VERSION 5.8 ;
BUSBITCHARS "[]" ;
DIVIDERCHAR "/" ;
UNITS
    DATABASE MICRONS 1000 ;
END UNITS

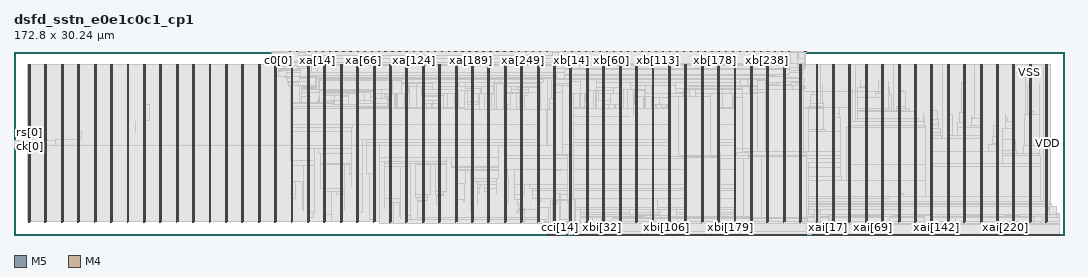
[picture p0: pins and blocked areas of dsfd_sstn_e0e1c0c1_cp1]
MACRO dsfd_sstn_e0e1c0c1_cp1
  FOREIGN dsfd_sstn_e0e1c0c1_cp1 0 0 ;
  CLASS BLOCK ;
  SIZE 172.8 BY 30.24 ;
  PIN c0[0]
    DIRECTION INPUT ;
    USE SIGNAL ;
    PORT
      LAYER M5 ;
        RECT  43.584 30.156 43.608 30.24 ;
    END
  END c0[0]
  PIN c0[1]
    DIRECTION INPUT ;
    USE SIGNAL ;
    PORT
      LAYER M5 ;
        RECT  43.728 30.156 43.752 30.24 ;
    END
  END c0[1]
  PIN c1[0]
    DIRECTION INPUT ;
    USE SIGNAL ;
    PORT
      LAYER M5 ;
        RECT  130.176 30.156 130.2 30.24 ;
    END
  END c1[0]
  PIN c1[1]
    DIRECTION INPUT ;
    USE SIGNAL ;
    PORT
      LAYER M5 ;
        RECT  130.32 30.156 130.344 30.24 ;
    END
  END c1[1]
  PIN cc[0]
    DIRECTION OUTPUT ;
    USE SIGNAL ;
    PORT
      LAYER M5 ;
        RECT  44.832 30.156 44.856 30.24 ;
    END
  END cc[0]
  PIN cc[10]
    DIRECTION OUTPUT ;
    USE SIGNAL ;
    PORT
      LAYER M5 ;
        RECT  46.272 30.156 46.296 30.24 ;
    END
  END cc[10]
  PIN cc[11]
    DIRECTION OUTPUT ;
    USE SIGNAL ;
    PORT
      LAYER M5 ;
        RECT  46.416 30.156 46.44 30.24 ;
    END
  END cc[11]
  PIN cc[12]
    DIRECTION OUTPUT ;
    USE SIGNAL ;
    PORT
      LAYER M5 ;
        RECT  46.56 30.156 46.584 30.24 ;
    END
  END cc[12]
  PIN cc[13]
    DIRECTION OUTPUT ;
    USE SIGNAL ;
    PORT
      LAYER M5 ;
        RECT  46.704 30.156 46.728 30.24 ;
    END
  END cc[13]
  PIN cc[14]
    DIRECTION OUTPUT ;
    USE SIGNAL ;
    PORT
      LAYER M5 ;
        RECT  46.848 30.156 46.872 30.24 ;
    END
  END cc[14]
  PIN cc[1]
    DIRECTION OUTPUT ;
    USE SIGNAL ;
    PORT
      LAYER M5 ;
        RECT  44.976 30.156 45 30.24 ;
    END
  END cc[1]
  PIN cc[2]
    DIRECTION OUTPUT ;
    USE SIGNAL ;
    PORT
      LAYER M5 ;
        RECT  45.12 30.156 45.144 30.24 ;
    END
  END cc[2]
  PIN cc[3]
    DIRECTION OUTPUT ;
    USE SIGNAL ;
    PORT
      LAYER M5 ;
        RECT  45.264 30.156 45.288 30.24 ;
    END
  END cc[3]
  PIN cc[4]
    DIRECTION OUTPUT ;
    USE SIGNAL ;
    PORT
      LAYER M5 ;
        RECT  45.408 30.156 45.432 30.24 ;
    END
  END cc[4]
  PIN cc[5]
    DIRECTION OUTPUT ;
    USE SIGNAL ;
    PORT
      LAYER M5 ;
        RECT  45.552 30.156 45.576 30.24 ;
    END
  END cc[5]
  PIN cc[6]
    DIRECTION OUTPUT ;
    USE SIGNAL ;
    PORT
      LAYER M5 ;
        RECT  45.696 30.156 45.72 30.24 ;
    END
  END cc[6]
  PIN cc[7]
    DIRECTION OUTPUT ;
    USE SIGNAL ;
    PORT
      LAYER M5 ;
        RECT  45.84 30.156 45.864 30.24 ;
    END
  END cc[7]
  PIN cc[8]
    DIRECTION OUTPUT ;
    USE SIGNAL ;
    PORT
      LAYER M5 ;
        RECT  45.984 30.156 46.008 30.24 ;
    END
  END cc[8]
  PIN cc[9]
    DIRECTION OUTPUT ;
    USE SIGNAL ;
    PORT
      LAYER M5 ;
        RECT  46.128 30.156 46.152 30.24 ;
    END
  END cc[9]
  PIN cci[0]
    DIRECTION INPUT ;
    USE SIGNAL ;
    PORT
      LAYER M5 ;
        RECT  87.792 0 87.816 0.084 ;
    END
  END cci[0]
  PIN cci[10]
    DIRECTION INPUT ;
    USE SIGNAL ;
    PORT
      LAYER M5 ;
        RECT  89.232 0 89.256 0.084 ;
    END
  END cci[10]
  PIN cci[11]
    DIRECTION INPUT ;
    USE SIGNAL ;
    PORT
      LAYER M5 ;
        RECT  89.376 0 89.4 0.084 ;
    END
  END cci[11]
  PIN cci[12]
    DIRECTION INPUT ;
    USE SIGNAL ;
    PORT
      LAYER M5 ;
        RECT  89.52 0 89.544 0.084 ;
    END
  END cci[12]
  PIN cci[13]
    DIRECTION INPUT ;
    USE SIGNAL ;
    PORT
      LAYER M5 ;
        RECT  89.664 0 89.688 0.084 ;
    END
  END cci[13]
  PIN cci[14]
    DIRECTION INPUT ;
    USE SIGNAL ;
    PORT
      LAYER M5 ;
        RECT  89.808 0 89.832 0.084 ;
    END
  END cci[14]
  PIN cci[1]
    DIRECTION INPUT ;
    USE SIGNAL ;
    PORT
      LAYER M5 ;
        RECT  87.936 0 87.96 0.084 ;
    END
  END cci[1]
  PIN cci[2]
    DIRECTION INPUT ;
    USE SIGNAL ;
    PORT
      LAYER M5 ;
        RECT  88.08 0 88.104 0.084 ;
    END
  END cci[2]
  PIN cci[3]
    DIRECTION INPUT ;
    USE SIGNAL ;
    PORT
      LAYER M5 ;
        RECT  88.224 0 88.248 0.084 ;
    END
  END cci[3]
  PIN cci[4]
    DIRECTION INPUT ;
    USE SIGNAL ;
    PORT
      LAYER M5 ;
        RECT  88.368 0 88.392 0.084 ;
    END
  END cci[4]
  PIN cci[5]
    DIRECTION INPUT ;
    USE SIGNAL ;
    PORT
      LAYER M5 ;
        RECT  88.512 0 88.536 0.084 ;
    END
  END cci[5]
  PIN cci[6]
    DIRECTION INPUT ;
    USE SIGNAL ;
    PORT
      LAYER M5 ;
        RECT  88.656 0 88.68 0.084 ;
    END
  END cci[6]
  PIN cci[7]
    DIRECTION INPUT ;
    USE SIGNAL ;
    PORT
      LAYER M5 ;
        RECT  88.8 0 88.824 0.084 ;
    END
  END cci[7]
  PIN cci[8]
    DIRECTION INPUT ;
    USE SIGNAL ;
    PORT
      LAYER M5 ;
        RECT  88.944 0 88.968 0.084 ;
    END
  END cci[8]
  PIN cci[9]
    DIRECTION INPUT ;
    USE SIGNAL ;
    PORT
      LAYER M5 ;
        RECT  89.088 0 89.112 0.084 ;
    END
  END cci[9]
  PIN ck[0]
    DIRECTION INPUT ;
    USE SIGNAL ;
    PORT
      LAYER M4 ;
        RECT  0 14.592 0.084 14.616 ;
    END
    PORT
      LAYER M4 ;
        RECT  0.06 14.592 0.097 14.616 ;
    END
  END ck[0]
  PIN e0[0]
    DIRECTION INPUT ;
    USE SIGNAL ;
    PORT
      LAYER M5 ;
        RECT  42.336 30.156 42.36 30.24 ;
    END
  END e0[0]
  PIN e0[1]
    DIRECTION INPUT ;
    USE SIGNAL ;
    PORT
      LAYER M5 ;
        RECT  42.48 30.156 42.504 30.24 ;
    END
  END e0[1]
  PIN e1[0]
    DIRECTION INPUT ;
    USE SIGNAL ;
    PORT
      LAYER M5 ;
        RECT  128.928 30.156 128.952 30.24 ;
    END
  END e1[0]
  PIN e1[1]
    DIRECTION INPUT ;
    USE SIGNAL ;
    PORT
      LAYER M5 ;
        RECT  129.072 30.156 129.096 30.24 ;
    END
  END e1[1]
  PIN rs[0]
    DIRECTION INPUT ;
    USE SIGNAL ;
    PORT
      LAYER M4 ;
        RECT  0 15.6 0.084 15.624 ;
    END
    PORT
      LAYER M4 ;
        RECT  0.06 15.6 0.097 15.624 ;
    END
  END rs[0]
  PIN so[0]
    DIRECTION OUTPUT ;
    USE SIGNAL ;
    PORT
      LAYER M5 ;
        RECT  90.912 0 90.936 0.084 ;
    END
  END so[0]
  PIN so[1]
    DIRECTION OUTPUT ;
    USE SIGNAL ;
    PORT
      LAYER M5 ;
        RECT  91.056 0 91.08 0.084 ;
    END
  END so[1]
  PIN xa[0]
    DIRECTION OUTPUT ;
    USE SIGNAL ;
    PORT
      LAYER M5 ;
        RECT  47.952 30.156 47.976 30.24 ;
    END
  END xa[0]
  PIN xa[100]
    DIRECTION OUTPUT ;
    USE SIGNAL ;
    PORT
      LAYER M5 ;
        RECT  62.352 30.156 62.376 30.24 ;
    END
  END xa[100]
  PIN xa[101]
    DIRECTION OUTPUT ;
    USE SIGNAL ;
    PORT
      LAYER M5 ;
        RECT  62.496 30.156 62.52 30.24 ;
    END
  END xa[101]
  PIN xa[102]
    DIRECTION OUTPUT ;
    USE SIGNAL ;
    PORT
      LAYER M5 ;
        RECT  62.64 30.156 62.664 30.24 ;
    END
  END xa[102]
  PIN xa[103]
    DIRECTION OUTPUT ;
    USE SIGNAL ;
    PORT
      LAYER M5 ;
        RECT  62.784 30.156 62.808 30.24 ;
    END
  END xa[103]
  PIN xa[104]
    DIRECTION OUTPUT ;
    USE SIGNAL ;
    PORT
      LAYER M5 ;
        RECT  62.928 30.156 62.952 30.24 ;
    END
  END xa[104]
  PIN xa[105]
    DIRECTION OUTPUT ;
    USE SIGNAL ;
    PORT
      LAYER M5 ;
        RECT  63.072 30.156 63.096 30.24 ;
    END
  END xa[105]
  PIN xa[106]
    DIRECTION OUTPUT ;
    USE SIGNAL ;
    PORT
      LAYER M5 ;
        RECT  63.216 30.156 63.24 30.24 ;
    END
  END xa[106]
  PIN xa[107]
    DIRECTION OUTPUT ;
    USE SIGNAL ;
    PORT
      LAYER M5 ;
        RECT  63.36 30.156 63.384 30.24 ;
    END
  END xa[107]
  PIN xa[108]
    DIRECTION OUTPUT ;
    USE SIGNAL ;
    PORT
      LAYER M5 ;
        RECT  63.504 30.156 63.528 30.24 ;
    END
  END xa[108]
  PIN xa[109]
    DIRECTION OUTPUT ;
    USE SIGNAL ;
    PORT
      LAYER M5 ;
        RECT  63.648 30.156 63.672 30.24 ;
    END
  END xa[109]
  PIN xa[10]
    DIRECTION OUTPUT ;
    USE SIGNAL ;
    PORT
      LAYER M5 ;
        RECT  49.392 30.156 49.416 30.24 ;
    END
  END xa[10]
  PIN xa[110]
    DIRECTION OUTPUT ;
    USE SIGNAL ;
    PORT
      LAYER M5 ;
        RECT  63.792 30.156 63.816 30.24 ;
    END
  END xa[110]
  PIN xa[111]
    DIRECTION OUTPUT ;
    USE SIGNAL ;
    PORT
      LAYER M5 ;
        RECT  63.936 30.156 63.96 30.24 ;
    END
  END xa[111]
  PIN xa[112]
    DIRECTION OUTPUT ;
    USE SIGNAL ;
    PORT
      LAYER M5 ;
        RECT  64.08 30.156 64.104 30.24 ;
    END
  END xa[112]
  PIN xa[113]
    DIRECTION OUTPUT ;
    USE SIGNAL ;
    PORT
      LAYER M5 ;
        RECT  64.224 30.156 64.248 30.24 ;
    END
  END xa[113]
  PIN xa[114]
    DIRECTION OUTPUT ;
    USE SIGNAL ;
    PORT
      LAYER M5 ;
        RECT  64.368 30.156 64.392 30.24 ;
    END
  END xa[114]
  PIN xa[115]
    DIRECTION OUTPUT ;
    USE SIGNAL ;
    PORT
      LAYER M5 ;
        RECT  64.512 30.156 64.536 30.24 ;
    END
  END xa[115]
  PIN xa[116]
    DIRECTION OUTPUT ;
    USE SIGNAL ;
    PORT
      LAYER M5 ;
        RECT  64.656 30.156 64.68 30.24 ;
    END
  END xa[116]
  PIN xa[117]
    DIRECTION OUTPUT ;
    USE SIGNAL ;
    PORT
      LAYER M5 ;
        RECT  64.8 30.156 64.824 30.24 ;
    END
  END xa[117]
  PIN xa[118]
    DIRECTION OUTPUT ;
    USE SIGNAL ;
    PORT
      LAYER M5 ;
        RECT  64.944 30.156 64.968 30.24 ;
    END
  END xa[118]
  PIN xa[119]
    DIRECTION OUTPUT ;
    USE SIGNAL ;
    PORT
      LAYER M5 ;
        RECT  65.088 30.156 65.112 30.24 ;
    END
  END xa[119]
  PIN xa[11]
    DIRECTION OUTPUT ;
    USE SIGNAL ;
    PORT
      LAYER M5 ;
        RECT  49.536 30.156 49.56 30.24 ;
    END
  END xa[11]
  PIN xa[120]
    DIRECTION OUTPUT ;
    USE SIGNAL ;
    PORT
      LAYER M5 ;
        RECT  65.232 30.156 65.256 30.24 ;
    END
  END xa[120]
  PIN xa[121]
    DIRECTION OUTPUT ;
    USE SIGNAL ;
    PORT
      LAYER M5 ;
        RECT  65.376 30.156 65.4 30.24 ;
    END
  END xa[121]
  PIN xa[122]
    DIRECTION OUTPUT ;
    USE SIGNAL ;
    PORT
      LAYER M5 ;
        RECT  65.52 30.156 65.544 30.24 ;
    END
  END xa[122]
  PIN xa[123]
    DIRECTION OUTPUT ;
    USE SIGNAL ;
    PORT
      LAYER M5 ;
        RECT  65.664 30.156 65.688 30.24 ;
    END
  END xa[123]
  PIN xa[124]
    DIRECTION OUTPUT ;
    USE SIGNAL ;
    PORT
      LAYER M5 ;
        RECT  65.808 30.156 65.832 30.24 ;
    END
  END xa[124]
  PIN xa[125]
    DIRECTION OUTPUT ;
    USE SIGNAL ;
    PORT
      LAYER M5 ;
        RECT  65.952 30.156 65.976 30.24 ;
    END
  END xa[125]
  PIN xa[126]
    DIRECTION OUTPUT ;
    USE SIGNAL ;
    PORT
      LAYER M5 ;
        RECT  66.096 30.156 66.12 30.24 ;
    END
  END xa[126]
  PIN xa[127]
    DIRECTION OUTPUT ;
    USE SIGNAL ;
    PORT
      LAYER M5 ;
        RECT  66.24 30.156 66.264 30.24 ;
    END
  END xa[127]
  PIN xa[128]
    DIRECTION OUTPUT ;
    USE SIGNAL ;
    PORT
      LAYER M5 ;
        RECT  66.384 30.156 66.408 30.24 ;
    END
  END xa[128]
  PIN xa[129]
    DIRECTION OUTPUT ;
    USE SIGNAL ;
    PORT
      LAYER M5 ;
        RECT  66.528 30.156 66.552 30.24 ;
    END
  END xa[129]
  PIN xa[12]
    DIRECTION OUTPUT ;
    USE SIGNAL ;
    PORT
      LAYER M5 ;
        RECT  49.68 30.156 49.704 30.24 ;
    END
  END xa[12]
  PIN xa[130]
    DIRECTION OUTPUT ;
    USE SIGNAL ;
    PORT
      LAYER M5 ;
        RECT  66.672 30.156 66.696 30.24 ;
    END
  END xa[130]
  PIN xa[131]
    DIRECTION OUTPUT ;
    USE SIGNAL ;
    PORT
      LAYER M5 ;
        RECT  66.816 30.156 66.84 30.24 ;
    END
  END xa[131]
  PIN xa[132]
    DIRECTION OUTPUT ;
    USE SIGNAL ;
    PORT
      LAYER M5 ;
        RECT  66.96 30.156 66.984 30.24 ;
    END
  END xa[132]
  PIN xa[133]
    DIRECTION OUTPUT ;
    USE SIGNAL ;
    PORT
      LAYER M5 ;
        RECT  67.104 30.156 67.128 30.24 ;
    END
  END xa[133]
  PIN xa[134]
    DIRECTION OUTPUT ;
    USE SIGNAL ;
    PORT
      LAYER M5 ;
        RECT  67.248 30.156 67.272 30.24 ;
    END
  END xa[134]
  PIN xa[135]
    DIRECTION OUTPUT ;
    USE SIGNAL ;
    PORT
      LAYER M5 ;
        RECT  67.392 30.156 67.416 30.24 ;
    END
  END xa[135]
  PIN xa[136]
    DIRECTION OUTPUT ;
    USE SIGNAL ;
    PORT
      LAYER M5 ;
        RECT  67.536 30.156 67.56 30.24 ;
    END
  END xa[136]
  PIN xa[137]
    DIRECTION OUTPUT ;
    USE SIGNAL ;
    PORT
      LAYER M5 ;
        RECT  67.68 30.156 67.704 30.24 ;
    END
  END xa[137]
  PIN xa[138]
    DIRECTION OUTPUT ;
    USE SIGNAL ;
    PORT
      LAYER M5 ;
        RECT  67.824 30.156 67.848 30.24 ;
    END
  END xa[138]
  PIN xa[139]
    DIRECTION OUTPUT ;
    USE SIGNAL ;
    PORT
      LAYER M5 ;
        RECT  67.968 30.156 67.992 30.24 ;
    END
  END xa[139]
  PIN xa[13]
    DIRECTION OUTPUT ;
    USE SIGNAL ;
    PORT
      LAYER M5 ;
        RECT  49.824 30.156 49.848 30.24 ;
    END
  END xa[13]
  PIN xa[140]
    DIRECTION OUTPUT ;
    USE SIGNAL ;
    PORT
      LAYER M5 ;
        RECT  68.112 30.156 68.136 30.24 ;
    END
  END xa[140]
  PIN xa[141]
    DIRECTION OUTPUT ;
    USE SIGNAL ;
    PORT
      LAYER M5 ;
        RECT  68.256 30.156 68.28 30.24 ;
    END
  END xa[141]
  PIN xa[142]
    DIRECTION OUTPUT ;
    USE SIGNAL ;
    PORT
      LAYER M5 ;
        RECT  68.4 30.156 68.424 30.24 ;
    END
  END xa[142]
  PIN xa[143]
    DIRECTION OUTPUT ;
    USE SIGNAL ;
    PORT
      LAYER M5 ;
        RECT  68.544 30.156 68.568 30.24 ;
    END
  END xa[143]
  PIN xa[144]
    DIRECTION OUTPUT ;
    USE SIGNAL ;
    PORT
      LAYER M5 ;
        RECT  68.688 30.156 68.712 30.24 ;
    END
  END xa[144]
  PIN xa[145]
    DIRECTION OUTPUT ;
    USE SIGNAL ;
    PORT
      LAYER M5 ;
        RECT  68.832 30.156 68.856 30.24 ;
    END
  END xa[145]
  PIN xa[146]
    DIRECTION OUTPUT ;
    USE SIGNAL ;
    PORT
      LAYER M5 ;
        RECT  68.976 30.156 69 30.24 ;
    END
  END xa[146]
  PIN xa[147]
    DIRECTION OUTPUT ;
    USE SIGNAL ;
    PORT
      LAYER M5 ;
        RECT  69.12 30.156 69.144 30.24 ;
    END
  END xa[147]
  PIN xa[148]
    DIRECTION OUTPUT ;
    USE SIGNAL ;
    PORT
      LAYER M5 ;
        RECT  69.264 30.156 69.288 30.24 ;
    END
  END xa[148]
  PIN xa[149]
    DIRECTION OUTPUT ;
    USE SIGNAL ;
    PORT
      LAYER M5 ;
        RECT  69.408 30.156 69.432 30.24 ;
    END
  END xa[149]
  PIN xa[14]
    DIRECTION OUTPUT ;
    USE SIGNAL ;
    PORT
      LAYER M5 ;
        RECT  49.968 30.156 49.992 30.24 ;
    END
  END xa[14]
  PIN xa[150]
    DIRECTION OUTPUT ;
    USE SIGNAL ;
    PORT
      LAYER M5 ;
        RECT  69.552 30.156 69.576 30.24 ;
    END
  END xa[150]
  PIN xa[151]
    DIRECTION OUTPUT ;
    USE SIGNAL ;
    PORT
      LAYER M5 ;
        RECT  69.696 30.156 69.72 30.24 ;
    END
  END xa[151]
  PIN xa[152]
    DIRECTION OUTPUT ;
    USE SIGNAL ;
    PORT
      LAYER M5 ;
        RECT  69.84 30.156 69.864 30.24 ;
    END
  END xa[152]
  PIN xa[153]
    DIRECTION OUTPUT ;
    USE SIGNAL ;
    PORT
      LAYER M5 ;
        RECT  69.984 30.156 70.008 30.24 ;
    END
  END xa[153]
  PIN xa[154]
    DIRECTION OUTPUT ;
    USE SIGNAL ;
    PORT
      LAYER M5 ;
        RECT  70.128 30.156 70.152 30.24 ;
    END
  END xa[154]
  PIN xa[155]
    DIRECTION OUTPUT ;
    USE SIGNAL ;
    PORT
      LAYER M5 ;
        RECT  70.272 30.156 70.296 30.24 ;
    END
  END xa[155]
  PIN xa[156]
    DIRECTION OUTPUT ;
    USE SIGNAL ;
    PORT
      LAYER M5 ;
        RECT  70.416 30.156 70.44 30.24 ;
    END
  END xa[156]
  PIN xa[157]
    DIRECTION OUTPUT ;
    USE SIGNAL ;
    PORT
      LAYER M5 ;
        RECT  70.56 30.156 70.584 30.24 ;
    END
  END xa[157]
  PIN xa[158]
    DIRECTION OUTPUT ;
    USE SIGNAL ;
    PORT
      LAYER M5 ;
        RECT  70.704 30.156 70.728 30.24 ;
    END
  END xa[158]
  PIN xa[159]
    DIRECTION OUTPUT ;
    USE SIGNAL ;
    PORT
      LAYER M5 ;
        RECT  70.848 30.156 70.872 30.24 ;
    END
  END xa[159]
  PIN xa[15]
    DIRECTION OUTPUT ;
    USE SIGNAL ;
    PORT
      LAYER M5 ;
        RECT  50.112 30.156 50.136 30.24 ;
    END
  END xa[15]
  PIN xa[160]
    DIRECTION OUTPUT ;
    USE SIGNAL ;
    PORT
      LAYER M5 ;
        RECT  70.992 30.156 71.016 30.24 ;
    END
  END xa[160]
  PIN xa[161]
    DIRECTION OUTPUT ;
    USE SIGNAL ;
    PORT
      LAYER M5 ;
        RECT  71.136 30.156 71.16 30.24 ;
    END
  END xa[161]
  PIN xa[162]
    DIRECTION OUTPUT ;
    USE SIGNAL ;
    PORT
      LAYER M5 ;
        RECT  71.28 30.156 71.304 30.24 ;
    END
  END xa[162]
  PIN xa[163]
    DIRECTION OUTPUT ;
    USE SIGNAL ;
    PORT
      LAYER M5 ;
        RECT  71.424 30.156 71.448 30.24 ;
    END
  END xa[163]
  PIN xa[164]
    DIRECTION OUTPUT ;
    USE SIGNAL ;
    PORT
      LAYER M5 ;
        RECT  71.568 30.156 71.592 30.24 ;
    END
  END xa[164]
  PIN xa[165]
    DIRECTION OUTPUT ;
    USE SIGNAL ;
    PORT
      LAYER M5 ;
        RECT  71.712 30.156 71.736 30.24 ;
    END
  END xa[165]
  PIN xa[166]
    DIRECTION OUTPUT ;
    USE SIGNAL ;
    PORT
      LAYER M5 ;
        RECT  71.856 30.156 71.88 30.24 ;
    END
  END xa[166]
  PIN xa[167]
    DIRECTION OUTPUT ;
    USE SIGNAL ;
    PORT
      LAYER M5 ;
        RECT  72 30.156 72.024 30.24 ;
    END
  END xa[167]
  PIN xa[168]
    DIRECTION OUTPUT ;
    USE SIGNAL ;
    PORT
      LAYER M5 ;
        RECT  72.144 30.156 72.168 30.24 ;
    END
  END xa[168]
  PIN xa[169]
    DIRECTION OUTPUT ;
    USE SIGNAL ;
    PORT
      LAYER M5 ;
        RECT  72.288 30.156 72.312 30.24 ;
    END
  END xa[169]
  PIN xa[16]
    DIRECTION OUTPUT ;
    USE SIGNAL ;
    PORT
      LAYER M5 ;
        RECT  50.256 30.156 50.28 30.24 ;
    END
  END xa[16]
  PIN xa[170]
    DIRECTION OUTPUT ;
    USE SIGNAL ;
    PORT
      LAYER M5 ;
        RECT  72.432 30.156 72.456 30.24 ;
    END
  END xa[170]
  PIN xa[171]
    DIRECTION OUTPUT ;
    USE SIGNAL ;
    PORT
      LAYER M5 ;
        RECT  72.576 30.156 72.6 30.24 ;
    END
  END xa[171]
  PIN xa[172]
    DIRECTION OUTPUT ;
    USE SIGNAL ;
    PORT
      LAYER M5 ;
        RECT  72.72 30.156 72.744 30.24 ;
    END
  END xa[172]
  PIN xa[173]
    DIRECTION OUTPUT ;
    USE SIGNAL ;
    PORT
      LAYER M5 ;
        RECT  72.864 30.156 72.888 30.24 ;
    END
  END xa[173]
  PIN xa[174]
    DIRECTION OUTPUT ;
    USE SIGNAL ;
    PORT
      LAYER M5 ;
        RECT  73.008 30.156 73.032 30.24 ;
    END
  END xa[174]
  PIN xa[175]
    DIRECTION OUTPUT ;
    USE SIGNAL ;
    PORT
      LAYER M5 ;
        RECT  73.152 30.156 73.176 30.24 ;
    END
  END xa[175]
  PIN xa[176]
    DIRECTION OUTPUT ;
    USE SIGNAL ;
    PORT
      LAYER M5 ;
        RECT  73.296 30.156 73.32 30.24 ;
    END
  END xa[176]
  PIN xa[177]
    DIRECTION OUTPUT ;
    USE SIGNAL ;
    PORT
      LAYER M5 ;
        RECT  73.44 30.156 73.464 30.24 ;
    END
  END xa[177]
  PIN xa[178]
    DIRECTION OUTPUT ;
    USE SIGNAL ;
    PORT
      LAYER M5 ;
        RECT  73.584 30.156 73.608 30.24 ;
    END
  END xa[178]
  PIN xa[179]
    DIRECTION OUTPUT ;
    USE SIGNAL ;
    PORT
      LAYER M5 ;
        RECT  73.728 30.156 73.752 30.24 ;
    END
  END xa[179]
  PIN xa[17]
    DIRECTION OUTPUT ;
    USE SIGNAL ;
    PORT
      LAYER M5 ;
        RECT  50.4 30.156 50.424 30.24 ;
    END
  END xa[17]
  PIN xa[180]
    DIRECTION OUTPUT ;
    USE SIGNAL ;
    PORT
      LAYER M5 ;
        RECT  73.872 30.156 73.896 30.24 ;
    END
  END xa[180]
  PIN xa[181]
    DIRECTION OUTPUT ;
    USE SIGNAL ;
    PORT
      LAYER M5 ;
        RECT  74.016 30.156 74.04 30.24 ;
    END
  END xa[181]
  PIN xa[182]
    DIRECTION OUTPUT ;
    USE SIGNAL ;
    PORT
      LAYER M5 ;
        RECT  74.16 30.156 74.184 30.24 ;
    END
  END xa[182]
  PIN xa[183]
    DIRECTION OUTPUT ;
    USE SIGNAL ;
    PORT
      LAYER M5 ;
        RECT  74.304 30.156 74.328 30.24 ;
    END
  END xa[183]
  PIN xa[184]
    DIRECTION OUTPUT ;
    USE SIGNAL ;
    PORT
      LAYER M5 ;
        RECT  74.448 30.156 74.472 30.24 ;
    END
  END xa[184]
  PIN xa[185]
    DIRECTION OUTPUT ;
    USE SIGNAL ;
    PORT
      LAYER M5 ;
        RECT  74.592 30.156 74.616 30.24 ;
    END
  END xa[185]
  PIN xa[186]
    DIRECTION OUTPUT ;
    USE SIGNAL ;
    PORT
      LAYER M5 ;
        RECT  74.736 30.156 74.76 30.24 ;
    END
  END xa[186]
  PIN xa[187]
    DIRECTION OUTPUT ;
    USE SIGNAL ;
    PORT
      LAYER M5 ;
        RECT  74.88 30.156 74.904 30.24 ;
    END
  END xa[187]
  PIN xa[188]
    DIRECTION OUTPUT ;
    USE SIGNAL ;
    PORT
      LAYER M5 ;
        RECT  75.024 30.156 75.048 30.24 ;
    END
  END xa[188]
  PIN xa[189]
    DIRECTION OUTPUT ;
    USE SIGNAL ;
    PORT
      LAYER M5 ;
        RECT  75.168 30.156 75.192 30.24 ;
    END
  END xa[189]
  PIN xa[18]
    DIRECTION OUTPUT ;
    USE SIGNAL ;
    PORT
      LAYER M5 ;
        RECT  50.544 30.156 50.568 30.24 ;
    END
  END xa[18]
  PIN xa[190]
    DIRECTION OUTPUT ;
    USE SIGNAL ;
    PORT
      LAYER M5 ;
        RECT  75.312 30.156 75.336 30.24 ;
    END
  END xa[190]
  PIN xa[191]
    DIRECTION OUTPUT ;
    USE SIGNAL ;
    PORT
      LAYER M5 ;
        RECT  75.456 30.156 75.48 30.24 ;
    END
  END xa[191]
  PIN xa[192]
    DIRECTION OUTPUT ;
    USE SIGNAL ;
    PORT
      LAYER M5 ;
        RECT  75.6 30.156 75.624 30.24 ;
    END
  END xa[192]
  PIN xa[193]
    DIRECTION OUTPUT ;
    USE SIGNAL ;
    PORT
      LAYER M5 ;
        RECT  75.744 30.156 75.768 30.24 ;
    END
  END xa[193]
  PIN xa[194]
    DIRECTION OUTPUT ;
    USE SIGNAL ;
    PORT
      LAYER M5 ;
        RECT  75.888 30.156 75.912 30.24 ;
    END
  END xa[194]
  PIN xa[195]
    DIRECTION OUTPUT ;
    USE SIGNAL ;
    PORT
      LAYER M5 ;
        RECT  76.032 30.156 76.056 30.24 ;
    END
  END xa[195]
  PIN xa[196]
    DIRECTION OUTPUT ;
    USE SIGNAL ;
    PORT
      LAYER M5 ;
        RECT  76.176 30.156 76.2 30.24 ;
    END
  END xa[196]
  PIN xa[197]
    DIRECTION OUTPUT ;
    USE SIGNAL ;
    PORT
      LAYER M5 ;
        RECT  76.32 30.156 76.344 30.24 ;
    END
  END xa[197]
  PIN xa[198]
    DIRECTION OUTPUT ;
    USE SIGNAL ;
    PORT
      LAYER M5 ;
        RECT  76.464 30.156 76.488 30.24 ;
    END
  END xa[198]
  PIN xa[199]
    DIRECTION OUTPUT ;
    USE SIGNAL ;
    PORT
      LAYER M5 ;
        RECT  76.608 30.156 76.632 30.24 ;
    END
  END xa[199]
  PIN xa[19]
    DIRECTION OUTPUT ;
    USE SIGNAL ;
    PORT
      LAYER M5 ;
        RECT  50.688 30.156 50.712 30.24 ;
    END
  END xa[19]
  PIN xa[1]
    DIRECTION OUTPUT ;
    USE SIGNAL ;
    PORT
      LAYER M5 ;
        RECT  48.096 30.156 48.12 30.24 ;
    END
  END xa[1]
  PIN xa[200]
    DIRECTION OUTPUT ;
    USE SIGNAL ;
    PORT
      LAYER M5 ;
        RECT  76.752 30.156 76.776 30.24 ;
    END
  END xa[200]
  PIN xa[201]
    DIRECTION OUTPUT ;
    USE SIGNAL ;
    PORT
      LAYER M5 ;
        RECT  76.896 30.156 76.92 30.24 ;
    END
  END xa[201]
  PIN xa[202]
    DIRECTION OUTPUT ;
    USE SIGNAL ;
    PORT
      LAYER M5 ;
        RECT  77.04 30.156 77.064 30.24 ;
    END
  END xa[202]
  PIN xa[203]
    DIRECTION OUTPUT ;
    USE SIGNAL ;
    PORT
      LAYER M5 ;
        RECT  77.184 30.156 77.208 30.24 ;
    END
  END xa[203]
  PIN xa[204]
    DIRECTION OUTPUT ;
    USE SIGNAL ;
    PORT
      LAYER M5 ;
        RECT  77.328 30.156 77.352 30.24 ;
    END
  END xa[204]
  PIN xa[205]
    DIRECTION OUTPUT ;
    USE SIGNAL ;
    PORT
      LAYER M5 ;
        RECT  77.472 30.156 77.496 30.24 ;
    END
  END xa[205]
  PIN xa[206]
    DIRECTION OUTPUT ;
    USE SIGNAL ;
    PORT
      LAYER M5 ;
        RECT  77.616 30.156 77.64 30.24 ;
    END
  END xa[206]
  PIN xa[207]
    DIRECTION OUTPUT ;
    USE SIGNAL ;
    PORT
      LAYER M5 ;
        RECT  77.76 30.156 77.784 30.24 ;
    END
  END xa[207]
  PIN xa[208]
    DIRECTION OUTPUT ;
    USE SIGNAL ;
    PORT
      LAYER M5 ;
        RECT  77.904 30.156 77.928 30.24 ;
    END
  END xa[208]
  PIN xa[209]
    DIRECTION OUTPUT ;
    USE SIGNAL ;
    PORT
      LAYER M5 ;
        RECT  78.048 30.156 78.072 30.24 ;
    END
  END xa[209]
  PIN xa[20]
    DIRECTION OUTPUT ;
    USE SIGNAL ;
    PORT
      LAYER M5 ;
        RECT  50.832 30.156 50.856 30.24 ;
    END
  END xa[20]
  PIN xa[210]
    DIRECTION OUTPUT ;
    USE SIGNAL ;
    PORT
      LAYER M5 ;
        RECT  78.192 30.156 78.216 30.24 ;
    END
  END xa[210]
  PIN xa[211]
    DIRECTION OUTPUT ;
    USE SIGNAL ;
    PORT
      LAYER M5 ;
        RECT  78.336 30.156 78.36 30.24 ;
    END
  END xa[211]
  PIN xa[212]
    DIRECTION OUTPUT ;
    USE SIGNAL ;
    PORT
      LAYER M5 ;
        RECT  78.48 30.156 78.504 30.24 ;
    END
  END xa[212]
  PIN xa[213]
    DIRECTION OUTPUT ;
    USE SIGNAL ;
    PORT
      LAYER M5 ;
        RECT  78.624 30.156 78.648 30.24 ;
    END
  END xa[213]
  PIN xa[214]
    DIRECTION OUTPUT ;
    USE SIGNAL ;
    PORT
      LAYER M5 ;
        RECT  78.768 30.156 78.792 30.24 ;
    END
  END xa[214]
  PIN xa[215]
    DIRECTION OUTPUT ;
    USE SIGNAL ;
    PORT
      LAYER M5 ;
        RECT  78.912 30.156 78.936 30.24 ;
    END
  END xa[215]
  PIN xa[216]
    DIRECTION OUTPUT ;
    USE SIGNAL ;
    PORT
      LAYER M5 ;
        RECT  79.056 30.156 79.08 30.24 ;
    END
  END xa[216]
  PIN xa[217]
    DIRECTION OUTPUT ;
    USE SIGNAL ;
    PORT
      LAYER M5 ;
        RECT  79.2 30.156 79.224 30.24 ;
    END
  END xa[217]
  PIN xa[218]
    DIRECTION OUTPUT ;
    USE SIGNAL ;
    PORT
      LAYER M5 ;
        RECT  79.344 30.156 79.368 30.24 ;
    END
  END xa[218]
  PIN xa[219]
    DIRECTION OUTPUT ;
    USE SIGNAL ;
    PORT
      LAYER M5 ;
        RECT  79.488 30.156 79.512 30.24 ;
    END
  END xa[219]
  PIN xa[21]
    DIRECTION OUTPUT ;
    USE SIGNAL ;
    PORT
      LAYER M5 ;
        RECT  50.976 30.156 51 30.24 ;
    END
  END xa[21]
  PIN xa[220]
    DIRECTION OUTPUT ;
    USE SIGNAL ;
    PORT
      LAYER M5 ;
        RECT  79.632 30.156 79.656 30.24 ;
    END
  END xa[220]
  PIN xa[221]
    DIRECTION OUTPUT ;
    USE SIGNAL ;
    PORT
      LAYER M5 ;
        RECT  79.776 30.156 79.8 30.24 ;
    END
  END xa[221]
  PIN xa[222]
    DIRECTION OUTPUT ;
    USE SIGNAL ;
    PORT
      LAYER M5 ;
        RECT  79.92 30.156 79.944 30.24 ;
    END
  END xa[222]
  PIN xa[223]
    DIRECTION OUTPUT ;
    USE SIGNAL ;
    PORT
      LAYER M5 ;
        RECT  80.064 30.156 80.088 30.24 ;
    END
  END xa[223]
  PIN xa[224]
    DIRECTION OUTPUT ;
    USE SIGNAL ;
    PORT
      LAYER M5 ;
        RECT  80.208 30.156 80.232 30.24 ;
    END
  END xa[224]
  PIN xa[225]
    DIRECTION OUTPUT ;
    USE SIGNAL ;
    PORT
      LAYER M5 ;
        RECT  80.352 30.156 80.376 30.24 ;
    END
  END xa[225]
  PIN xa[226]
    DIRECTION OUTPUT ;
    USE SIGNAL ;
    PORT
      LAYER M5 ;
        RECT  80.496 30.156 80.52 30.24 ;
    END
  END xa[226]
  PIN xa[227]
    DIRECTION OUTPUT ;
    USE SIGNAL ;
    PORT
      LAYER M5 ;
        RECT  80.64 30.156 80.664 30.24 ;
    END
  END xa[227]
  PIN xa[228]
    DIRECTION OUTPUT ;
    USE SIGNAL ;
    PORT
      LAYER M5 ;
        RECT  80.784 30.156 80.808 30.24 ;
    END
  END xa[228]
  PIN xa[229]
    DIRECTION OUTPUT ;
    USE SIGNAL ;
    PORT
      LAYER M5 ;
        RECT  80.928 30.156 80.952 30.24 ;
    END
  END xa[229]
  PIN xa[22]
    DIRECTION OUTPUT ;
    USE SIGNAL ;
    PORT
      LAYER M5 ;
        RECT  51.12 30.156 51.144 30.24 ;
    END
  END xa[22]
  PIN xa[230]
    DIRECTION OUTPUT ;
    USE SIGNAL ;
    PORT
      LAYER M5 ;
        RECT  81.072 30.156 81.096 30.24 ;
    END
  END xa[230]
  PIN xa[231]
    DIRECTION OUTPUT ;
    USE SIGNAL ;
    PORT
      LAYER M5 ;
        RECT  81.216 30.156 81.24 30.24 ;
    END
  END xa[231]
  PIN xa[232]
    DIRECTION OUTPUT ;
    USE SIGNAL ;
    PORT
      LAYER M5 ;
        RECT  81.36 30.156 81.384 30.24 ;
    END
  END xa[232]
  PIN xa[233]
    DIRECTION OUTPUT ;
    USE SIGNAL ;
    PORT
      LAYER M5 ;
        RECT  81.504 30.156 81.528 30.24 ;
    END
  END xa[233]
  PIN xa[234]
    DIRECTION OUTPUT ;
    USE SIGNAL ;
    PORT
      LAYER M5 ;
        RECT  81.648 30.156 81.672 30.24 ;
    END
  END xa[234]
  PIN xa[235]
    DIRECTION OUTPUT ;
    USE SIGNAL ;
    PORT
      LAYER M5 ;
        RECT  81.792 30.156 81.816 30.24 ;
    END
  END xa[235]
  PIN xa[236]
    DIRECTION OUTPUT ;
    USE SIGNAL ;
    PORT
      LAYER M5 ;
        RECT  81.936 30.156 81.96 30.24 ;
    END
  END xa[236]
  PIN xa[237]
    DIRECTION OUTPUT ;
    USE SIGNAL ;
    PORT
      LAYER M5 ;
        RECT  82.08 30.156 82.104 30.24 ;
    END
  END xa[237]
  PIN xa[238]
    DIRECTION OUTPUT ;
    USE SIGNAL ;
    PORT
      LAYER M5 ;
        RECT  82.224 30.156 82.248 30.24 ;
    END
  END xa[238]
  PIN xa[239]
    DIRECTION OUTPUT ;
    USE SIGNAL ;
    PORT
      LAYER M5 ;
        RECT  82.368 30.156 82.392 30.24 ;
    END
  END xa[239]
  PIN xa[23]
    DIRECTION OUTPUT ;
    USE SIGNAL ;
    PORT
      LAYER M5 ;
        RECT  51.264 30.156 51.288 30.24 ;
    END
  END xa[23]
  PIN xa[240]
    DIRECTION OUTPUT ;
    USE SIGNAL ;
    PORT
      LAYER M5 ;
        RECT  82.512 30.156 82.536 30.24 ;
    END
  END xa[240]
  PIN xa[241]
    DIRECTION OUTPUT ;
    USE SIGNAL ;
    PORT
      LAYER M5 ;
        RECT  82.656 30.156 82.68 30.24 ;
    END
  END xa[241]
  PIN xa[242]
    DIRECTION OUTPUT ;
    USE SIGNAL ;
    PORT
      LAYER M5 ;
        RECT  82.8 30.156 82.824 30.24 ;
    END
  END xa[242]
  PIN xa[243]
    DIRECTION OUTPUT ;
    USE SIGNAL ;
    PORT
      LAYER M5 ;
        RECT  82.944 30.156 82.968 30.24 ;
    END
  END xa[243]
  PIN xa[244]
    DIRECTION OUTPUT ;
    USE SIGNAL ;
    PORT
      LAYER M5 ;
        RECT  83.088 30.156 83.112 30.24 ;
    END
  END xa[244]
  PIN xa[245]
    DIRECTION OUTPUT ;
    USE SIGNAL ;
    PORT
      LAYER M5 ;
        RECT  83.232 30.156 83.256 30.24 ;
    END
  END xa[245]
  PIN xa[246]
    DIRECTION OUTPUT ;
    USE SIGNAL ;
    PORT
      LAYER M5 ;
        RECT  83.376 30.156 83.4 30.24 ;
    END
  END xa[246]
  PIN xa[247]
    DIRECTION OUTPUT ;
    USE SIGNAL ;
    PORT
      LAYER M5 ;
        RECT  83.52 30.156 83.544 30.24 ;
    END
  END xa[247]
  PIN xa[248]
    DIRECTION OUTPUT ;
    USE SIGNAL ;
    PORT
      LAYER M5 ;
        RECT  83.664 30.156 83.688 30.24 ;
    END
  END xa[248]
  PIN xa[249]
    DIRECTION OUTPUT ;
    USE SIGNAL ;
    PORT
      LAYER M5 ;
        RECT  83.808 30.156 83.832 30.24 ;
    END
  END xa[249]
  PIN xa[24]
    DIRECTION OUTPUT ;
    USE SIGNAL ;
    PORT
      LAYER M5 ;
        RECT  51.408 30.156 51.432 30.24 ;
    END
  END xa[24]
  PIN xa[250]
    DIRECTION OUTPUT ;
    USE SIGNAL ;
    PORT
      LAYER M5 ;
        RECT  83.952 30.156 83.976 30.24 ;
    END
  END xa[250]
  PIN xa[251]
    DIRECTION OUTPUT ;
    USE SIGNAL ;
    PORT
      LAYER M5 ;
        RECT  84.096 30.156 84.12 30.24 ;
    END
  END xa[251]
  PIN xa[252]
    DIRECTION OUTPUT ;
    USE SIGNAL ;
    PORT
      LAYER M5 ;
        RECT  84.24 30.156 84.264 30.24 ;
    END
  END xa[252]
  PIN xa[253]
    DIRECTION OUTPUT ;
    USE SIGNAL ;
    PORT
      LAYER M5 ;
        RECT  84.384 30.156 84.408 30.24 ;
    END
  END xa[253]
  PIN xa[254]
    DIRECTION OUTPUT ;
    USE SIGNAL ;
    PORT
      LAYER M5 ;
        RECT  84.528 30.156 84.552 30.24 ;
    END
  END xa[254]
  PIN xa[255]
    DIRECTION OUTPUT ;
    USE SIGNAL ;
    PORT
      LAYER M5 ;
        RECT  84.672 30.156 84.696 30.24 ;
    END
  END xa[255]
  PIN xa[256]
    DIRECTION OUTPUT ;
    USE SIGNAL ;
    PORT
      LAYER M5 ;
        RECT  84.816 30.156 84.84 30.24 ;
    END
  END xa[256]
  PIN xa[257]
    DIRECTION OUTPUT ;
    USE SIGNAL ;
    PORT
      LAYER M5 ;
        RECT  84.96 30.156 84.984 30.24 ;
    END
  END xa[257]
  PIN xa[258]
    DIRECTION OUTPUT ;
    USE SIGNAL ;
    PORT
      LAYER M5 ;
        RECT  85.104 30.156 85.128 30.24 ;
    END
  END xa[258]
  PIN xa[259]
    DIRECTION OUTPUT ;
    USE SIGNAL ;
    PORT
      LAYER M5 ;
        RECT  85.248 30.156 85.272 30.24 ;
    END
  END xa[259]
  PIN xa[25]
    DIRECTION OUTPUT ;
    USE SIGNAL ;
    PORT
      LAYER M5 ;
        RECT  51.552 30.156 51.576 30.24 ;
    END
  END xa[25]
  PIN xa[260]
    DIRECTION OUTPUT ;
    USE SIGNAL ;
    PORT
      LAYER M5 ;
        RECT  85.392 30.156 85.416 30.24 ;
    END
  END xa[260]
  PIN xa[261]
    DIRECTION OUTPUT ;
    USE SIGNAL ;
    PORT
      LAYER M5 ;
        RECT  85.536 30.156 85.56 30.24 ;
    END
  END xa[261]
  PIN xa[262]
    DIRECTION OUTPUT ;
    USE SIGNAL ;
    PORT
      LAYER M5 ;
        RECT  85.68 30.156 85.704 30.24 ;
    END
  END xa[262]
  PIN xa[263]
    DIRECTION OUTPUT ;
    USE SIGNAL ;
    PORT
      LAYER M5 ;
        RECT  85.824 30.156 85.848 30.24 ;
    END
  END xa[263]
  PIN xa[264]
    DIRECTION OUTPUT ;
    USE SIGNAL ;
    PORT
      LAYER M5 ;
        RECT  85.968 30.156 85.992 30.24 ;
    END
  END xa[264]
  PIN xa[265]
    DIRECTION OUTPUT ;
    USE SIGNAL ;
    PORT
      LAYER M5 ;
        RECT  86.112 30.156 86.136 30.24 ;
    END
  END xa[265]
  PIN xa[266]
    DIRECTION OUTPUT ;
    USE SIGNAL ;
    PORT
      LAYER M5 ;
        RECT  86.256 30.156 86.28 30.24 ;
    END
  END xa[266]
  PIN xa[267]
    DIRECTION OUTPUT ;
    USE SIGNAL ;
    PORT
      LAYER M5 ;
        RECT  86.4 30.156 86.424 30.24 ;
    END
  END xa[267]
  PIN xa[268]
    DIRECTION OUTPUT ;
    USE SIGNAL ;
    PORT
      LAYER M5 ;
        RECT  86.544 30.156 86.568 30.24 ;
    END
  END xa[268]
  PIN xa[269]
    DIRECTION OUTPUT ;
    USE SIGNAL ;
    PORT
      LAYER M5 ;
        RECT  86.688 30.156 86.712 30.24 ;
    END
  END xa[269]
  PIN xa[26]
    DIRECTION OUTPUT ;
    USE SIGNAL ;
    PORT
      LAYER M5 ;
        RECT  51.696 30.156 51.72 30.24 ;
    END
  END xa[26]
  PIN xa[270]
    DIRECTION OUTPUT ;
    USE SIGNAL ;
    PORT
      LAYER M5 ;
        RECT  86.832 30.156 86.856 30.24 ;
    END
  END xa[270]
  PIN xa[271]
    DIRECTION OUTPUT ;
    USE SIGNAL ;
    PORT
      LAYER M5 ;
        RECT  86.976 30.156 87 30.24 ;
    END
  END xa[271]
  PIN xa[272]
    DIRECTION OUTPUT ;
    USE SIGNAL ;
    PORT
      LAYER M5 ;
        RECT  87.12 30.156 87.144 30.24 ;
    END
  END xa[272]
  PIN xa[273]
    DIRECTION OUTPUT ;
    USE SIGNAL ;
    PORT
      LAYER M5 ;
        RECT  87.264 30.156 87.288 30.24 ;
    END
  END xa[273]
  PIN xa[274]
    DIRECTION OUTPUT ;
    USE SIGNAL ;
    PORT
      LAYER M5 ;
        RECT  87.408 30.156 87.432 30.24 ;
    END
  END xa[274]
  PIN xa[275]
    DIRECTION OUTPUT ;
    USE SIGNAL ;
    PORT
      LAYER M5 ;
        RECT  87.552 30.156 87.576 30.24 ;
    END
  END xa[275]
  PIN xa[276]
    DIRECTION OUTPUT ;
    USE SIGNAL ;
    PORT
      LAYER M5 ;
        RECT  87.696 30.156 87.72 30.24 ;
    END
  END xa[276]
  PIN xa[277]
    DIRECTION OUTPUT ;
    USE SIGNAL ;
    PORT
      LAYER M5 ;
        RECT  87.84 30.156 87.864 30.24 ;
    END
  END xa[277]
  PIN xa[278]
    DIRECTION OUTPUT ;
    USE SIGNAL ;
    PORT
      LAYER M5 ;
        RECT  87.984 30.156 88.008 30.24 ;
    END
  END xa[278]
  PIN xa[279]
    DIRECTION OUTPUT ;
    USE SIGNAL ;
    PORT
      LAYER M5 ;
        RECT  88.128 30.156 88.152 30.24 ;
    END
  END xa[279]
  PIN xa[27]
    DIRECTION OUTPUT ;
    USE SIGNAL ;
    PORT
      LAYER M5 ;
        RECT  51.84 30.156 51.864 30.24 ;
    END
  END xa[27]
  PIN xa[280]
    DIRECTION OUTPUT ;
    USE SIGNAL ;
    PORT
      LAYER M5 ;
        RECT  88.272 30.156 88.296 30.24 ;
    END
  END xa[280]
  PIN xa[281]
    DIRECTION OUTPUT ;
    USE SIGNAL ;
    PORT
      LAYER M5 ;
        RECT  88.416 30.156 88.44 30.24 ;
    END
  END xa[281]
  PIN xa[282]
    DIRECTION OUTPUT ;
    USE SIGNAL ;
    PORT
      LAYER M5 ;
        RECT  88.56 30.156 88.584 30.24 ;
    END
  END xa[282]
  PIN xa[28]
    DIRECTION OUTPUT ;
    USE SIGNAL ;
    PORT
      LAYER M5 ;
        RECT  51.984 30.156 52.008 30.24 ;
    END
  END xa[28]
  PIN xa[29]
    DIRECTION OUTPUT ;
    USE SIGNAL ;
    PORT
      LAYER M5 ;
        RECT  52.128 30.156 52.152 30.24 ;
    END
  END xa[29]
  PIN xa[2]
    DIRECTION OUTPUT ;
    USE SIGNAL ;
    PORT
      LAYER M5 ;
        RECT  48.24 30.156 48.264 30.24 ;
    END
  END xa[2]
  PIN xa[30]
    DIRECTION OUTPUT ;
    USE SIGNAL ;
    PORT
      LAYER M5 ;
        RECT  52.272 30.156 52.296 30.24 ;
    END
  END xa[30]
  PIN xa[31]
    DIRECTION OUTPUT ;
    USE SIGNAL ;
    PORT
      LAYER M5 ;
        RECT  52.416 30.156 52.44 30.24 ;
    END
  END xa[31]
  PIN xa[32]
    DIRECTION OUTPUT ;
    USE SIGNAL ;
    PORT
      LAYER M5 ;
        RECT  52.56 30.156 52.584 30.24 ;
    END
  END xa[32]
  PIN xa[33]
    DIRECTION OUTPUT ;
    USE SIGNAL ;
    PORT
      LAYER M5 ;
        RECT  52.704 30.156 52.728 30.24 ;
    END
  END xa[33]
  PIN xa[34]
    DIRECTION OUTPUT ;
    USE SIGNAL ;
    PORT
      LAYER M5 ;
        RECT  52.848 30.156 52.872 30.24 ;
    END
  END xa[34]
  PIN xa[35]
    DIRECTION OUTPUT ;
    USE SIGNAL ;
    PORT
      LAYER M5 ;
        RECT  52.992 30.156 53.016 30.24 ;
    END
  END xa[35]
  PIN xa[36]
    DIRECTION OUTPUT ;
    USE SIGNAL ;
    PORT
      LAYER M5 ;
        RECT  53.136 30.156 53.16 30.24 ;
    END
  END xa[36]
  PIN xa[37]
    DIRECTION OUTPUT ;
    USE SIGNAL ;
    PORT
      LAYER M5 ;
        RECT  53.28 30.156 53.304 30.24 ;
    END
  END xa[37]
  PIN xa[38]
    DIRECTION OUTPUT ;
    USE SIGNAL ;
    PORT
      LAYER M5 ;
        RECT  53.424 30.156 53.448 30.24 ;
    END
  END xa[38]
  PIN xa[39]
    DIRECTION OUTPUT ;
    USE SIGNAL ;
    PORT
      LAYER M5 ;
        RECT  53.568 30.156 53.592 30.24 ;
    END
  END xa[39]
  PIN xa[3]
    DIRECTION OUTPUT ;
    USE SIGNAL ;
    PORT
      LAYER M5 ;
        RECT  48.384 30.156 48.408 30.24 ;
    END
  END xa[3]
  PIN xa[40]
    DIRECTION OUTPUT ;
    USE SIGNAL ;
    PORT
      LAYER M5 ;
        RECT  53.712 30.156 53.736 30.24 ;
    END
  END xa[40]
  PIN xa[41]
    DIRECTION OUTPUT ;
    USE SIGNAL ;
    PORT
      LAYER M5 ;
        RECT  53.856 30.156 53.88 30.24 ;
    END
  END xa[41]
  PIN xa[42]
    DIRECTION OUTPUT ;
    USE SIGNAL ;
    PORT
      LAYER M5 ;
        RECT  54 30.156 54.024 30.24 ;
    END
  END xa[42]
  PIN xa[43]
    DIRECTION OUTPUT ;
    USE SIGNAL ;
    PORT
      LAYER M5 ;
        RECT  54.144 30.156 54.168 30.24 ;
    END
  END xa[43]
  PIN xa[44]
    DIRECTION OUTPUT ;
    USE SIGNAL ;
    PORT
      LAYER M5 ;
        RECT  54.288 30.156 54.312 30.24 ;
    END
  END xa[44]
  PIN xa[45]
    DIRECTION OUTPUT ;
    USE SIGNAL ;
    PORT
      LAYER M5 ;
        RECT  54.432 30.156 54.456 30.24 ;
    END
  END xa[45]
  PIN xa[46]
    DIRECTION OUTPUT ;
    USE SIGNAL ;
    PORT
      LAYER M5 ;
        RECT  54.576 30.156 54.6 30.24 ;
    END
  END xa[46]
  PIN xa[47]
    DIRECTION OUTPUT ;
    USE SIGNAL ;
    PORT
      LAYER M5 ;
        RECT  54.72 30.156 54.744 30.24 ;
    END
  END xa[47]
  PIN xa[48]
    DIRECTION OUTPUT ;
    USE SIGNAL ;
    PORT
      LAYER M5 ;
        RECT  54.864 30.156 54.888 30.24 ;
    END
  END xa[48]
  PIN xa[49]
    DIRECTION OUTPUT ;
    USE SIGNAL ;
    PORT
      LAYER M5 ;
        RECT  55.008 30.156 55.032 30.24 ;
    END
  END xa[49]
  PIN xa[4]
    DIRECTION OUTPUT ;
    USE SIGNAL ;
    PORT
      LAYER M5 ;
        RECT  48.528 30.156 48.552 30.24 ;
    END
  END xa[4]
  PIN xa[50]
    DIRECTION OUTPUT ;
    USE SIGNAL ;
    PORT
      LAYER M5 ;
        RECT  55.152 30.156 55.176 30.24 ;
    END
  END xa[50]
  PIN xa[51]
    DIRECTION OUTPUT ;
    USE SIGNAL ;
    PORT
      LAYER M5 ;
        RECT  55.296 30.156 55.32 30.24 ;
    END
  END xa[51]
  PIN xa[52]
    DIRECTION OUTPUT ;
    USE SIGNAL ;
    PORT
      LAYER M5 ;
        RECT  55.44 30.156 55.464 30.24 ;
    END
  END xa[52]
  PIN xa[53]
    DIRECTION OUTPUT ;
    USE SIGNAL ;
    PORT
      LAYER M5 ;
        RECT  55.584 30.156 55.608 30.24 ;
    END
  END xa[53]
  PIN xa[54]
    DIRECTION OUTPUT ;
    USE SIGNAL ;
    PORT
      LAYER M5 ;
        RECT  55.728 30.156 55.752 30.24 ;
    END
  END xa[54]
  PIN xa[55]
    DIRECTION OUTPUT ;
    USE SIGNAL ;
    PORT
      LAYER M5 ;
        RECT  55.872 30.156 55.896 30.24 ;
    END
  END xa[55]
  PIN xa[56]
    DIRECTION OUTPUT ;
    USE SIGNAL ;
    PORT
      LAYER M5 ;
        RECT  56.016 30.156 56.04 30.24 ;
    END
  END xa[56]
  PIN xa[57]
    DIRECTION OUTPUT ;
    USE SIGNAL ;
    PORT
      LAYER M5 ;
        RECT  56.16 30.156 56.184 30.24 ;
    END
  END xa[57]
  PIN xa[58]
    DIRECTION OUTPUT ;
    USE SIGNAL ;
    PORT
      LAYER M5 ;
        RECT  56.304 30.156 56.328 30.24 ;
    END
  END xa[58]
  PIN xa[59]
    DIRECTION OUTPUT ;
    USE SIGNAL ;
    PORT
      LAYER M5 ;
        RECT  56.448 30.156 56.472 30.24 ;
    END
  END xa[59]
  PIN xa[5]
    DIRECTION OUTPUT ;
    USE SIGNAL ;
    PORT
      LAYER M5 ;
        RECT  48.672 30.156 48.696 30.24 ;
    END
  END xa[5]
  PIN xa[60]
    DIRECTION OUTPUT ;
    USE SIGNAL ;
    PORT
      LAYER M5 ;
        RECT  56.592 30.156 56.616 30.24 ;
    END
  END xa[60]
  PIN xa[61]
    DIRECTION OUTPUT ;
    USE SIGNAL ;
    PORT
      LAYER M5 ;
        RECT  56.736 30.156 56.76 30.24 ;
    END
  END xa[61]
  PIN xa[62]
    DIRECTION OUTPUT ;
    USE SIGNAL ;
    PORT
      LAYER M5 ;
        RECT  56.88 30.156 56.904 30.24 ;
    END
  END xa[62]
  PIN xa[63]
    DIRECTION OUTPUT ;
    USE SIGNAL ;
    PORT
      LAYER M5 ;
        RECT  57.024 30.156 57.048 30.24 ;
    END
  END xa[63]
  PIN xa[64]
    DIRECTION OUTPUT ;
    USE SIGNAL ;
    PORT
      LAYER M5 ;
        RECT  57.168 30.156 57.192 30.24 ;
    END
  END xa[64]
  PIN xa[65]
    DIRECTION OUTPUT ;
    USE SIGNAL ;
    PORT
      LAYER M5 ;
        RECT  57.312 30.156 57.336 30.24 ;
    END
  END xa[65]
  PIN xa[66]
    DIRECTION OUTPUT ;
    USE SIGNAL ;
    PORT
      LAYER M5 ;
        RECT  57.456 30.156 57.48 30.24 ;
    END
  END xa[66]
  PIN xa[67]
    DIRECTION OUTPUT ;
    USE SIGNAL ;
    PORT
      LAYER M5 ;
        RECT  57.6 30.156 57.624 30.24 ;
    END
  END xa[67]
  PIN xa[68]
    DIRECTION OUTPUT ;
    USE SIGNAL ;
    PORT
      LAYER M5 ;
        RECT  57.744 30.156 57.768 30.24 ;
    END
  END xa[68]
  PIN xa[69]
    DIRECTION OUTPUT ;
    USE SIGNAL ;
    PORT
      LAYER M5 ;
        RECT  57.888 30.156 57.912 30.24 ;
    END
  END xa[69]
  PIN xa[6]
    DIRECTION OUTPUT ;
    USE SIGNAL ;
    PORT
      LAYER M5 ;
        RECT  48.816 30.156 48.84 30.24 ;
    END
  END xa[6]
  PIN xa[70]
    DIRECTION OUTPUT ;
    USE SIGNAL ;
    PORT
      LAYER M5 ;
        RECT  58.032 30.156 58.056 30.24 ;
    END
  END xa[70]
  PIN xa[71]
    DIRECTION OUTPUT ;
    USE SIGNAL ;
    PORT
      LAYER M5 ;
        RECT  58.176 30.156 58.2 30.24 ;
    END
  END xa[71]
  PIN xa[72]
    DIRECTION OUTPUT ;
    USE SIGNAL ;
    PORT
      LAYER M5 ;
        RECT  58.32 30.156 58.344 30.24 ;
    END
  END xa[72]
  PIN xa[73]
    DIRECTION OUTPUT ;
    USE SIGNAL ;
    PORT
      LAYER M5 ;
        RECT  58.464 30.156 58.488 30.24 ;
    END
  END xa[73]
  PIN xa[74]
    DIRECTION OUTPUT ;
    USE SIGNAL ;
    PORT
      LAYER M5 ;
        RECT  58.608 30.156 58.632 30.24 ;
    END
  END xa[74]
  PIN xa[75]
    DIRECTION OUTPUT ;
    USE SIGNAL ;
    PORT
      LAYER M5 ;
        RECT  58.752 30.156 58.776 30.24 ;
    END
  END xa[75]
  PIN xa[76]
    DIRECTION OUTPUT ;
    USE SIGNAL ;
    PORT
      LAYER M5 ;
        RECT  58.896 30.156 58.92 30.24 ;
    END
  END xa[76]
  PIN xa[77]
    DIRECTION OUTPUT ;
    USE SIGNAL ;
    PORT
      LAYER M5 ;
        RECT  59.04 30.156 59.064 30.24 ;
    END
  END xa[77]
  PIN xa[78]
    DIRECTION OUTPUT ;
    USE SIGNAL ;
    PORT
      LAYER M5 ;
        RECT  59.184 30.156 59.208 30.24 ;
    END
  END xa[78]
  PIN xa[79]
    DIRECTION OUTPUT ;
    USE SIGNAL ;
    PORT
      LAYER M5 ;
        RECT  59.328 30.156 59.352 30.24 ;
    END
  END xa[79]
  PIN xa[7]
    DIRECTION OUTPUT ;
    USE SIGNAL ;
    PORT
      LAYER M5 ;
        RECT  48.96 30.156 48.984 30.24 ;
    END
  END xa[7]
  PIN xa[80]
    DIRECTION OUTPUT ;
    USE SIGNAL ;
    PORT
      LAYER M5 ;
        RECT  59.472 30.156 59.496 30.24 ;
    END
  END xa[80]
  PIN xa[81]
    DIRECTION OUTPUT ;
    USE SIGNAL ;
    PORT
      LAYER M5 ;
        RECT  59.616 30.156 59.64 30.24 ;
    END
  END xa[81]
  PIN xa[82]
    DIRECTION OUTPUT ;
    USE SIGNAL ;
    PORT
      LAYER M5 ;
        RECT  59.76 30.156 59.784 30.24 ;
    END
  END xa[82]
  PIN xa[83]
    DIRECTION OUTPUT ;
    USE SIGNAL ;
    PORT
      LAYER M5 ;
        RECT  59.904 30.156 59.928 30.24 ;
    END
  END xa[83]
  PIN xa[84]
    DIRECTION OUTPUT ;
    USE SIGNAL ;
    PORT
      LAYER M5 ;
        RECT  60.048 30.156 60.072 30.24 ;
    END
  END xa[84]
  PIN xa[85]
    DIRECTION OUTPUT ;
    USE SIGNAL ;
    PORT
      LAYER M5 ;
        RECT  60.192 30.156 60.216 30.24 ;
    END
  END xa[85]
  PIN xa[86]
    DIRECTION OUTPUT ;
    USE SIGNAL ;
    PORT
      LAYER M5 ;
        RECT  60.336 30.156 60.36 30.24 ;
    END
  END xa[86]
  PIN xa[87]
    DIRECTION OUTPUT ;
    USE SIGNAL ;
    PORT
      LAYER M5 ;
        RECT  60.48 30.156 60.504 30.24 ;
    END
  END xa[87]
  PIN xa[88]
    DIRECTION OUTPUT ;
    USE SIGNAL ;
    PORT
      LAYER M5 ;
        RECT  60.624 30.156 60.648 30.24 ;
    END
  END xa[88]
  PIN xa[89]
    DIRECTION OUTPUT ;
    USE SIGNAL ;
    PORT
      LAYER M5 ;
        RECT  60.768 30.156 60.792 30.24 ;
    END
  END xa[89]
  PIN xa[8]
    DIRECTION OUTPUT ;
    USE SIGNAL ;
    PORT
      LAYER M5 ;
        RECT  49.104 30.156 49.128 30.24 ;
    END
  END xa[8]
  PIN xa[90]
    DIRECTION OUTPUT ;
    USE SIGNAL ;
    PORT
      LAYER M5 ;
        RECT  60.912 30.156 60.936 30.24 ;
    END
  END xa[90]
  PIN xa[91]
    DIRECTION OUTPUT ;
    USE SIGNAL ;
    PORT
      LAYER M5 ;
        RECT  61.056 30.156 61.08 30.24 ;
    END
  END xa[91]
  PIN xa[92]
    DIRECTION OUTPUT ;
    USE SIGNAL ;
    PORT
      LAYER M5 ;
        RECT  61.2 30.156 61.224 30.24 ;
    END
  END xa[92]
  PIN xa[93]
    DIRECTION OUTPUT ;
    USE SIGNAL ;
    PORT
      LAYER M5 ;
        RECT  61.344 30.156 61.368 30.24 ;
    END
  END xa[93]
  PIN xa[94]
    DIRECTION OUTPUT ;
    USE SIGNAL ;
    PORT
      LAYER M5 ;
        RECT  61.488 30.156 61.512 30.24 ;
    END
  END xa[94]
  PIN xa[95]
    DIRECTION OUTPUT ;
    USE SIGNAL ;
    PORT
      LAYER M5 ;
        RECT  61.632 30.156 61.656 30.24 ;
    END
  END xa[95]
  PIN xa[96]
    DIRECTION OUTPUT ;
    USE SIGNAL ;
    PORT
      LAYER M5 ;
        RECT  61.776 30.156 61.8 30.24 ;
    END
  END xa[96]
  PIN xa[97]
    DIRECTION OUTPUT ;
    USE SIGNAL ;
    PORT
      LAYER M5 ;
        RECT  61.92 30.156 61.944 30.24 ;
    END
  END xa[97]
  PIN xa[98]
    DIRECTION OUTPUT ;
    USE SIGNAL ;
    PORT
      LAYER M5 ;
        RECT  62.064 30.156 62.088 30.24 ;
    END
  END xa[98]
  PIN xa[99]
    DIRECTION OUTPUT ;
    USE SIGNAL ;
    PORT
      LAYER M5 ;
        RECT  62.208 30.156 62.232 30.24 ;
    END
  END xa[99]
  PIN xa[9]
    DIRECTION OUTPUT ;
    USE SIGNAL ;
    PORT
      LAYER M5 ;
        RECT  49.248 30.156 49.272 30.24 ;
    END
  END xa[9]
  PIN xai[0]
    DIRECTION INPUT ;
    USE SIGNAL ;
    PORT
      LAYER M5 ;
        RECT  131.424 0 131.448 0.084 ;
    END
  END xai[0]
  PIN xai[100]
    DIRECTION INPUT ;
    USE SIGNAL ;
    PORT
      LAYER M5 ;
        RECT  145.824 0 145.848 0.084 ;
    END
  END xai[100]
  PIN xai[101]
    DIRECTION INPUT ;
    USE SIGNAL ;
    PORT
      LAYER M5 ;
        RECT  145.968 0 145.992 0.084 ;
    END
  END xai[101]
  PIN xai[102]
    DIRECTION INPUT ;
    USE SIGNAL ;
    PORT
      LAYER M5 ;
        RECT  146.112 0 146.136 0.084 ;
    END
  END xai[102]
  PIN xai[103]
    DIRECTION INPUT ;
    USE SIGNAL ;
    PORT
      LAYER M5 ;
        RECT  146.256 0 146.28 0.084 ;
    END
  END xai[103]
  PIN xai[104]
    DIRECTION INPUT ;
    USE SIGNAL ;
    PORT
      LAYER M5 ;
        RECT  146.4 0 146.424 0.084 ;
    END
  END xai[104]
  PIN xai[105]
    DIRECTION INPUT ;
    USE SIGNAL ;
    PORT
      LAYER M5 ;
        RECT  146.544 0 146.568 0.084 ;
    END
  END xai[105]
  PIN xai[106]
    DIRECTION INPUT ;
    USE SIGNAL ;
    PORT
      LAYER M5 ;
        RECT  146.688 0 146.712 0.084 ;
    END
  END xai[106]
  PIN xai[107]
    DIRECTION INPUT ;
    USE SIGNAL ;
    PORT
      LAYER M5 ;
        RECT  146.832 0 146.856 0.084 ;
    END
  END xai[107]
  PIN xai[108]
    DIRECTION INPUT ;
    USE SIGNAL ;
    PORT
      LAYER M5 ;
        RECT  146.976 0 147 0.084 ;
    END
  END xai[108]
  PIN xai[109]
    DIRECTION INPUT ;
    USE SIGNAL ;
    PORT
      LAYER M5 ;
        RECT  147.12 0 147.144 0.084 ;
    END
  END xai[109]
  PIN xai[10]
    DIRECTION INPUT ;
    USE SIGNAL ;
    PORT
      LAYER M5 ;
        RECT  132.864 0 132.888 0.084 ;
    END
  END xai[10]
  PIN xai[110]
    DIRECTION INPUT ;
    USE SIGNAL ;
    PORT
      LAYER M5 ;
        RECT  147.264 0 147.288 0.084 ;
    END
  END xai[110]
  PIN xai[111]
    DIRECTION INPUT ;
    USE SIGNAL ;
    PORT
      LAYER M5 ;
        RECT  147.408 0 147.432 0.084 ;
    END
  END xai[111]
  PIN xai[112]
    DIRECTION INPUT ;
    USE SIGNAL ;
    PORT
      LAYER M5 ;
        RECT  147.552 0 147.576 0.084 ;
    END
  END xai[112]
  PIN xai[113]
    DIRECTION INPUT ;
    USE SIGNAL ;
    PORT
      LAYER M5 ;
        RECT  147.696 0 147.72 0.084 ;
    END
  END xai[113]
  PIN xai[114]
    DIRECTION INPUT ;
    USE SIGNAL ;
    PORT
      LAYER M5 ;
        RECT  147.84 0 147.864 0.084 ;
    END
  END xai[114]
  PIN xai[115]
    DIRECTION INPUT ;
    USE SIGNAL ;
    PORT
      LAYER M5 ;
        RECT  147.984 0 148.008 0.084 ;
    END
  END xai[115]
  PIN xai[116]
    DIRECTION INPUT ;
    USE SIGNAL ;
    PORT
      LAYER M5 ;
        RECT  148.128 0 148.152 0.084 ;
    END
  END xai[116]
  PIN xai[117]
    DIRECTION INPUT ;
    USE SIGNAL ;
    PORT
      LAYER M5 ;
        RECT  148.272 0 148.296 0.084 ;
    END
  END xai[117]
  PIN xai[118]
    DIRECTION INPUT ;
    USE SIGNAL ;
    PORT
      LAYER M5 ;
        RECT  148.416 0 148.44 0.084 ;
    END
  END xai[118]
  PIN xai[119]
    DIRECTION INPUT ;
    USE SIGNAL ;
    PORT
      LAYER M5 ;
        RECT  148.56 0 148.584 0.084 ;
    END
  END xai[119]
  PIN xai[11]
    DIRECTION INPUT ;
    USE SIGNAL ;
    PORT
      LAYER M5 ;
        RECT  133.008 0 133.032 0.084 ;
    END
  END xai[11]
  PIN xai[120]
    DIRECTION INPUT ;
    USE SIGNAL ;
    PORT
      LAYER M5 ;
        RECT  148.704 0 148.728 0.084 ;
    END
  END xai[120]
  PIN xai[121]
    DIRECTION INPUT ;
    USE SIGNAL ;
    PORT
      LAYER M5 ;
        RECT  148.848 0 148.872 0.084 ;
    END
  END xai[121]
  PIN xai[122]
    DIRECTION INPUT ;
    USE SIGNAL ;
    PORT
      LAYER M5 ;
        RECT  148.992 0 149.016 0.084 ;
    END
  END xai[122]
  PIN xai[123]
    DIRECTION INPUT ;
    USE SIGNAL ;
    PORT
      LAYER M5 ;
        RECT  149.136 0 149.16 0.084 ;
    END
  END xai[123]
  PIN xai[124]
    DIRECTION INPUT ;
    USE SIGNAL ;
    PORT
      LAYER M5 ;
        RECT  149.28 0 149.304 0.084 ;
    END
  END xai[124]
  PIN xai[125]
    DIRECTION INPUT ;
    USE SIGNAL ;
    PORT
      LAYER M5 ;
        RECT  149.424 0 149.448 0.084 ;
    END
  END xai[125]
  PIN xai[126]
    DIRECTION INPUT ;
    USE SIGNAL ;
    PORT
      LAYER M5 ;
        RECT  149.568 0 149.592 0.084 ;
    END
  END xai[126]
  PIN xai[127]
    DIRECTION INPUT ;
    USE SIGNAL ;
    PORT
      LAYER M5 ;
        RECT  149.712 0 149.736 0.084 ;
    END
  END xai[127]
  PIN xai[128]
    DIRECTION INPUT ;
    USE SIGNAL ;
    PORT
      LAYER M5 ;
        RECT  149.856 0 149.88 0.084 ;
    END
  END xai[128]
  PIN xai[129]
    DIRECTION INPUT ;
    USE SIGNAL ;
    PORT
      LAYER M5 ;
        RECT  150 0 150.024 0.084 ;
    END
  END xai[129]
  PIN xai[12]
    DIRECTION INPUT ;
    USE SIGNAL ;
    PORT
      LAYER M5 ;
        RECT  133.152 0 133.176 0.084 ;
    END
  END xai[12]
  PIN xai[130]
    DIRECTION INPUT ;
    USE SIGNAL ;
    PORT
      LAYER M5 ;
        RECT  150.144 0 150.168 0.084 ;
    END
  END xai[130]
  PIN xai[131]
    DIRECTION INPUT ;
    USE SIGNAL ;
    PORT
      LAYER M5 ;
        RECT  150.288 0 150.312 0.084 ;
    END
  END xai[131]
  PIN xai[132]
    DIRECTION INPUT ;
    USE SIGNAL ;
    PORT
      LAYER M5 ;
        RECT  150.432 0 150.456 0.084 ;
    END
  END xai[132]
  PIN xai[133]
    DIRECTION INPUT ;
    USE SIGNAL ;
    PORT
      LAYER M5 ;
        RECT  150.576 0 150.6 0.084 ;
    END
  END xai[133]
  PIN xai[134]
    DIRECTION INPUT ;
    USE SIGNAL ;
    PORT
      LAYER M5 ;
        RECT  150.72 0 150.744 0.084 ;
    END
  END xai[134]
  PIN xai[135]
    DIRECTION INPUT ;
    USE SIGNAL ;
    PORT
      LAYER M5 ;
        RECT  150.864 0 150.888 0.084 ;
    END
  END xai[135]
  PIN xai[136]
    DIRECTION INPUT ;
    USE SIGNAL ;
    PORT
      LAYER M5 ;
        RECT  151.008 0 151.032 0.084 ;
    END
  END xai[136]
  PIN xai[137]
    DIRECTION INPUT ;
    USE SIGNAL ;
    PORT
      LAYER M5 ;
        RECT  151.152 0 151.176 0.084 ;
    END
  END xai[137]
  PIN xai[138]
    DIRECTION INPUT ;
    USE SIGNAL ;
    PORT
      LAYER M5 ;
        RECT  151.296 0 151.32 0.084 ;
    END
  END xai[138]
  PIN xai[139]
    DIRECTION INPUT ;
    USE SIGNAL ;
    PORT
      LAYER M5 ;
        RECT  151.44 0 151.464 0.084 ;
    END
  END xai[139]
  PIN xai[13]
    DIRECTION INPUT ;
    USE SIGNAL ;
    PORT
      LAYER M5 ;
        RECT  133.296 0 133.32 0.084 ;
    END
  END xai[13]
  PIN xai[140]
    DIRECTION INPUT ;
    USE SIGNAL ;
    PORT
      LAYER M5 ;
        RECT  151.584 0 151.608 0.084 ;
    END
  END xai[140]
  PIN xai[141]
    DIRECTION INPUT ;
    USE SIGNAL ;
    PORT
      LAYER M5 ;
        RECT  151.728 0 151.752 0.084 ;
    END
  END xai[141]
  PIN xai[142]
    DIRECTION INPUT ;
    USE SIGNAL ;
    PORT
      LAYER M5 ;
        RECT  151.872 0 151.896 0.084 ;
    END
  END xai[142]
  PIN xai[143]
    DIRECTION INPUT ;
    USE SIGNAL ;
    PORT
      LAYER M5 ;
        RECT  152.016 0 152.04 0.084 ;
    END
  END xai[143]
  PIN xai[144]
    DIRECTION INPUT ;
    USE SIGNAL ;
    PORT
      LAYER M5 ;
        RECT  152.16 0 152.184 0.084 ;
    END
  END xai[144]
  PIN xai[145]
    DIRECTION INPUT ;
    USE SIGNAL ;
    PORT
      LAYER M5 ;
        RECT  152.304 0 152.328 0.084 ;
    END
  END xai[145]
  PIN xai[146]
    DIRECTION INPUT ;
    USE SIGNAL ;
    PORT
      LAYER M5 ;
        RECT  152.448 0 152.472 0.084 ;
    END
  END xai[146]
  PIN xai[147]
    DIRECTION INPUT ;
    USE SIGNAL ;
    PORT
      LAYER M5 ;
        RECT  152.592 0 152.616 0.084 ;
    END
  END xai[147]
  PIN xai[148]
    DIRECTION INPUT ;
    USE SIGNAL ;
    PORT
      LAYER M5 ;
        RECT  152.736 0 152.76 0.084 ;
    END
  END xai[148]
  PIN xai[149]
    DIRECTION INPUT ;
    USE SIGNAL ;
    PORT
      LAYER M5 ;
        RECT  152.88 0 152.904 0.084 ;
    END
  END xai[149]
  PIN xai[14]
    DIRECTION INPUT ;
    USE SIGNAL ;
    PORT
      LAYER M5 ;
        RECT  133.44 0 133.464 0.084 ;
    END
  END xai[14]
  PIN xai[150]
    DIRECTION INPUT ;
    USE SIGNAL ;
    PORT
      LAYER M5 ;
        RECT  153.024 0 153.048 0.084 ;
    END
  END xai[150]
  PIN xai[151]
    DIRECTION INPUT ;
    USE SIGNAL ;
    PORT
      LAYER M5 ;
        RECT  153.168 0 153.192 0.084 ;
    END
  END xai[151]
  PIN xai[152]
    DIRECTION INPUT ;
    USE SIGNAL ;
    PORT
      LAYER M5 ;
        RECT  153.312 0 153.336 0.084 ;
    END
  END xai[152]
  PIN xai[153]
    DIRECTION INPUT ;
    USE SIGNAL ;
    PORT
      LAYER M5 ;
        RECT  153.456 0 153.48 0.084 ;
    END
  END xai[153]
  PIN xai[154]
    DIRECTION INPUT ;
    USE SIGNAL ;
    PORT
      LAYER M5 ;
        RECT  153.6 0 153.624 0.084 ;
    END
  END xai[154]
  PIN xai[155]
    DIRECTION INPUT ;
    USE SIGNAL ;
    PORT
      LAYER M5 ;
        RECT  153.744 0 153.768 0.084 ;
    END
  END xai[155]
  PIN xai[156]
    DIRECTION INPUT ;
    USE SIGNAL ;
    PORT
      LAYER M5 ;
        RECT  153.888 0 153.912 0.084 ;
    END
  END xai[156]
  PIN xai[157]
    DIRECTION INPUT ;
    USE SIGNAL ;
    PORT
      LAYER M5 ;
        RECT  154.032 0 154.056 0.084 ;
    END
  END xai[157]
  PIN xai[158]
    DIRECTION INPUT ;
    USE SIGNAL ;
    PORT
      LAYER M5 ;
        RECT  154.176 0 154.2 0.084 ;
    END
  END xai[158]
  PIN xai[159]
    DIRECTION INPUT ;
    USE SIGNAL ;
    PORT
      LAYER M5 ;
        RECT  154.32 0 154.344 0.084 ;
    END
  END xai[159]
  PIN xai[15]
    DIRECTION INPUT ;
    USE SIGNAL ;
    PORT
      LAYER M5 ;
        RECT  133.584 0 133.608 0.084 ;
    END
  END xai[15]
  PIN xai[160]
    DIRECTION INPUT ;
    USE SIGNAL ;
    PORT
      LAYER M5 ;
        RECT  154.464 0 154.488 0.084 ;
    END
  END xai[160]
  PIN xai[161]
    DIRECTION INPUT ;
    USE SIGNAL ;
    PORT
      LAYER M5 ;
        RECT  154.608 0 154.632 0.084 ;
    END
  END xai[161]
  PIN xai[162]
    DIRECTION INPUT ;
    USE SIGNAL ;
    PORT
      LAYER M5 ;
        RECT  154.752 0 154.776 0.084 ;
    END
  END xai[162]
  PIN xai[163]
    DIRECTION INPUT ;
    USE SIGNAL ;
    PORT
      LAYER M5 ;
        RECT  154.896 0 154.92 0.084 ;
    END
  END xai[163]
  PIN xai[164]
    DIRECTION INPUT ;
    USE SIGNAL ;
    PORT
      LAYER M5 ;
        RECT  155.04 0 155.064 0.084 ;
    END
  END xai[164]
  PIN xai[165]
    DIRECTION INPUT ;
    USE SIGNAL ;
    PORT
      LAYER M5 ;
        RECT  155.184 0 155.208 0.084 ;
    END
  END xai[165]
  PIN xai[166]
    DIRECTION INPUT ;
    USE SIGNAL ;
    PORT
      LAYER M5 ;
        RECT  155.328 0 155.352 0.084 ;
    END
  END xai[166]
  PIN xai[167]
    DIRECTION INPUT ;
    USE SIGNAL ;
    PORT
      LAYER M5 ;
        RECT  155.472 0 155.496 0.084 ;
    END
  END xai[167]
  PIN xai[168]
    DIRECTION INPUT ;
    USE SIGNAL ;
    PORT
      LAYER M5 ;
        RECT  155.616 0 155.64 0.084 ;
    END
  END xai[168]
  PIN xai[169]
    DIRECTION INPUT ;
    USE SIGNAL ;
    PORT
      LAYER M5 ;
        RECT  155.76 0 155.784 0.084 ;
    END
  END xai[169]
  PIN xai[16]
    DIRECTION INPUT ;
    USE SIGNAL ;
    PORT
      LAYER M5 ;
        RECT  133.728 0 133.752 0.084 ;
    END
  END xai[16]
  PIN xai[170]
    DIRECTION INPUT ;
    USE SIGNAL ;
    PORT
      LAYER M5 ;
        RECT  155.904 0 155.928 0.084 ;
    END
  END xai[170]
  PIN xai[171]
    DIRECTION INPUT ;
    USE SIGNAL ;
    PORT
      LAYER M5 ;
        RECT  156.048 0 156.072 0.084 ;
    END
  END xai[171]
  PIN xai[172]
    DIRECTION INPUT ;
    USE SIGNAL ;
    PORT
      LAYER M5 ;
        RECT  156.192 0 156.216 0.084 ;
    END
  END xai[172]
  PIN xai[173]
    DIRECTION INPUT ;
    USE SIGNAL ;
    PORT
      LAYER M5 ;
        RECT  156.336 0 156.36 0.084 ;
    END
  END xai[173]
  PIN xai[174]
    DIRECTION INPUT ;
    USE SIGNAL ;
    PORT
      LAYER M5 ;
        RECT  156.48 0 156.504 0.084 ;
    END
  END xai[174]
  PIN xai[175]
    DIRECTION INPUT ;
    USE SIGNAL ;
    PORT
      LAYER M5 ;
        RECT  156.624 0 156.648 0.084 ;
    END
  END xai[175]
  PIN xai[176]
    DIRECTION INPUT ;
    USE SIGNAL ;
    PORT
      LAYER M5 ;
        RECT  156.768 0 156.792 0.084 ;
    END
  END xai[176]
  PIN xai[177]
    DIRECTION INPUT ;
    USE SIGNAL ;
    PORT
      LAYER M5 ;
        RECT  156.912 0 156.936 0.084 ;
    END
  END xai[177]
  PIN xai[178]
    DIRECTION INPUT ;
    USE SIGNAL ;
    PORT
      LAYER M5 ;
        RECT  157.056 0 157.08 0.084 ;
    END
  END xai[178]
  PIN xai[179]
    DIRECTION INPUT ;
    USE SIGNAL ;
    PORT
      LAYER M5 ;
        RECT  157.2 0 157.224 0.084 ;
    END
  END xai[179]
  PIN xai[17]
    DIRECTION INPUT ;
    USE SIGNAL ;
    PORT
      LAYER M5 ;
        RECT  133.872 0 133.896 0.084 ;
    END
  END xai[17]
  PIN xai[180]
    DIRECTION INPUT ;
    USE SIGNAL ;
    PORT
      LAYER M5 ;
        RECT  157.344 0 157.368 0.084 ;
    END
  END xai[180]
  PIN xai[181]
    DIRECTION INPUT ;
    USE SIGNAL ;
    PORT
      LAYER M5 ;
        RECT  157.488 0 157.512 0.084 ;
    END
  END xai[181]
  PIN xai[182]
    DIRECTION INPUT ;
    USE SIGNAL ;
    PORT
      LAYER M5 ;
        RECT  157.632 0 157.656 0.084 ;
    END
  END xai[182]
  PIN xai[183]
    DIRECTION INPUT ;
    USE SIGNAL ;
    PORT
      LAYER M5 ;
        RECT  157.776 0 157.8 0.084 ;
    END
  END xai[183]
  PIN xai[184]
    DIRECTION INPUT ;
    USE SIGNAL ;
    PORT
      LAYER M5 ;
        RECT  157.92 0 157.944 0.084 ;
    END
  END xai[184]
  PIN xai[185]
    DIRECTION INPUT ;
    USE SIGNAL ;
    PORT
      LAYER M5 ;
        RECT  158.064 0 158.088 0.084 ;
    END
  END xai[185]
  PIN xai[186]
    DIRECTION INPUT ;
    USE SIGNAL ;
    PORT
      LAYER M5 ;
        RECT  158.208 0 158.232 0.084 ;
    END
  END xai[186]
  PIN xai[187]
    DIRECTION INPUT ;
    USE SIGNAL ;
    PORT
      LAYER M5 ;
        RECT  158.352 0 158.376 0.084 ;
    END
  END xai[187]
  PIN xai[188]
    DIRECTION INPUT ;
    USE SIGNAL ;
    PORT
      LAYER M5 ;
        RECT  158.496 0 158.52 0.084 ;
    END
  END xai[188]
  PIN xai[189]
    DIRECTION INPUT ;
    USE SIGNAL ;
    PORT
      LAYER M5 ;
        RECT  158.64 0 158.664 0.084 ;
    END
  END xai[189]
  PIN xai[18]
    DIRECTION INPUT ;
    USE SIGNAL ;
    PORT
      LAYER M5 ;
        RECT  134.016 0 134.04 0.084 ;
    END
  END xai[18]
  PIN xai[190]
    DIRECTION INPUT ;
    USE SIGNAL ;
    PORT
      LAYER M5 ;
        RECT  158.784 0 158.808 0.084 ;
    END
  END xai[190]
  PIN xai[191]
    DIRECTION INPUT ;
    USE SIGNAL ;
    PORT
      LAYER M5 ;
        RECT  158.928 0 158.952 0.084 ;
    END
  END xai[191]
  PIN xai[192]
    DIRECTION INPUT ;
    USE SIGNAL ;
    PORT
      LAYER M5 ;
        RECT  159.072 0 159.096 0.084 ;
    END
  END xai[192]
  PIN xai[193]
    DIRECTION INPUT ;
    USE SIGNAL ;
    PORT
      LAYER M5 ;
        RECT  159.216 0 159.24 0.084 ;
    END
  END xai[193]
  PIN xai[194]
    DIRECTION INPUT ;
    USE SIGNAL ;
    PORT
      LAYER M5 ;
        RECT  159.36 0 159.384 0.084 ;
    END
  END xai[194]
  PIN xai[195]
    DIRECTION INPUT ;
    USE SIGNAL ;
    PORT
      LAYER M5 ;
        RECT  159.504 0 159.528 0.084 ;
    END
  END xai[195]
  PIN xai[196]
    DIRECTION INPUT ;
    USE SIGNAL ;
    PORT
      LAYER M5 ;
        RECT  159.648 0 159.672 0.084 ;
    END
  END xai[196]
  PIN xai[197]
    DIRECTION INPUT ;
    USE SIGNAL ;
    PORT
      LAYER M5 ;
        RECT  159.792 0 159.816 0.084 ;
    END
  END xai[197]
  PIN xai[198]
    DIRECTION INPUT ;
    USE SIGNAL ;
    PORT
      LAYER M5 ;
        RECT  159.936 0 159.96 0.084 ;
    END
  END xai[198]
  PIN xai[199]
    DIRECTION INPUT ;
    USE SIGNAL ;
    PORT
      LAYER M5 ;
        RECT  160.08 0 160.104 0.084 ;
    END
  END xai[199]
  PIN xai[19]
    DIRECTION INPUT ;
    USE SIGNAL ;
    PORT
      LAYER M5 ;
        RECT  134.16 0 134.184 0.084 ;
    END
  END xai[19]
  PIN xai[1]
    DIRECTION INPUT ;
    USE SIGNAL ;
    PORT
      LAYER M5 ;
        RECT  131.568 0 131.592 0.084 ;
    END
  END xai[1]
  PIN xai[200]
    DIRECTION INPUT ;
    USE SIGNAL ;
    PORT
      LAYER M5 ;
        RECT  160.224 0 160.248 0.084 ;
    END
  END xai[200]
  PIN xai[201]
    DIRECTION INPUT ;
    USE SIGNAL ;
    PORT
      LAYER M5 ;
        RECT  160.368 0 160.392 0.084 ;
    END
  END xai[201]
  PIN xai[202]
    DIRECTION INPUT ;
    USE SIGNAL ;
    PORT
      LAYER M5 ;
        RECT  160.512 0 160.536 0.084 ;
    END
  END xai[202]
  PIN xai[203]
    DIRECTION INPUT ;
    USE SIGNAL ;
    PORT
      LAYER M5 ;
        RECT  160.656 0 160.68 0.084 ;
    END
  END xai[203]
  PIN xai[204]
    DIRECTION INPUT ;
    USE SIGNAL ;
    PORT
      LAYER M5 ;
        RECT  160.8 0 160.824 0.084 ;
    END
  END xai[204]
  PIN xai[205]
    DIRECTION INPUT ;
    USE SIGNAL ;
    PORT
      LAYER M5 ;
        RECT  160.944 0 160.968 0.084 ;
    END
  END xai[205]
  PIN xai[206]
    DIRECTION INPUT ;
    USE SIGNAL ;
    PORT
      LAYER M5 ;
        RECT  161.088 0 161.112 0.084 ;
    END
  END xai[206]
  PIN xai[207]
    DIRECTION INPUT ;
    USE SIGNAL ;
    PORT
      LAYER M5 ;
        RECT  161.232 0 161.256 0.084 ;
    END
  END xai[207]
  PIN xai[208]
    DIRECTION INPUT ;
    USE SIGNAL ;
    PORT
      LAYER M5 ;
        RECT  161.376 0 161.4 0.084 ;
    END
  END xai[208]
  PIN xai[209]
    DIRECTION INPUT ;
    USE SIGNAL ;
    PORT
      LAYER M5 ;
        RECT  161.52 0 161.544 0.084 ;
    END
  END xai[209]
  PIN xai[20]
    DIRECTION INPUT ;
    USE SIGNAL ;
    PORT
      LAYER M5 ;
        RECT  134.304 0 134.328 0.084 ;
    END
  END xai[20]
  PIN xai[210]
    DIRECTION INPUT ;
    USE SIGNAL ;
    PORT
      LAYER M5 ;
        RECT  161.664 0 161.688 0.084 ;
    END
  END xai[210]
  PIN xai[211]
    DIRECTION INPUT ;
    USE SIGNAL ;
    PORT
      LAYER M5 ;
        RECT  161.808 0 161.832 0.084 ;
    END
  END xai[211]
  PIN xai[212]
    DIRECTION INPUT ;
    USE SIGNAL ;
    PORT
      LAYER M5 ;
        RECT  161.952 0 161.976 0.084 ;
    END
  END xai[212]
  PIN xai[213]
    DIRECTION INPUT ;
    USE SIGNAL ;
    PORT
      LAYER M5 ;
        RECT  162.096 0 162.12 0.084 ;
    END
  END xai[213]
  PIN xai[214]
    DIRECTION INPUT ;
    USE SIGNAL ;
    PORT
      LAYER M5 ;
        RECT  162.24 0 162.264 0.084 ;
    END
  END xai[214]
  PIN xai[215]
    DIRECTION INPUT ;
    USE SIGNAL ;
    PORT
      LAYER M5 ;
        RECT  162.384 0 162.408 0.084 ;
    END
  END xai[215]
  PIN xai[216]
    DIRECTION INPUT ;
    USE SIGNAL ;
    PORT
      LAYER M5 ;
        RECT  162.528 0 162.552 0.084 ;
    END
  END xai[216]
  PIN xai[217]
    DIRECTION INPUT ;
    USE SIGNAL ;
    PORT
      LAYER M5 ;
        RECT  162.672 0 162.696 0.084 ;
    END
  END xai[217]
  PIN xai[218]
    DIRECTION INPUT ;
    USE SIGNAL ;
    PORT
      LAYER M5 ;
        RECT  162.816 0 162.84 0.084 ;
    END
  END xai[218]
  PIN xai[219]
    DIRECTION INPUT ;
    USE SIGNAL ;
    PORT
      LAYER M5 ;
        RECT  162.96 0 162.984 0.084 ;
    END
  END xai[219]
  PIN xai[21]
    DIRECTION INPUT ;
    USE SIGNAL ;
    PORT
      LAYER M5 ;
        RECT  134.448 0 134.472 0.084 ;
    END
  END xai[21]
  PIN xai[220]
    DIRECTION INPUT ;
    USE SIGNAL ;
    PORT
      LAYER M5 ;
        RECT  163.104 0 163.128 0.084 ;
    END
  END xai[220]
  PIN xai[221]
    DIRECTION INPUT ;
    USE SIGNAL ;
    PORT
      LAYER M5 ;
        RECT  163.248 0 163.272 0.084 ;
    END
  END xai[221]
  PIN xai[222]
    DIRECTION INPUT ;
    USE SIGNAL ;
    PORT
      LAYER M5 ;
        RECT  163.392 0 163.416 0.084 ;
    END
  END xai[222]
  PIN xai[223]
    DIRECTION INPUT ;
    USE SIGNAL ;
    PORT
      LAYER M5 ;
        RECT  163.536 0 163.56 0.084 ;
    END
  END xai[223]
  PIN xai[224]
    DIRECTION INPUT ;
    USE SIGNAL ;
    PORT
      LAYER M5 ;
        RECT  163.68 0 163.704 0.084 ;
    END
  END xai[224]
  PIN xai[225]
    DIRECTION INPUT ;
    USE SIGNAL ;
    PORT
      LAYER M5 ;
        RECT  163.824 0 163.848 0.084 ;
    END
  END xai[225]
  PIN xai[226]
    DIRECTION INPUT ;
    USE SIGNAL ;
    PORT
      LAYER M5 ;
        RECT  163.968 0 163.992 0.084 ;
    END
  END xai[226]
  PIN xai[227]
    DIRECTION INPUT ;
    USE SIGNAL ;
    PORT
      LAYER M5 ;
        RECT  164.112 0 164.136 0.084 ;
    END
  END xai[227]
  PIN xai[228]
    DIRECTION INPUT ;
    USE SIGNAL ;
    PORT
      LAYER M5 ;
        RECT  164.256 0 164.28 0.084 ;
    END
  END xai[228]
  PIN xai[229]
    DIRECTION INPUT ;
    USE SIGNAL ;
    PORT
      LAYER M5 ;
        RECT  164.4 0 164.424 0.084 ;
    END
  END xai[229]
  PIN xai[22]
    DIRECTION INPUT ;
    USE SIGNAL ;
    PORT
      LAYER M5 ;
        RECT  134.592 0 134.616 0.084 ;
    END
  END xai[22]
  PIN xai[230]
    DIRECTION INPUT ;
    USE SIGNAL ;
    PORT
      LAYER M5 ;
        RECT  164.544 0 164.568 0.084 ;
    END
  END xai[230]
  PIN xai[231]
    DIRECTION INPUT ;
    USE SIGNAL ;
    PORT
      LAYER M5 ;
        RECT  164.688 0 164.712 0.084 ;
    END
  END xai[231]
  PIN xai[232]
    DIRECTION INPUT ;
    USE SIGNAL ;
    PORT
      LAYER M5 ;
        RECT  164.832 0 164.856 0.084 ;
    END
  END xai[232]
  PIN xai[233]
    DIRECTION INPUT ;
    USE SIGNAL ;
    PORT
      LAYER M5 ;
        RECT  164.976 0 165 0.084 ;
    END
  END xai[233]
  PIN xai[234]
    DIRECTION INPUT ;
    USE SIGNAL ;
    PORT
      LAYER M5 ;
        RECT  165.12 0 165.144 0.084 ;
    END
  END xai[234]
  PIN xai[235]
    DIRECTION INPUT ;
    USE SIGNAL ;
    PORT
      LAYER M5 ;
        RECT  165.264 0 165.288 0.084 ;
    END
  END xai[235]
  PIN xai[236]
    DIRECTION INPUT ;
    USE SIGNAL ;
    PORT
      LAYER M5 ;
        RECT  165.408 0 165.432 0.084 ;
    END
  END xai[236]
  PIN xai[237]
    DIRECTION INPUT ;
    USE SIGNAL ;
    PORT
      LAYER M5 ;
        RECT  165.552 0 165.576 0.084 ;
    END
  END xai[237]
  PIN xai[238]
    DIRECTION INPUT ;
    USE SIGNAL ;
    PORT
      LAYER M5 ;
        RECT  165.696 0 165.72 0.084 ;
    END
  END xai[238]
  PIN xai[239]
    DIRECTION INPUT ;
    USE SIGNAL ;
    PORT
      LAYER M5 ;
        RECT  165.84 0 165.864 0.084 ;
    END
  END xai[239]
  PIN xai[23]
    DIRECTION INPUT ;
    USE SIGNAL ;
    PORT
      LAYER M5 ;
        RECT  134.736 0 134.76 0.084 ;
    END
  END xai[23]
  PIN xai[240]
    DIRECTION INPUT ;
    USE SIGNAL ;
    PORT
      LAYER M5 ;
        RECT  165.984 0 166.008 0.084 ;
    END
  END xai[240]
  PIN xai[241]
    DIRECTION INPUT ;
    USE SIGNAL ;
    PORT
      LAYER M5 ;
        RECT  166.128 0 166.152 0.084 ;
    END
  END xai[241]
  PIN xai[242]
    DIRECTION INPUT ;
    USE SIGNAL ;
    PORT
      LAYER M5 ;
        RECT  166.272 0 166.296 0.084 ;
    END
  END xai[242]
  PIN xai[243]
    DIRECTION INPUT ;
    USE SIGNAL ;
    PORT
      LAYER M5 ;
        RECT  166.416 0 166.44 0.084 ;
    END
  END xai[243]
  PIN xai[244]
    DIRECTION INPUT ;
    USE SIGNAL ;
    PORT
      LAYER M5 ;
        RECT  166.56 0 166.584 0.084 ;
    END
  END xai[244]
  PIN xai[245]
    DIRECTION INPUT ;
    USE SIGNAL ;
    PORT
      LAYER M5 ;
        RECT  166.704 0 166.728 0.084 ;
    END
  END xai[245]
  PIN xai[246]
    DIRECTION INPUT ;
    USE SIGNAL ;
    PORT
      LAYER M5 ;
        RECT  166.848 0 166.872 0.084 ;
    END
  END xai[246]
  PIN xai[247]
    DIRECTION INPUT ;
    USE SIGNAL ;
    PORT
      LAYER M5 ;
        RECT  166.992 0 167.016 0.084 ;
    END
  END xai[247]
  PIN xai[248]
    DIRECTION INPUT ;
    USE SIGNAL ;
    PORT
      LAYER M5 ;
        RECT  167.136 0 167.16 0.084 ;
    END
  END xai[248]
  PIN xai[249]
    DIRECTION INPUT ;
    USE SIGNAL ;
    PORT
      LAYER M5 ;
        RECT  167.28 0 167.304 0.084 ;
    END
  END xai[249]
  PIN xai[24]
    DIRECTION INPUT ;
    USE SIGNAL ;
    PORT
      LAYER M5 ;
        RECT  134.88 0 134.904 0.084 ;
    END
  END xai[24]
  PIN xai[250]
    DIRECTION INPUT ;
    USE SIGNAL ;
    PORT
      LAYER M5 ;
        RECT  167.424 0 167.448 0.084 ;
    END
  END xai[250]
  PIN xai[251]
    DIRECTION INPUT ;
    USE SIGNAL ;
    PORT
      LAYER M5 ;
        RECT  167.568 0 167.592 0.084 ;
    END
  END xai[251]
  PIN xai[252]
    DIRECTION INPUT ;
    USE SIGNAL ;
    PORT
      LAYER M5 ;
        RECT  167.712 0 167.736 0.084 ;
    END
  END xai[252]
  PIN xai[253]
    DIRECTION INPUT ;
    USE SIGNAL ;
    PORT
      LAYER M5 ;
        RECT  167.856 0 167.88 0.084 ;
    END
  END xai[253]
  PIN xai[254]
    DIRECTION INPUT ;
    USE SIGNAL ;
    PORT
      LAYER M5 ;
        RECT  168 0 168.024 0.084 ;
    END
  END xai[254]
  PIN xai[255]
    DIRECTION INPUT ;
    USE SIGNAL ;
    PORT
      LAYER M5 ;
        RECT  168.144 0 168.168 0.084 ;
    END
  END xai[255]
  PIN xai[256]
    DIRECTION INPUT ;
    USE SIGNAL ;
    PORT
      LAYER M5 ;
        RECT  168.288 0 168.312 0.084 ;
    END
  END xai[256]
  PIN xai[257]
    DIRECTION INPUT ;
    USE SIGNAL ;
    PORT
      LAYER M5 ;
        RECT  168.432 0 168.456 0.084 ;
    END
  END xai[257]
  PIN xai[258]
    DIRECTION INPUT ;
    USE SIGNAL ;
    PORT
      LAYER M5 ;
        RECT  168.576 0 168.6 0.084 ;
    END
  END xai[258]
  PIN xai[259]
    DIRECTION INPUT ;
    USE SIGNAL ;
    PORT
      LAYER M5 ;
        RECT  168.72 0 168.744 0.084 ;
    END
  END xai[259]
  PIN xai[25]
    DIRECTION INPUT ;
    USE SIGNAL ;
    PORT
      LAYER M5 ;
        RECT  135.024 0 135.048 0.084 ;
    END
  END xai[25]
  PIN xai[260]
    DIRECTION INPUT ;
    USE SIGNAL ;
    PORT
      LAYER M5 ;
        RECT  168.864 0 168.888 0.084 ;
    END
  END xai[260]
  PIN xai[261]
    DIRECTION INPUT ;
    USE SIGNAL ;
    PORT
      LAYER M5 ;
        RECT  169.008 0 169.032 0.084 ;
    END
  END xai[261]
  PIN xai[262]
    DIRECTION INPUT ;
    USE SIGNAL ;
    PORT
      LAYER M5 ;
        RECT  169.152 0 169.176 0.084 ;
    END
  END xai[262]
  PIN xai[263]
    DIRECTION INPUT ;
    USE SIGNAL ;
    PORT
      LAYER M5 ;
        RECT  169.296 0 169.32 0.084 ;
    END
  END xai[263]
  PIN xai[264]
    DIRECTION INPUT ;
    USE SIGNAL ;
    PORT
      LAYER M5 ;
        RECT  169.44 0 169.464 0.084 ;
    END
  END xai[264]
  PIN xai[265]
    DIRECTION INPUT ;
    USE SIGNAL ;
    PORT
      LAYER M5 ;
        RECT  169.584 0 169.608 0.084 ;
    END
  END xai[265]
  PIN xai[266]
    DIRECTION INPUT ;
    USE SIGNAL ;
    PORT
      LAYER M5 ;
        RECT  169.728 0 169.752 0.084 ;
    END
  END xai[266]
  PIN xai[267]
    DIRECTION INPUT ;
    USE SIGNAL ;
    PORT
      LAYER M5 ;
        RECT  169.872 0 169.896 0.084 ;
    END
  END xai[267]
  PIN xai[268]
    DIRECTION INPUT ;
    USE SIGNAL ;
    PORT
      LAYER M5 ;
        RECT  170.016 0 170.04 0.084 ;
    END
  END xai[268]
  PIN xai[269]
    DIRECTION INPUT ;
    USE SIGNAL ;
    PORT
      LAYER M5 ;
        RECT  170.16 0 170.184 0.084 ;
    END
  END xai[269]
  PIN xai[26]
    DIRECTION INPUT ;
    USE SIGNAL ;
    PORT
      LAYER M5 ;
        RECT  135.168 0 135.192 0.084 ;
    END
  END xai[26]
  PIN xai[270]
    DIRECTION INPUT ;
    USE SIGNAL ;
    PORT
      LAYER M5 ;
        RECT  170.304 0 170.328 0.084 ;
    END
  END xai[270]
  PIN xai[271]
    DIRECTION INPUT ;
    USE SIGNAL ;
    PORT
      LAYER M5 ;
        RECT  170.448 0 170.472 0.084 ;
    END
  END xai[271]
  PIN xai[272]
    DIRECTION INPUT ;
    USE SIGNAL ;
    PORT
      LAYER M5 ;
        RECT  170.592 0 170.616 0.084 ;
    END
  END xai[272]
  PIN xai[273]
    DIRECTION INPUT ;
    USE SIGNAL ;
    PORT
      LAYER M5 ;
        RECT  170.736 0 170.76 0.084 ;
    END
  END xai[273]
  PIN xai[274]
    DIRECTION INPUT ;
    USE SIGNAL ;
    PORT
      LAYER M5 ;
        RECT  170.88 0 170.904 0.084 ;
    END
  END xai[274]
  PIN xai[275]
    DIRECTION INPUT ;
    USE SIGNAL ;
    PORT
      LAYER M5 ;
        RECT  171.024 0 171.048 0.084 ;
    END
  END xai[275]
  PIN xai[276]
    DIRECTION INPUT ;
    USE SIGNAL ;
    PORT
      LAYER M5 ;
        RECT  171.168 0 171.192 0.084 ;
    END
  END xai[276]
  PIN xai[277]
    DIRECTION INPUT ;
    USE SIGNAL ;
    PORT
      LAYER M5 ;
        RECT  171.312 0 171.336 0.084 ;
    END
  END xai[277]
  PIN xai[278]
    DIRECTION INPUT ;
    USE SIGNAL ;
    PORT
      LAYER M5 ;
        RECT  171.456 0 171.48 0.084 ;
    END
  END xai[278]
  PIN xai[279]
    DIRECTION INPUT ;
    USE SIGNAL ;
    PORT
      LAYER M5 ;
        RECT  171.6 0 171.624 0.084 ;
    END
  END xai[279]
  PIN xai[27]
    DIRECTION INPUT ;
    USE SIGNAL ;
    PORT
      LAYER M5 ;
        RECT  135.312 0 135.336 0.084 ;
    END
  END xai[27]
  PIN xai[280]
    DIRECTION INPUT ;
    USE SIGNAL ;
    PORT
      LAYER M5 ;
        RECT  171.744 0 171.768 0.084 ;
    END
  END xai[280]
  PIN xai[281]
    DIRECTION INPUT ;
    USE SIGNAL ;
    PORT
      LAYER M5 ;
        RECT  171.888 0 171.912 0.084 ;
    END
  END xai[281]
  PIN xai[282]
    DIRECTION INPUT ;
    USE SIGNAL ;
    PORT
      LAYER M5 ;
        RECT  172.032 0 172.056 0.084 ;
    END
  END xai[282]
  PIN xai[28]
    DIRECTION INPUT ;
    USE SIGNAL ;
    PORT
      LAYER M5 ;
        RECT  135.456 0 135.48 0.084 ;
    END
  END xai[28]
  PIN xai[29]
    DIRECTION INPUT ;
    USE SIGNAL ;
    PORT
      LAYER M5 ;
        RECT  135.6 0 135.624 0.084 ;
    END
  END xai[29]
  PIN xai[2]
    DIRECTION INPUT ;
    USE SIGNAL ;
    PORT
      LAYER M5 ;
        RECT  131.712 0 131.736 0.084 ;
    END
  END xai[2]
  PIN xai[30]
    DIRECTION INPUT ;
    USE SIGNAL ;
    PORT
      LAYER M5 ;
        RECT  135.744 0 135.768 0.084 ;
    END
  END xai[30]
  PIN xai[31]
    DIRECTION INPUT ;
    USE SIGNAL ;
    PORT
      LAYER M5 ;
        RECT  135.888 0 135.912 0.084 ;
    END
  END xai[31]
  PIN xai[32]
    DIRECTION INPUT ;
    USE SIGNAL ;
    PORT
      LAYER M5 ;
        RECT  136.032 0 136.056 0.084 ;
    END
  END xai[32]
  PIN xai[33]
    DIRECTION INPUT ;
    USE SIGNAL ;
    PORT
      LAYER M5 ;
        RECT  136.176 0 136.2 0.084 ;
    END
  END xai[33]
  PIN xai[34]
    DIRECTION INPUT ;
    USE SIGNAL ;
    PORT
      LAYER M5 ;
        RECT  136.32 0 136.344 0.084 ;
    END
  END xai[34]
  PIN xai[35]
    DIRECTION INPUT ;
    USE SIGNAL ;
    PORT
      LAYER M5 ;
        RECT  136.464 0 136.488 0.084 ;
    END
  END xai[35]
  PIN xai[36]
    DIRECTION INPUT ;
    USE SIGNAL ;
    PORT
      LAYER M5 ;
        RECT  136.608 0 136.632 0.084 ;
    END
  END xai[36]
  PIN xai[37]
    DIRECTION INPUT ;
    USE SIGNAL ;
    PORT
      LAYER M5 ;
        RECT  136.752 0 136.776 0.084 ;
    END
  END xai[37]
  PIN xai[38]
    DIRECTION INPUT ;
    USE SIGNAL ;
    PORT
      LAYER M5 ;
        RECT  136.896 0 136.92 0.084 ;
    END
  END xai[38]
  PIN xai[39]
    DIRECTION INPUT ;
    USE SIGNAL ;
    PORT
      LAYER M5 ;
        RECT  137.04 0 137.064 0.084 ;
    END
  END xai[39]
  PIN xai[3]
    DIRECTION INPUT ;
    USE SIGNAL ;
    PORT
      LAYER M5 ;
        RECT  131.856 0 131.88 0.084 ;
    END
  END xai[3]
  PIN xai[40]
    DIRECTION INPUT ;
    USE SIGNAL ;
    PORT
      LAYER M5 ;
        RECT  137.184 0 137.208 0.084 ;
    END
  END xai[40]
  PIN xai[41]
    DIRECTION INPUT ;
    USE SIGNAL ;
    PORT
      LAYER M5 ;
        RECT  137.328 0 137.352 0.084 ;
    END
  END xai[41]
  PIN xai[42]
    DIRECTION INPUT ;
    USE SIGNAL ;
    PORT
      LAYER M5 ;
        RECT  137.472 0 137.496 0.084 ;
    END
  END xai[42]
  PIN xai[43]
    DIRECTION INPUT ;
    USE SIGNAL ;
    PORT
      LAYER M5 ;
        RECT  137.616 0 137.64 0.084 ;
    END
  END xai[43]
  PIN xai[44]
    DIRECTION INPUT ;
    USE SIGNAL ;
    PORT
      LAYER M5 ;
        RECT  137.76 0 137.784 0.084 ;
    END
  END xai[44]
  PIN xai[45]
    DIRECTION INPUT ;
    USE SIGNAL ;
    PORT
      LAYER M5 ;
        RECT  137.904 0 137.928 0.084 ;
    END
  END xai[45]
  PIN xai[46]
    DIRECTION INPUT ;
    USE SIGNAL ;
    PORT
      LAYER M5 ;
        RECT  138.048 0 138.072 0.084 ;
    END
  END xai[46]
  PIN xai[47]
    DIRECTION INPUT ;
    USE SIGNAL ;
    PORT
      LAYER M5 ;
        RECT  138.192 0 138.216 0.084 ;
    END
  END xai[47]
  PIN xai[48]
    DIRECTION INPUT ;
    USE SIGNAL ;
    PORT
      LAYER M5 ;
        RECT  138.336 0 138.36 0.084 ;
    END
  END xai[48]
  PIN xai[49]
    DIRECTION INPUT ;
    USE SIGNAL ;
    PORT
      LAYER M5 ;
        RECT  138.48 0 138.504 0.084 ;
    END
  END xai[49]
  PIN xai[4]
    DIRECTION INPUT ;
    USE SIGNAL ;
    PORT
      LAYER M5 ;
        RECT  132 0 132.024 0.084 ;
    END
  END xai[4]
  PIN xai[50]
    DIRECTION INPUT ;
    USE SIGNAL ;
    PORT
      LAYER M5 ;
        RECT  138.624 0 138.648 0.084 ;
    END
  END xai[50]
  PIN xai[51]
    DIRECTION INPUT ;
    USE SIGNAL ;
    PORT
      LAYER M5 ;
        RECT  138.768 0 138.792 0.084 ;
    END
  END xai[51]
  PIN xai[52]
    DIRECTION INPUT ;
    USE SIGNAL ;
    PORT
      LAYER M5 ;
        RECT  138.912 0 138.936 0.084 ;
    END
  END xai[52]
  PIN xai[53]
    DIRECTION INPUT ;
    USE SIGNAL ;
    PORT
      LAYER M5 ;
        RECT  139.056 0 139.08 0.084 ;
    END
  END xai[53]
  PIN xai[54]
    DIRECTION INPUT ;
    USE SIGNAL ;
    PORT
      LAYER M5 ;
        RECT  139.2 0 139.224 0.084 ;
    END
  END xai[54]
  PIN xai[55]
    DIRECTION INPUT ;
    USE SIGNAL ;
    PORT
      LAYER M5 ;
        RECT  139.344 0 139.368 0.084 ;
    END
  END xai[55]
  PIN xai[56]
    DIRECTION INPUT ;
    USE SIGNAL ;
    PORT
      LAYER M5 ;
        RECT  139.488 0 139.512 0.084 ;
    END
  END xai[56]
  PIN xai[57]
    DIRECTION INPUT ;
    USE SIGNAL ;
    PORT
      LAYER M5 ;
        RECT  139.632 0 139.656 0.084 ;
    END
  END xai[57]
  PIN xai[58]
    DIRECTION INPUT ;
    USE SIGNAL ;
    PORT
      LAYER M5 ;
        RECT  139.776 0 139.8 0.084 ;
    END
  END xai[58]
  PIN xai[59]
    DIRECTION INPUT ;
    USE SIGNAL ;
    PORT
      LAYER M5 ;
        RECT  139.92 0 139.944 0.084 ;
    END
  END xai[59]
  PIN xai[5]
    DIRECTION INPUT ;
    USE SIGNAL ;
    PORT
      LAYER M5 ;
        RECT  132.144 0 132.168 0.084 ;
    END
  END xai[5]
  PIN xai[60]
    DIRECTION INPUT ;
    USE SIGNAL ;
    PORT
      LAYER M5 ;
        RECT  140.064 0 140.088 0.084 ;
    END
  END xai[60]
  PIN xai[61]
    DIRECTION INPUT ;
    USE SIGNAL ;
    PORT
      LAYER M5 ;
        RECT  140.208 0 140.232 0.084 ;
    END
  END xai[61]
  PIN xai[62]
    DIRECTION INPUT ;
    USE SIGNAL ;
    PORT
      LAYER M5 ;
        RECT  140.352 0 140.376 0.084 ;
    END
  END xai[62]
  PIN xai[63]
    DIRECTION INPUT ;
    USE SIGNAL ;
    PORT
      LAYER M5 ;
        RECT  140.496 0 140.52 0.084 ;
    END
  END xai[63]
  PIN xai[64]
    DIRECTION INPUT ;
    USE SIGNAL ;
    PORT
      LAYER M5 ;
        RECT  140.64 0 140.664 0.084 ;
    END
  END xai[64]
  PIN xai[65]
    DIRECTION INPUT ;
    USE SIGNAL ;
    PORT
      LAYER M5 ;
        RECT  140.784 0 140.808 0.084 ;
    END
  END xai[65]
  PIN xai[66]
    DIRECTION INPUT ;
    USE SIGNAL ;
    PORT
      LAYER M5 ;
        RECT  140.928 0 140.952 0.084 ;
    END
  END xai[66]
  PIN xai[67]
    DIRECTION INPUT ;
    USE SIGNAL ;
    PORT
      LAYER M5 ;
        RECT  141.072 0 141.096 0.084 ;
    END
  END xai[67]
  PIN xai[68]
    DIRECTION INPUT ;
    USE SIGNAL ;
    PORT
      LAYER M5 ;
        RECT  141.216 0 141.24 0.084 ;
    END
  END xai[68]
  PIN xai[69]
    DIRECTION INPUT ;
    USE SIGNAL ;
    PORT
      LAYER M5 ;
        RECT  141.36 0 141.384 0.084 ;
    END
  END xai[69]
  PIN xai[6]
    DIRECTION INPUT ;
    USE SIGNAL ;
    PORT
      LAYER M5 ;
        RECT  132.288 0 132.312 0.084 ;
    END
  END xai[6]
  PIN xai[70]
    DIRECTION INPUT ;
    USE SIGNAL ;
    PORT
      LAYER M5 ;
        RECT  141.504 0 141.528 0.084 ;
    END
  END xai[70]
  PIN xai[71]
    DIRECTION INPUT ;
    USE SIGNAL ;
    PORT
      LAYER M5 ;
        RECT  141.648 0 141.672 0.084 ;
    END
  END xai[71]
  PIN xai[72]
    DIRECTION INPUT ;
    USE SIGNAL ;
    PORT
      LAYER M5 ;
        RECT  141.792 0 141.816 0.084 ;
    END
  END xai[72]
  PIN xai[73]
    DIRECTION INPUT ;
    USE SIGNAL ;
    PORT
      LAYER M5 ;
        RECT  141.936 0 141.96 0.084 ;
    END
  END xai[73]
  PIN xai[74]
    DIRECTION INPUT ;
    USE SIGNAL ;
    PORT
      LAYER M5 ;
        RECT  142.08 0 142.104 0.084 ;
    END
  END xai[74]
  PIN xai[75]
    DIRECTION INPUT ;
    USE SIGNAL ;
    PORT
      LAYER M5 ;
        RECT  142.224 0 142.248 0.084 ;
    END
  END xai[75]
  PIN xai[76]
    DIRECTION INPUT ;
    USE SIGNAL ;
    PORT
      LAYER M5 ;
        RECT  142.368 0 142.392 0.084 ;
    END
  END xai[76]
  PIN xai[77]
    DIRECTION INPUT ;
    USE SIGNAL ;
    PORT
      LAYER M5 ;
        RECT  142.512 0 142.536 0.084 ;
    END
  END xai[77]
  PIN xai[78]
    DIRECTION INPUT ;
    USE SIGNAL ;
    PORT
      LAYER M5 ;
        RECT  142.656 0 142.68 0.084 ;
    END
  END xai[78]
  PIN xai[79]
    DIRECTION INPUT ;
    USE SIGNAL ;
    PORT
      LAYER M5 ;
        RECT  142.8 0 142.824 0.084 ;
    END
  END xai[79]
  PIN xai[7]
    DIRECTION INPUT ;
    USE SIGNAL ;
    PORT
      LAYER M5 ;
        RECT  132.432 0 132.456 0.084 ;
    END
  END xai[7]
  PIN xai[80]
    DIRECTION INPUT ;
    USE SIGNAL ;
    PORT
      LAYER M5 ;
        RECT  142.944 0 142.968 0.084 ;
    END
  END xai[80]
  PIN xai[81]
    DIRECTION INPUT ;
    USE SIGNAL ;
    PORT
      LAYER M5 ;
        RECT  143.088 0 143.112 0.084 ;
    END
  END xai[81]
  PIN xai[82]
    DIRECTION INPUT ;
    USE SIGNAL ;
    PORT
      LAYER M5 ;
        RECT  143.232 0 143.256 0.084 ;
    END
  END xai[82]
  PIN xai[83]
    DIRECTION INPUT ;
    USE SIGNAL ;
    PORT
      LAYER M5 ;
        RECT  143.376 0 143.4 0.084 ;
    END
  END xai[83]
  PIN xai[84]
    DIRECTION INPUT ;
    USE SIGNAL ;
    PORT
      LAYER M5 ;
        RECT  143.52 0 143.544 0.084 ;
    END
  END xai[84]
  PIN xai[85]
    DIRECTION INPUT ;
    USE SIGNAL ;
    PORT
      LAYER M5 ;
        RECT  143.664 0 143.688 0.084 ;
    END
  END xai[85]
  PIN xai[86]
    DIRECTION INPUT ;
    USE SIGNAL ;
    PORT
      LAYER M5 ;
        RECT  143.808 0 143.832 0.084 ;
    END
  END xai[86]
  PIN xai[87]
    DIRECTION INPUT ;
    USE SIGNAL ;
    PORT
      LAYER M5 ;
        RECT  143.952 0 143.976 0.084 ;
    END
  END xai[87]
  PIN xai[88]
    DIRECTION INPUT ;
    USE SIGNAL ;
    PORT
      LAYER M5 ;
        RECT  144.096 0 144.12 0.084 ;
    END
  END xai[88]
  PIN xai[89]
    DIRECTION INPUT ;
    USE SIGNAL ;
    PORT
      LAYER M5 ;
        RECT  144.24 0 144.264 0.084 ;
    END
  END xai[89]
  PIN xai[8]
    DIRECTION INPUT ;
    USE SIGNAL ;
    PORT
      LAYER M5 ;
        RECT  132.576 0 132.6 0.084 ;
    END
  END xai[8]
  PIN xai[90]
    DIRECTION INPUT ;
    USE SIGNAL ;
    PORT
      LAYER M5 ;
        RECT  144.384 0 144.408 0.084 ;
    END
  END xai[90]
  PIN xai[91]
    DIRECTION INPUT ;
    USE SIGNAL ;
    PORT
      LAYER M5 ;
        RECT  144.528 0 144.552 0.084 ;
    END
  END xai[91]
  PIN xai[92]
    DIRECTION INPUT ;
    USE SIGNAL ;
    PORT
      LAYER M5 ;
        RECT  144.672 0 144.696 0.084 ;
    END
  END xai[92]
  PIN xai[93]
    DIRECTION INPUT ;
    USE SIGNAL ;
    PORT
      LAYER M5 ;
        RECT  144.816 0 144.84 0.084 ;
    END
  END xai[93]
  PIN xai[94]
    DIRECTION INPUT ;
    USE SIGNAL ;
    PORT
      LAYER M5 ;
        RECT  144.96 0 144.984 0.084 ;
    END
  END xai[94]
  PIN xai[95]
    DIRECTION INPUT ;
    USE SIGNAL ;
    PORT
      LAYER M5 ;
        RECT  145.104 0 145.128 0.084 ;
    END
  END xai[95]
  PIN xai[96]
    DIRECTION INPUT ;
    USE SIGNAL ;
    PORT
      LAYER M5 ;
        RECT  145.248 0 145.272 0.084 ;
    END
  END xai[96]
  PIN xai[97]
    DIRECTION INPUT ;
    USE SIGNAL ;
    PORT
      LAYER M5 ;
        RECT  145.392 0 145.416 0.084 ;
    END
  END xai[97]
  PIN xai[98]
    DIRECTION INPUT ;
    USE SIGNAL ;
    PORT
      LAYER M5 ;
        RECT  145.536 0 145.56 0.084 ;
    END
  END xai[98]
  PIN xai[99]
    DIRECTION INPUT ;
    USE SIGNAL ;
    PORT
      LAYER M5 ;
        RECT  145.68 0 145.704 0.084 ;
    END
  END xai[99]
  PIN xai[9]
    DIRECTION INPUT ;
    USE SIGNAL ;
    PORT
      LAYER M5 ;
        RECT  132.72 0 132.744 0.084 ;
    END
  END xai[9]
  PIN xb[0]
    DIRECTION OUTPUT ;
    USE SIGNAL ;
    PORT
      LAYER M5 ;
        RECT  89.664 30.156 89.688 30.24 ;
    END
  END xb[0]
  PIN xb[100]
    DIRECTION OUTPUT ;
    USE SIGNAL ;
    PORT
      LAYER M5 ;
        RECT  104.064 30.156 104.088 30.24 ;
    END
  END xb[100]
  PIN xb[101]
    DIRECTION OUTPUT ;
    USE SIGNAL ;
    PORT
      LAYER M5 ;
        RECT  104.208 30.156 104.232 30.24 ;
    END
  END xb[101]
  PIN xb[102]
    DIRECTION OUTPUT ;
    USE SIGNAL ;
    PORT
      LAYER M5 ;
        RECT  104.352 30.156 104.376 30.24 ;
    END
  END xb[102]
  PIN xb[103]
    DIRECTION OUTPUT ;
    USE SIGNAL ;
    PORT
      LAYER M5 ;
        RECT  104.496 30.156 104.52 30.24 ;
    END
  END xb[103]
  PIN xb[104]
    DIRECTION OUTPUT ;
    USE SIGNAL ;
    PORT
      LAYER M5 ;
        RECT  104.64 30.156 104.664 30.24 ;
    END
  END xb[104]
  PIN xb[105]
    DIRECTION OUTPUT ;
    USE SIGNAL ;
    PORT
      LAYER M5 ;
        RECT  104.784 30.156 104.808 30.24 ;
    END
  END xb[105]
  PIN xb[106]
    DIRECTION OUTPUT ;
    USE SIGNAL ;
    PORT
      LAYER M5 ;
        RECT  104.928 30.156 104.952 30.24 ;
    END
  END xb[106]
  PIN xb[107]
    DIRECTION OUTPUT ;
    USE SIGNAL ;
    PORT
      LAYER M5 ;
        RECT  105.072 30.156 105.096 30.24 ;
    END
  END xb[107]
  PIN xb[108]
    DIRECTION OUTPUT ;
    USE SIGNAL ;
    PORT
      LAYER M5 ;
        RECT  105.216 30.156 105.24 30.24 ;
    END
  END xb[108]
  PIN xb[109]
    DIRECTION OUTPUT ;
    USE SIGNAL ;
    PORT
      LAYER M5 ;
        RECT  105.36 30.156 105.384 30.24 ;
    END
  END xb[109]
  PIN xb[10]
    DIRECTION OUTPUT ;
    USE SIGNAL ;
    PORT
      LAYER M5 ;
        RECT  91.104 30.156 91.128 30.24 ;
    END
  END xb[10]
  PIN xb[110]
    DIRECTION OUTPUT ;
    USE SIGNAL ;
    PORT
      LAYER M5 ;
        RECT  105.504 30.156 105.528 30.24 ;
    END
  END xb[110]
  PIN xb[111]
    DIRECTION OUTPUT ;
    USE SIGNAL ;
    PORT
      LAYER M5 ;
        RECT  105.648 30.156 105.672 30.24 ;
    END
  END xb[111]
  PIN xb[112]
    DIRECTION OUTPUT ;
    USE SIGNAL ;
    PORT
      LAYER M5 ;
        RECT  105.792 30.156 105.816 30.24 ;
    END
  END xb[112]
  PIN xb[113]
    DIRECTION OUTPUT ;
    USE SIGNAL ;
    PORT
      LAYER M5 ;
        RECT  105.936 30.156 105.96 30.24 ;
    END
  END xb[113]
  PIN xb[114]
    DIRECTION OUTPUT ;
    USE SIGNAL ;
    PORT
      LAYER M5 ;
        RECT  106.08 30.156 106.104 30.24 ;
    END
  END xb[114]
  PIN xb[115]
    DIRECTION OUTPUT ;
    USE SIGNAL ;
    PORT
      LAYER M5 ;
        RECT  106.224 30.156 106.248 30.24 ;
    END
  END xb[115]
  PIN xb[116]
    DIRECTION OUTPUT ;
    USE SIGNAL ;
    PORT
      LAYER M5 ;
        RECT  106.368 30.156 106.392 30.24 ;
    END
  END xb[116]
  PIN xb[117]
    DIRECTION OUTPUT ;
    USE SIGNAL ;
    PORT
      LAYER M5 ;
        RECT  106.512 30.156 106.536 30.24 ;
    END
  END xb[117]
  PIN xb[118]
    DIRECTION OUTPUT ;
    USE SIGNAL ;
    PORT
      LAYER M5 ;
        RECT  106.656 30.156 106.68 30.24 ;
    END
  END xb[118]
  PIN xb[119]
    DIRECTION OUTPUT ;
    USE SIGNAL ;
    PORT
      LAYER M5 ;
        RECT  106.8 30.156 106.824 30.24 ;
    END
  END xb[119]
  PIN xb[11]
    DIRECTION OUTPUT ;
    USE SIGNAL ;
    PORT
      LAYER M5 ;
        RECT  91.248 30.156 91.272 30.24 ;
    END
  END xb[11]
  PIN xb[120]
    DIRECTION OUTPUT ;
    USE SIGNAL ;
    PORT
      LAYER M5 ;
        RECT  106.944 30.156 106.968 30.24 ;
    END
  END xb[120]
  PIN xb[121]
    DIRECTION OUTPUT ;
    USE SIGNAL ;
    PORT
      LAYER M5 ;
        RECT  107.088 30.156 107.112 30.24 ;
    END
  END xb[121]
  PIN xb[122]
    DIRECTION OUTPUT ;
    USE SIGNAL ;
    PORT
      LAYER M5 ;
        RECT  107.232 30.156 107.256 30.24 ;
    END
  END xb[122]
  PIN xb[123]
    DIRECTION OUTPUT ;
    USE SIGNAL ;
    PORT
      LAYER M5 ;
        RECT  107.376 30.156 107.4 30.24 ;
    END
  END xb[123]
  PIN xb[124]
    DIRECTION OUTPUT ;
    USE SIGNAL ;
    PORT
      LAYER M5 ;
        RECT  107.52 30.156 107.544 30.24 ;
    END
  END xb[124]
  PIN xb[125]
    DIRECTION OUTPUT ;
    USE SIGNAL ;
    PORT
      LAYER M5 ;
        RECT  107.664 30.156 107.688 30.24 ;
    END
  END xb[125]
  PIN xb[126]
    DIRECTION OUTPUT ;
    USE SIGNAL ;
    PORT
      LAYER M5 ;
        RECT  107.808 30.156 107.832 30.24 ;
    END
  END xb[126]
  PIN xb[127]
    DIRECTION OUTPUT ;
    USE SIGNAL ;
    PORT
      LAYER M5 ;
        RECT  107.952 30.156 107.976 30.24 ;
    END
  END xb[127]
  PIN xb[128]
    DIRECTION OUTPUT ;
    USE SIGNAL ;
    PORT
      LAYER M5 ;
        RECT  108.096 30.156 108.12 30.24 ;
    END
  END xb[128]
  PIN xb[129]
    DIRECTION OUTPUT ;
    USE SIGNAL ;
    PORT
      LAYER M5 ;
        RECT  108.24 30.156 108.264 30.24 ;
    END
  END xb[129]
  PIN xb[12]
    DIRECTION OUTPUT ;
    USE SIGNAL ;
    PORT
      LAYER M5 ;
        RECT  91.392 30.156 91.416 30.24 ;
    END
  END xb[12]
  PIN xb[130]
    DIRECTION OUTPUT ;
    USE SIGNAL ;
    PORT
      LAYER M5 ;
        RECT  108.384 30.156 108.408 30.24 ;
    END
  END xb[130]
  PIN xb[131]
    DIRECTION OUTPUT ;
    USE SIGNAL ;
    PORT
      LAYER M5 ;
        RECT  108.528 30.156 108.552 30.24 ;
    END
  END xb[131]
  PIN xb[132]
    DIRECTION OUTPUT ;
    USE SIGNAL ;
    PORT
      LAYER M5 ;
        RECT  108.672 30.156 108.696 30.24 ;
    END
  END xb[132]
  PIN xb[133]
    DIRECTION OUTPUT ;
    USE SIGNAL ;
    PORT
      LAYER M5 ;
        RECT  108.816 30.156 108.84 30.24 ;
    END
  END xb[133]
  PIN xb[134]
    DIRECTION OUTPUT ;
    USE SIGNAL ;
    PORT
      LAYER M5 ;
        RECT  108.96 30.156 108.984 30.24 ;
    END
  END xb[134]
  PIN xb[135]
    DIRECTION OUTPUT ;
    USE SIGNAL ;
    PORT
      LAYER M5 ;
        RECT  109.104 30.156 109.128 30.24 ;
    END
  END xb[135]
  PIN xb[136]
    DIRECTION OUTPUT ;
    USE SIGNAL ;
    PORT
      LAYER M5 ;
        RECT  109.248 30.156 109.272 30.24 ;
    END
  END xb[136]
  PIN xb[137]
    DIRECTION OUTPUT ;
    USE SIGNAL ;
    PORT
      LAYER M5 ;
        RECT  109.392 30.156 109.416 30.24 ;
    END
  END xb[137]
  PIN xb[138]
    DIRECTION OUTPUT ;
    USE SIGNAL ;
    PORT
      LAYER M5 ;
        RECT  109.536 30.156 109.56 30.24 ;
    END
  END xb[138]
  PIN xb[139]
    DIRECTION OUTPUT ;
    USE SIGNAL ;
    PORT
      LAYER M5 ;
        RECT  109.68 30.156 109.704 30.24 ;
    END
  END xb[139]
  PIN xb[13]
    DIRECTION OUTPUT ;
    USE SIGNAL ;
    PORT
      LAYER M5 ;
        RECT  91.536 30.156 91.56 30.24 ;
    END
  END xb[13]
  PIN xb[140]
    DIRECTION OUTPUT ;
    USE SIGNAL ;
    PORT
      LAYER M5 ;
        RECT  109.824 30.156 109.848 30.24 ;
    END
  END xb[140]
  PIN xb[141]
    DIRECTION OUTPUT ;
    USE SIGNAL ;
    PORT
      LAYER M5 ;
        RECT  109.968 30.156 109.992 30.24 ;
    END
  END xb[141]
  PIN xb[142]
    DIRECTION OUTPUT ;
    USE SIGNAL ;
    PORT
      LAYER M5 ;
        RECT  110.112 30.156 110.136 30.24 ;
    END
  END xb[142]
  PIN xb[143]
    DIRECTION OUTPUT ;
    USE SIGNAL ;
    PORT
      LAYER M5 ;
        RECT  110.256 30.156 110.28 30.24 ;
    END
  END xb[143]
  PIN xb[144]
    DIRECTION OUTPUT ;
    USE SIGNAL ;
    PORT
      LAYER M5 ;
        RECT  110.4 30.156 110.424 30.24 ;
    END
  END xb[144]
  PIN xb[145]
    DIRECTION OUTPUT ;
    USE SIGNAL ;
    PORT
      LAYER M5 ;
        RECT  110.544 30.156 110.568 30.24 ;
    END
  END xb[145]
  PIN xb[146]
    DIRECTION OUTPUT ;
    USE SIGNAL ;
    PORT
      LAYER M5 ;
        RECT  110.688 30.156 110.712 30.24 ;
    END
  END xb[146]
  PIN xb[147]
    DIRECTION OUTPUT ;
    USE SIGNAL ;
    PORT
      LAYER M5 ;
        RECT  110.832 30.156 110.856 30.24 ;
    END
  END xb[147]
  PIN xb[148]
    DIRECTION OUTPUT ;
    USE SIGNAL ;
    PORT
      LAYER M5 ;
        RECT  110.976 30.156 111 30.24 ;
    END
  END xb[148]
  PIN xb[149]
    DIRECTION OUTPUT ;
    USE SIGNAL ;
    PORT
      LAYER M5 ;
        RECT  111.12 30.156 111.144 30.24 ;
    END
  END xb[149]
  PIN xb[14]
    DIRECTION OUTPUT ;
    USE SIGNAL ;
    PORT
      LAYER M5 ;
        RECT  91.68 30.156 91.704 30.24 ;
    END
  END xb[14]
  PIN xb[150]
    DIRECTION OUTPUT ;
    USE SIGNAL ;
    PORT
      LAYER M5 ;
        RECT  111.264 30.156 111.288 30.24 ;
    END
  END xb[150]
  PIN xb[151]
    DIRECTION OUTPUT ;
    USE SIGNAL ;
    PORT
      LAYER M5 ;
        RECT  111.408 30.156 111.432 30.24 ;
    END
  END xb[151]
  PIN xb[152]
    DIRECTION OUTPUT ;
    USE SIGNAL ;
    PORT
      LAYER M5 ;
        RECT  111.552 30.156 111.576 30.24 ;
    END
  END xb[152]
  PIN xb[153]
    DIRECTION OUTPUT ;
    USE SIGNAL ;
    PORT
      LAYER M5 ;
        RECT  111.696 30.156 111.72 30.24 ;
    END
  END xb[153]
  PIN xb[154]
    DIRECTION OUTPUT ;
    USE SIGNAL ;
    PORT
      LAYER M5 ;
        RECT  111.84 30.156 111.864 30.24 ;
    END
  END xb[154]
  PIN xb[155]
    DIRECTION OUTPUT ;
    USE SIGNAL ;
    PORT
      LAYER M5 ;
        RECT  111.984 30.156 112.008 30.24 ;
    END
  END xb[155]
  PIN xb[156]
    DIRECTION OUTPUT ;
    USE SIGNAL ;
    PORT
      LAYER M5 ;
        RECT  112.128 30.156 112.152 30.24 ;
    END
  END xb[156]
  PIN xb[157]
    DIRECTION OUTPUT ;
    USE SIGNAL ;
    PORT
      LAYER M5 ;
        RECT  112.272 30.156 112.296 30.24 ;
    END
  END xb[157]
  PIN xb[158]
    DIRECTION OUTPUT ;
    USE SIGNAL ;
    PORT
      LAYER M5 ;
        RECT  112.416 30.156 112.44 30.24 ;
    END
  END xb[158]
  PIN xb[159]
    DIRECTION OUTPUT ;
    USE SIGNAL ;
    PORT
      LAYER M5 ;
        RECT  112.56 30.156 112.584 30.24 ;
    END
  END xb[159]
  PIN xb[15]
    DIRECTION OUTPUT ;
    USE SIGNAL ;
    PORT
      LAYER M5 ;
        RECT  91.824 30.156 91.848 30.24 ;
    END
  END xb[15]
  PIN xb[160]
    DIRECTION OUTPUT ;
    USE SIGNAL ;
    PORT
      LAYER M5 ;
        RECT  112.704 30.156 112.728 30.24 ;
    END
  END xb[160]
  PIN xb[161]
    DIRECTION OUTPUT ;
    USE SIGNAL ;
    PORT
      LAYER M5 ;
        RECT  112.848 30.156 112.872 30.24 ;
    END
  END xb[161]
  PIN xb[162]
    DIRECTION OUTPUT ;
    USE SIGNAL ;
    PORT
      LAYER M5 ;
        RECT  112.992 30.156 113.016 30.24 ;
    END
  END xb[162]
  PIN xb[163]
    DIRECTION OUTPUT ;
    USE SIGNAL ;
    PORT
      LAYER M5 ;
        RECT  113.136 30.156 113.16 30.24 ;
    END
  END xb[163]
  PIN xb[164]
    DIRECTION OUTPUT ;
    USE SIGNAL ;
    PORT
      LAYER M5 ;
        RECT  113.28 30.156 113.304 30.24 ;
    END
  END xb[164]
  PIN xb[165]
    DIRECTION OUTPUT ;
    USE SIGNAL ;
    PORT
      LAYER M5 ;
        RECT  113.424 30.156 113.448 30.24 ;
    END
  END xb[165]
  PIN xb[166]
    DIRECTION OUTPUT ;
    USE SIGNAL ;
    PORT
      LAYER M5 ;
        RECT  113.568 30.156 113.592 30.24 ;
    END
  END xb[166]
  PIN xb[167]
    DIRECTION OUTPUT ;
    USE SIGNAL ;
    PORT
      LAYER M5 ;
        RECT  113.712 30.156 113.736 30.24 ;
    END
  END xb[167]
  PIN xb[168]
    DIRECTION OUTPUT ;
    USE SIGNAL ;
    PORT
      LAYER M5 ;
        RECT  113.856 30.156 113.88 30.24 ;
    END
  END xb[168]
  PIN xb[169]
    DIRECTION OUTPUT ;
    USE SIGNAL ;
    PORT
      LAYER M5 ;
        RECT  114 30.156 114.024 30.24 ;
    END
  END xb[169]
  PIN xb[16]
    DIRECTION OUTPUT ;
    USE SIGNAL ;
    PORT
      LAYER M5 ;
        RECT  91.968 30.156 91.992 30.24 ;
    END
  END xb[16]
  PIN xb[170]
    DIRECTION OUTPUT ;
    USE SIGNAL ;
    PORT
      LAYER M5 ;
        RECT  114.144 30.156 114.168 30.24 ;
    END
  END xb[170]
  PIN xb[171]
    DIRECTION OUTPUT ;
    USE SIGNAL ;
    PORT
      LAYER M5 ;
        RECT  114.288 30.156 114.312 30.24 ;
    END
  END xb[171]
  PIN xb[172]
    DIRECTION OUTPUT ;
    USE SIGNAL ;
    PORT
      LAYER M5 ;
        RECT  114.432 30.156 114.456 30.24 ;
    END
  END xb[172]
  PIN xb[173]
    DIRECTION OUTPUT ;
    USE SIGNAL ;
    PORT
      LAYER M5 ;
        RECT  114.576 30.156 114.6 30.24 ;
    END
  END xb[173]
  PIN xb[174]
    DIRECTION OUTPUT ;
    USE SIGNAL ;
    PORT
      LAYER M5 ;
        RECT  114.72 30.156 114.744 30.24 ;
    END
  END xb[174]
  PIN xb[175]
    DIRECTION OUTPUT ;
    USE SIGNAL ;
    PORT
      LAYER M5 ;
        RECT  114.864 30.156 114.888 30.24 ;
    END
  END xb[175]
  PIN xb[176]
    DIRECTION OUTPUT ;
    USE SIGNAL ;
    PORT
      LAYER M5 ;
        RECT  115.008 30.156 115.032 30.24 ;
    END
  END xb[176]
  PIN xb[177]
    DIRECTION OUTPUT ;
    USE SIGNAL ;
    PORT
      LAYER M5 ;
        RECT  115.152 30.156 115.176 30.24 ;
    END
  END xb[177]
  PIN xb[178]
    DIRECTION OUTPUT ;
    USE SIGNAL ;
    PORT
      LAYER M5 ;
        RECT  115.296 30.156 115.32 30.24 ;
    END
  END xb[178]
  PIN xb[179]
    DIRECTION OUTPUT ;
    USE SIGNAL ;
    PORT
      LAYER M5 ;
        RECT  115.44 30.156 115.464 30.24 ;
    END
  END xb[179]
  PIN xb[17]
    DIRECTION OUTPUT ;
    USE SIGNAL ;
    PORT
      LAYER M5 ;
        RECT  92.112 30.156 92.136 30.24 ;
    END
  END xb[17]
  PIN xb[180]
    DIRECTION OUTPUT ;
    USE SIGNAL ;
    PORT
      LAYER M5 ;
        RECT  115.584 30.156 115.608 30.24 ;
    END
  END xb[180]
  PIN xb[181]
    DIRECTION OUTPUT ;
    USE SIGNAL ;
    PORT
      LAYER M5 ;
        RECT  115.728 30.156 115.752 30.24 ;
    END
  END xb[181]
  PIN xb[182]
    DIRECTION OUTPUT ;
    USE SIGNAL ;
    PORT
      LAYER M5 ;
        RECT  115.872 30.156 115.896 30.24 ;
    END
  END xb[182]
  PIN xb[183]
    DIRECTION OUTPUT ;
    USE SIGNAL ;
    PORT
      LAYER M5 ;
        RECT  116.016 30.156 116.04 30.24 ;
    END
  END xb[183]
  PIN xb[184]
    DIRECTION OUTPUT ;
    USE SIGNAL ;
    PORT
      LAYER M5 ;
        RECT  116.16 30.156 116.184 30.24 ;
    END
  END xb[184]
  PIN xb[185]
    DIRECTION OUTPUT ;
    USE SIGNAL ;
    PORT
      LAYER M5 ;
        RECT  116.304 30.156 116.328 30.24 ;
    END
  END xb[185]
  PIN xb[186]
    DIRECTION OUTPUT ;
    USE SIGNAL ;
    PORT
      LAYER M5 ;
        RECT  116.448 30.156 116.472 30.24 ;
    END
  END xb[186]
  PIN xb[187]
    DIRECTION OUTPUT ;
    USE SIGNAL ;
    PORT
      LAYER M5 ;
        RECT  116.592 30.156 116.616 30.24 ;
    END
  END xb[187]
  PIN xb[188]
    DIRECTION OUTPUT ;
    USE SIGNAL ;
    PORT
      LAYER M5 ;
        RECT  116.736 30.156 116.76 30.24 ;
    END
  END xb[188]
  PIN xb[189]
    DIRECTION OUTPUT ;
    USE SIGNAL ;
    PORT
      LAYER M5 ;
        RECT  116.88 30.156 116.904 30.24 ;
    END
  END xb[189]
  PIN xb[18]
    DIRECTION OUTPUT ;
    USE SIGNAL ;
    PORT
      LAYER M5 ;
        RECT  92.256 30.156 92.28 30.24 ;
    END
  END xb[18]
  PIN xb[190]
    DIRECTION OUTPUT ;
    USE SIGNAL ;
    PORT
      LAYER M5 ;
        RECT  117.024 30.156 117.048 30.24 ;
    END
  END xb[190]
  PIN xb[191]
    DIRECTION OUTPUT ;
    USE SIGNAL ;
    PORT
      LAYER M5 ;
        RECT  117.168 30.156 117.192 30.24 ;
    END
  END xb[191]
  PIN xb[192]
    DIRECTION OUTPUT ;
    USE SIGNAL ;
    PORT
      LAYER M5 ;
        RECT  117.312 30.156 117.336 30.24 ;
    END
  END xb[192]
  PIN xb[193]
    DIRECTION OUTPUT ;
    USE SIGNAL ;
    PORT
      LAYER M5 ;
        RECT  117.456 30.156 117.48 30.24 ;
    END
  END xb[193]
  PIN xb[194]
    DIRECTION OUTPUT ;
    USE SIGNAL ;
    PORT
      LAYER M5 ;
        RECT  117.6 30.156 117.624 30.24 ;
    END
  END xb[194]
  PIN xb[195]
    DIRECTION OUTPUT ;
    USE SIGNAL ;
    PORT
      LAYER M5 ;
        RECT  117.744 30.156 117.768 30.24 ;
    END
  END xb[195]
  PIN xb[196]
    DIRECTION OUTPUT ;
    USE SIGNAL ;
    PORT
      LAYER M5 ;
        RECT  117.888 30.156 117.912 30.24 ;
    END
  END xb[196]
  PIN xb[197]
    DIRECTION OUTPUT ;
    USE SIGNAL ;
    PORT
      LAYER M5 ;
        RECT  118.032 30.156 118.056 30.24 ;
    END
  END xb[197]
  PIN xb[198]
    DIRECTION OUTPUT ;
    USE SIGNAL ;
    PORT
      LAYER M5 ;
        RECT  118.176 30.156 118.2 30.24 ;
    END
  END xb[198]
  PIN xb[199]
    DIRECTION OUTPUT ;
    USE SIGNAL ;
    PORT
      LAYER M5 ;
        RECT  118.32 30.156 118.344 30.24 ;
    END
  END xb[199]
  PIN xb[19]
    DIRECTION OUTPUT ;
    USE SIGNAL ;
    PORT
      LAYER M5 ;
        RECT  92.4 30.156 92.424 30.24 ;
    END
  END xb[19]
  PIN xb[1]
    DIRECTION OUTPUT ;
    USE SIGNAL ;
    PORT
      LAYER M5 ;
        RECT  89.808 30.156 89.832 30.24 ;
    END
  END xb[1]
  PIN xb[200]
    DIRECTION OUTPUT ;
    USE SIGNAL ;
    PORT
      LAYER M5 ;
        RECT  118.464 30.156 118.488 30.24 ;
    END
  END xb[200]
  PIN xb[201]
    DIRECTION OUTPUT ;
    USE SIGNAL ;
    PORT
      LAYER M5 ;
        RECT  118.608 30.156 118.632 30.24 ;
    END
  END xb[201]
  PIN xb[202]
    DIRECTION OUTPUT ;
    USE SIGNAL ;
    PORT
      LAYER M5 ;
        RECT  118.752 30.156 118.776 30.24 ;
    END
  END xb[202]
  PIN xb[203]
    DIRECTION OUTPUT ;
    USE SIGNAL ;
    PORT
      LAYER M5 ;
        RECT  118.896 30.156 118.92 30.24 ;
    END
  END xb[203]
  PIN xb[204]
    DIRECTION OUTPUT ;
    USE SIGNAL ;
    PORT
      LAYER M5 ;
        RECT  119.04 30.156 119.064 30.24 ;
    END
  END xb[204]
  PIN xb[205]
    DIRECTION OUTPUT ;
    USE SIGNAL ;
    PORT
      LAYER M5 ;
        RECT  119.184 30.156 119.208 30.24 ;
    END
  END xb[205]
  PIN xb[206]
    DIRECTION OUTPUT ;
    USE SIGNAL ;
    PORT
      LAYER M5 ;
        RECT  119.328 30.156 119.352 30.24 ;
    END
  END xb[206]
  PIN xb[207]
    DIRECTION OUTPUT ;
    USE SIGNAL ;
    PORT
      LAYER M5 ;
        RECT  119.472 30.156 119.496 30.24 ;
    END
  END xb[207]
  PIN xb[208]
    DIRECTION OUTPUT ;
    USE SIGNAL ;
    PORT
      LAYER M5 ;
        RECT  119.616 30.156 119.64 30.24 ;
    END
  END xb[208]
  PIN xb[209]
    DIRECTION OUTPUT ;
    USE SIGNAL ;
    PORT
      LAYER M5 ;
        RECT  119.76 30.156 119.784 30.24 ;
    END
  END xb[209]
  PIN xb[20]
    DIRECTION OUTPUT ;
    USE SIGNAL ;
    PORT
      LAYER M5 ;
        RECT  92.544 30.156 92.568 30.24 ;
    END
  END xb[20]
  PIN xb[210]
    DIRECTION OUTPUT ;
    USE SIGNAL ;
    PORT
      LAYER M5 ;
        RECT  119.904 30.156 119.928 30.24 ;
    END
  END xb[210]
  PIN xb[211]
    DIRECTION OUTPUT ;
    USE SIGNAL ;
    PORT
      LAYER M5 ;
        RECT  120.048 30.156 120.072 30.24 ;
    END
  END xb[211]
  PIN xb[212]
    DIRECTION OUTPUT ;
    USE SIGNAL ;
    PORT
      LAYER M5 ;
        RECT  120.192 30.156 120.216 30.24 ;
    END
  END xb[212]
  PIN xb[213]
    DIRECTION OUTPUT ;
    USE SIGNAL ;
    PORT
      LAYER M5 ;
        RECT  120.336 30.156 120.36 30.24 ;
    END
  END xb[213]
  PIN xb[214]
    DIRECTION OUTPUT ;
    USE SIGNAL ;
    PORT
      LAYER M5 ;
        RECT  120.48 30.156 120.504 30.24 ;
    END
  END xb[214]
  PIN xb[215]
    DIRECTION OUTPUT ;
    USE SIGNAL ;
    PORT
      LAYER M5 ;
        RECT  120.624 30.156 120.648 30.24 ;
    END
  END xb[215]
  PIN xb[216]
    DIRECTION OUTPUT ;
    USE SIGNAL ;
    PORT
      LAYER M5 ;
        RECT  120.768 30.156 120.792 30.24 ;
    END
  END xb[216]
  PIN xb[217]
    DIRECTION OUTPUT ;
    USE SIGNAL ;
    PORT
      LAYER M5 ;
        RECT  120.912 30.156 120.936 30.24 ;
    END
  END xb[217]
  PIN xb[218]
    DIRECTION OUTPUT ;
    USE SIGNAL ;
    PORT
      LAYER M5 ;
        RECT  121.056 30.156 121.08 30.24 ;
    END
  END xb[218]
  PIN xb[219]
    DIRECTION OUTPUT ;
    USE SIGNAL ;
    PORT
      LAYER M5 ;
        RECT  121.2 30.156 121.224 30.24 ;
    END
  END xb[219]
  PIN xb[21]
    DIRECTION OUTPUT ;
    USE SIGNAL ;
    PORT
      LAYER M5 ;
        RECT  92.688 30.156 92.712 30.24 ;
    END
  END xb[21]
  PIN xb[220]
    DIRECTION OUTPUT ;
    USE SIGNAL ;
    PORT
      LAYER M5 ;
        RECT  121.344 30.156 121.368 30.24 ;
    END
  END xb[220]
  PIN xb[221]
    DIRECTION OUTPUT ;
    USE SIGNAL ;
    PORT
      LAYER M5 ;
        RECT  121.488 30.156 121.512 30.24 ;
    END
  END xb[221]
  PIN xb[222]
    DIRECTION OUTPUT ;
    USE SIGNAL ;
    PORT
      LAYER M5 ;
        RECT  121.632 30.156 121.656 30.24 ;
    END
  END xb[222]
  PIN xb[223]
    DIRECTION OUTPUT ;
    USE SIGNAL ;
    PORT
      LAYER M5 ;
        RECT  121.776 30.156 121.8 30.24 ;
    END
  END xb[223]
  PIN xb[224]
    DIRECTION OUTPUT ;
    USE SIGNAL ;
    PORT
      LAYER M5 ;
        RECT  121.92 30.156 121.944 30.24 ;
    END
  END xb[224]
  PIN xb[225]
    DIRECTION OUTPUT ;
    USE SIGNAL ;
    PORT
      LAYER M5 ;
        RECT  122.064 30.156 122.088 30.24 ;
    END
  END xb[225]
  PIN xb[226]
    DIRECTION OUTPUT ;
    USE SIGNAL ;
    PORT
      LAYER M5 ;
        RECT  122.208 30.156 122.232 30.24 ;
    END
  END xb[226]
  PIN xb[227]
    DIRECTION OUTPUT ;
    USE SIGNAL ;
    PORT
      LAYER M5 ;
        RECT  122.352 30.156 122.376 30.24 ;
    END
  END xb[227]
  PIN xb[228]
    DIRECTION OUTPUT ;
    USE SIGNAL ;
    PORT
      LAYER M5 ;
        RECT  122.496 30.156 122.52 30.24 ;
    END
  END xb[228]
  PIN xb[229]
    DIRECTION OUTPUT ;
    USE SIGNAL ;
    PORT
      LAYER M5 ;
        RECT  122.64 30.156 122.664 30.24 ;
    END
  END xb[229]
  PIN xb[22]
    DIRECTION OUTPUT ;
    USE SIGNAL ;
    PORT
      LAYER M5 ;
        RECT  92.832 30.156 92.856 30.24 ;
    END
  END xb[22]
  PIN xb[230]
    DIRECTION OUTPUT ;
    USE SIGNAL ;
    PORT
      LAYER M5 ;
        RECT  122.784 30.156 122.808 30.24 ;
    END
  END xb[230]
  PIN xb[231]
    DIRECTION OUTPUT ;
    USE SIGNAL ;
    PORT
      LAYER M5 ;
        RECT  122.928 30.156 122.952 30.24 ;
    END
  END xb[231]
  PIN xb[232]
    DIRECTION OUTPUT ;
    USE SIGNAL ;
    PORT
      LAYER M5 ;
        RECT  123.072 30.156 123.096 30.24 ;
    END
  END xb[232]
  PIN xb[233]
    DIRECTION OUTPUT ;
    USE SIGNAL ;
    PORT
      LAYER M5 ;
        RECT  123.216 30.156 123.24 30.24 ;
    END
  END xb[233]
  PIN xb[234]
    DIRECTION OUTPUT ;
    USE SIGNAL ;
    PORT
      LAYER M5 ;
        RECT  123.36 30.156 123.384 30.24 ;
    END
  END xb[234]
  PIN xb[235]
    DIRECTION OUTPUT ;
    USE SIGNAL ;
    PORT
      LAYER M5 ;
        RECT  123.504 30.156 123.528 30.24 ;
    END
  END xb[235]
  PIN xb[236]
    DIRECTION OUTPUT ;
    USE SIGNAL ;
    PORT
      LAYER M5 ;
        RECT  123.648 30.156 123.672 30.24 ;
    END
  END xb[236]
  PIN xb[237]
    DIRECTION OUTPUT ;
    USE SIGNAL ;
    PORT
      LAYER M5 ;
        RECT  123.792 30.156 123.816 30.24 ;
    END
  END xb[237]
  PIN xb[238]
    DIRECTION OUTPUT ;
    USE SIGNAL ;
    PORT
      LAYER M5 ;
        RECT  123.936 30.156 123.96 30.24 ;
    END
  END xb[238]
  PIN xb[239]
    DIRECTION OUTPUT ;
    USE SIGNAL ;
    PORT
      LAYER M5 ;
        RECT  124.08 30.156 124.104 30.24 ;
    END
  END xb[239]
  PIN xb[23]
    DIRECTION OUTPUT ;
    USE SIGNAL ;
    PORT
      LAYER M5 ;
        RECT  92.976 30.156 93 30.24 ;
    END
  END xb[23]
  PIN xb[240]
    DIRECTION OUTPUT ;
    USE SIGNAL ;
    PORT
      LAYER M5 ;
        RECT  124.224 30.156 124.248 30.24 ;
    END
  END xb[240]
  PIN xb[241]
    DIRECTION OUTPUT ;
    USE SIGNAL ;
    PORT
      LAYER M5 ;
        RECT  124.368 30.156 124.392 30.24 ;
    END
  END xb[241]
  PIN xb[242]
    DIRECTION OUTPUT ;
    USE SIGNAL ;
    PORT
      LAYER M5 ;
        RECT  124.512 30.156 124.536 30.24 ;
    END
  END xb[242]
  PIN xb[243]
    DIRECTION OUTPUT ;
    USE SIGNAL ;
    PORT
      LAYER M5 ;
        RECT  124.656 30.156 124.68 30.24 ;
    END
  END xb[243]
  PIN xb[244]
    DIRECTION OUTPUT ;
    USE SIGNAL ;
    PORT
      LAYER M5 ;
        RECT  124.8 30.156 124.824 30.24 ;
    END
  END xb[244]
  PIN xb[245]
    DIRECTION OUTPUT ;
    USE SIGNAL ;
    PORT
      LAYER M5 ;
        RECT  124.944 30.156 124.968 30.24 ;
    END
  END xb[245]
  PIN xb[246]
    DIRECTION OUTPUT ;
    USE SIGNAL ;
    PORT
      LAYER M5 ;
        RECT  125.088 30.156 125.112 30.24 ;
    END
  END xb[246]
  PIN xb[247]
    DIRECTION OUTPUT ;
    USE SIGNAL ;
    PORT
      LAYER M5 ;
        RECT  125.232 30.156 125.256 30.24 ;
    END
  END xb[247]
  PIN xb[248]
    DIRECTION OUTPUT ;
    USE SIGNAL ;
    PORT
      LAYER M5 ;
        RECT  125.376 30.156 125.4 30.24 ;
    END
  END xb[248]
  PIN xb[249]
    DIRECTION OUTPUT ;
    USE SIGNAL ;
    PORT
      LAYER M5 ;
        RECT  125.52 30.156 125.544 30.24 ;
    END
  END xb[249]
  PIN xb[24]
    DIRECTION OUTPUT ;
    USE SIGNAL ;
    PORT
      LAYER M5 ;
        RECT  93.12 30.156 93.144 30.24 ;
    END
  END xb[24]
  PIN xb[250]
    DIRECTION OUTPUT ;
    USE SIGNAL ;
    PORT
      LAYER M5 ;
        RECT  125.664 30.156 125.688 30.24 ;
    END
  END xb[250]
  PIN xb[251]
    DIRECTION OUTPUT ;
    USE SIGNAL ;
    PORT
      LAYER M5 ;
        RECT  125.808 30.156 125.832 30.24 ;
    END
  END xb[251]
  PIN xb[252]
    DIRECTION OUTPUT ;
    USE SIGNAL ;
    PORT
      LAYER M5 ;
        RECT  125.952 30.156 125.976 30.24 ;
    END
  END xb[252]
  PIN xb[253]
    DIRECTION OUTPUT ;
    USE SIGNAL ;
    PORT
      LAYER M5 ;
        RECT  126.096 30.156 126.12 30.24 ;
    END
  END xb[253]
  PIN xb[254]
    DIRECTION OUTPUT ;
    USE SIGNAL ;
    PORT
      LAYER M5 ;
        RECT  126.24 30.156 126.264 30.24 ;
    END
  END xb[254]
  PIN xb[255]
    DIRECTION OUTPUT ;
    USE SIGNAL ;
    PORT
      LAYER M5 ;
        RECT  126.384 30.156 126.408 30.24 ;
    END
  END xb[255]
  PIN xb[256]
    DIRECTION OUTPUT ;
    USE SIGNAL ;
    PORT
      LAYER M5 ;
        RECT  126.528 30.156 126.552 30.24 ;
    END
  END xb[256]
  PIN xb[257]
    DIRECTION OUTPUT ;
    USE SIGNAL ;
    PORT
      LAYER M5 ;
        RECT  126.672 30.156 126.696 30.24 ;
    END
  END xb[257]
  PIN xb[258]
    DIRECTION OUTPUT ;
    USE SIGNAL ;
    PORT
      LAYER M5 ;
        RECT  126.816 30.156 126.84 30.24 ;
    END
  END xb[258]
  PIN xb[259]
    DIRECTION OUTPUT ;
    USE SIGNAL ;
    PORT
      LAYER M5 ;
        RECT  126.96 30.156 126.984 30.24 ;
    END
  END xb[259]
  PIN xb[25]
    DIRECTION OUTPUT ;
    USE SIGNAL ;
    PORT
      LAYER M5 ;
        RECT  93.264 30.156 93.288 30.24 ;
    END
  END xb[25]
  PIN xb[260]
    DIRECTION OUTPUT ;
    USE SIGNAL ;
    PORT
      LAYER M5 ;
        RECT  127.104 30.156 127.128 30.24 ;
    END
  END xb[260]
  PIN xb[261]
    DIRECTION OUTPUT ;
    USE SIGNAL ;
    PORT
      LAYER M5 ;
        RECT  127.248 30.156 127.272 30.24 ;
    END
  END xb[261]
  PIN xb[262]
    DIRECTION OUTPUT ;
    USE SIGNAL ;
    PORT
      LAYER M5 ;
        RECT  127.392 30.156 127.416 30.24 ;
    END
  END xb[262]
  PIN xb[263]
    DIRECTION OUTPUT ;
    USE SIGNAL ;
    PORT
      LAYER M5 ;
        RECT  127.536 30.156 127.56 30.24 ;
    END
  END xb[263]
  PIN xb[264]
    DIRECTION OUTPUT ;
    USE SIGNAL ;
    PORT
      LAYER M5 ;
        RECT  127.68 30.156 127.704 30.24 ;
    END
  END xb[264]
  PIN xb[265]
    DIRECTION OUTPUT ;
    USE SIGNAL ;
    PORT
      LAYER M5 ;
        RECT  127.824 30.156 127.848 30.24 ;
    END
  END xb[265]
  PIN xb[26]
    DIRECTION OUTPUT ;
    USE SIGNAL ;
    PORT
      LAYER M5 ;
        RECT  93.408 30.156 93.432 30.24 ;
    END
  END xb[26]
  PIN xb[27]
    DIRECTION OUTPUT ;
    USE SIGNAL ;
    PORT
      LAYER M5 ;
        RECT  93.552 30.156 93.576 30.24 ;
    END
  END xb[27]
  PIN xb[28]
    DIRECTION OUTPUT ;
    USE SIGNAL ;
    PORT
      LAYER M5 ;
        RECT  93.696 30.156 93.72 30.24 ;
    END
  END xb[28]
  PIN xb[29]
    DIRECTION OUTPUT ;
    USE SIGNAL ;
    PORT
      LAYER M5 ;
        RECT  93.84 30.156 93.864 30.24 ;
    END
  END xb[29]
  PIN xb[2]
    DIRECTION OUTPUT ;
    USE SIGNAL ;
    PORT
      LAYER M5 ;
        RECT  89.952 30.156 89.976 30.24 ;
    END
  END xb[2]
  PIN xb[30]
    DIRECTION OUTPUT ;
    USE SIGNAL ;
    PORT
      LAYER M5 ;
        RECT  93.984 30.156 94.008 30.24 ;
    END
  END xb[30]
  PIN xb[31]
    DIRECTION OUTPUT ;
    USE SIGNAL ;
    PORT
      LAYER M5 ;
        RECT  94.128 30.156 94.152 30.24 ;
    END
  END xb[31]
  PIN xb[32]
    DIRECTION OUTPUT ;
    USE SIGNAL ;
    PORT
      LAYER M5 ;
        RECT  94.272 30.156 94.296 30.24 ;
    END
  END xb[32]
  PIN xb[33]
    DIRECTION OUTPUT ;
    USE SIGNAL ;
    PORT
      LAYER M5 ;
        RECT  94.416 30.156 94.44 30.24 ;
    END
  END xb[33]
  PIN xb[34]
    DIRECTION OUTPUT ;
    USE SIGNAL ;
    PORT
      LAYER M5 ;
        RECT  94.56 30.156 94.584 30.24 ;
    END
  END xb[34]
  PIN xb[35]
    DIRECTION OUTPUT ;
    USE SIGNAL ;
    PORT
      LAYER M5 ;
        RECT  94.704 30.156 94.728 30.24 ;
    END
  END xb[35]
  PIN xb[36]
    DIRECTION OUTPUT ;
    USE SIGNAL ;
    PORT
      LAYER M5 ;
        RECT  94.848 30.156 94.872 30.24 ;
    END
  END xb[36]
  PIN xb[37]
    DIRECTION OUTPUT ;
    USE SIGNAL ;
    PORT
      LAYER M5 ;
        RECT  94.992 30.156 95.016 30.24 ;
    END
  END xb[37]
  PIN xb[38]
    DIRECTION OUTPUT ;
    USE SIGNAL ;
    PORT
      LAYER M5 ;
        RECT  95.136 30.156 95.16 30.24 ;
    END
  END xb[38]
  PIN xb[39]
    DIRECTION OUTPUT ;
    USE SIGNAL ;
    PORT
      LAYER M5 ;
        RECT  95.28 30.156 95.304 30.24 ;
    END
  END xb[39]
  PIN xb[3]
    DIRECTION OUTPUT ;
    USE SIGNAL ;
    PORT
      LAYER M5 ;
        RECT  90.096 30.156 90.12 30.24 ;
    END
  END xb[3]
  PIN xb[40]
    DIRECTION OUTPUT ;
    USE SIGNAL ;
    PORT
      LAYER M5 ;
        RECT  95.424 30.156 95.448 30.24 ;
    END
  END xb[40]
  PIN xb[41]
    DIRECTION OUTPUT ;
    USE SIGNAL ;
    PORT
      LAYER M5 ;
        RECT  95.568 30.156 95.592 30.24 ;
    END
  END xb[41]
  PIN xb[42]
    DIRECTION OUTPUT ;
    USE SIGNAL ;
    PORT
      LAYER M5 ;
        RECT  95.712 30.156 95.736 30.24 ;
    END
  END xb[42]
  PIN xb[43]
    DIRECTION OUTPUT ;
    USE SIGNAL ;
    PORT
      LAYER M5 ;
        RECT  95.856 30.156 95.88 30.24 ;
    END
  END xb[43]
  PIN xb[44]
    DIRECTION OUTPUT ;
    USE SIGNAL ;
    PORT
      LAYER M5 ;
        RECT  96 30.156 96.024 30.24 ;
    END
  END xb[44]
  PIN xb[45]
    DIRECTION OUTPUT ;
    USE SIGNAL ;
    PORT
      LAYER M5 ;
        RECT  96.144 30.156 96.168 30.24 ;
    END
  END xb[45]
  PIN xb[46]
    DIRECTION OUTPUT ;
    USE SIGNAL ;
    PORT
      LAYER M5 ;
        RECT  96.288 30.156 96.312 30.24 ;
    END
  END xb[46]
  PIN xb[47]
    DIRECTION OUTPUT ;
    USE SIGNAL ;
    PORT
      LAYER M5 ;
        RECT  96.432 30.156 96.456 30.24 ;
    END
  END xb[47]
  PIN xb[48]
    DIRECTION OUTPUT ;
    USE SIGNAL ;
    PORT
      LAYER M5 ;
        RECT  96.576 30.156 96.6 30.24 ;
    END
  END xb[48]
  PIN xb[49]
    DIRECTION OUTPUT ;
    USE SIGNAL ;
    PORT
      LAYER M5 ;
        RECT  96.72 30.156 96.744 30.24 ;
    END
  END xb[49]
  PIN xb[4]
    DIRECTION OUTPUT ;
    USE SIGNAL ;
    PORT
      LAYER M5 ;
        RECT  90.24 30.156 90.264 30.24 ;
    END
  END xb[4]
  PIN xb[50]
    DIRECTION OUTPUT ;
    USE SIGNAL ;
    PORT
      LAYER M5 ;
        RECT  96.864 30.156 96.888 30.24 ;
    END
  END xb[50]
  PIN xb[51]
    DIRECTION OUTPUT ;
    USE SIGNAL ;
    PORT
      LAYER M5 ;
        RECT  97.008 30.156 97.032 30.24 ;
    END
  END xb[51]
  PIN xb[52]
    DIRECTION OUTPUT ;
    USE SIGNAL ;
    PORT
      LAYER M5 ;
        RECT  97.152 30.156 97.176 30.24 ;
    END
  END xb[52]
  PIN xb[53]
    DIRECTION OUTPUT ;
    USE SIGNAL ;
    PORT
      LAYER M5 ;
        RECT  97.296 30.156 97.32 30.24 ;
    END
  END xb[53]
  PIN xb[54]
    DIRECTION OUTPUT ;
    USE SIGNAL ;
    PORT
      LAYER M5 ;
        RECT  97.44 30.156 97.464 30.24 ;
    END
  END xb[54]
  PIN xb[55]
    DIRECTION OUTPUT ;
    USE SIGNAL ;
    PORT
      LAYER M5 ;
        RECT  97.584 30.156 97.608 30.24 ;
    END
  END xb[55]
  PIN xb[56]
    DIRECTION OUTPUT ;
    USE SIGNAL ;
    PORT
      LAYER M5 ;
        RECT  97.728 30.156 97.752 30.24 ;
    END
  END xb[56]
  PIN xb[57]
    DIRECTION OUTPUT ;
    USE SIGNAL ;
    PORT
      LAYER M5 ;
        RECT  97.872 30.156 97.896 30.24 ;
    END
  END xb[57]
  PIN xb[58]
    DIRECTION OUTPUT ;
    USE SIGNAL ;
    PORT
      LAYER M5 ;
        RECT  98.016 30.156 98.04 30.24 ;
    END
  END xb[58]
  PIN xb[59]
    DIRECTION OUTPUT ;
    USE SIGNAL ;
    PORT
      LAYER M5 ;
        RECT  98.16 30.156 98.184 30.24 ;
    END
  END xb[59]
  PIN xb[5]
    DIRECTION OUTPUT ;
    USE SIGNAL ;
    PORT
      LAYER M5 ;
        RECT  90.384 30.156 90.408 30.24 ;
    END
  END xb[5]
  PIN xb[60]
    DIRECTION OUTPUT ;
    USE SIGNAL ;
    PORT
      LAYER M5 ;
        RECT  98.304 30.156 98.328 30.24 ;
    END
  END xb[60]
  PIN xb[61]
    DIRECTION OUTPUT ;
    USE SIGNAL ;
    PORT
      LAYER M5 ;
        RECT  98.448 30.156 98.472 30.24 ;
    END
  END xb[61]
  PIN xb[62]
    DIRECTION OUTPUT ;
    USE SIGNAL ;
    PORT
      LAYER M5 ;
        RECT  98.592 30.156 98.616 30.24 ;
    END
  END xb[62]
  PIN xb[63]
    DIRECTION OUTPUT ;
    USE SIGNAL ;
    PORT
      LAYER M5 ;
        RECT  98.736 30.156 98.76 30.24 ;
    END
  END xb[63]
  PIN xb[64]
    DIRECTION OUTPUT ;
    USE SIGNAL ;
    PORT
      LAYER M5 ;
        RECT  98.88 30.156 98.904 30.24 ;
    END
  END xb[64]
  PIN xb[65]
    DIRECTION OUTPUT ;
    USE SIGNAL ;
    PORT
      LAYER M5 ;
        RECT  99.024 30.156 99.048 30.24 ;
    END
  END xb[65]
  PIN xb[66]
    DIRECTION OUTPUT ;
    USE SIGNAL ;
    PORT
      LAYER M5 ;
        RECT  99.168 30.156 99.192 30.24 ;
    END
  END xb[66]
  PIN xb[67]
    DIRECTION OUTPUT ;
    USE SIGNAL ;
    PORT
      LAYER M5 ;
        RECT  99.312 30.156 99.336 30.24 ;
    END
  END xb[67]
  PIN xb[68]
    DIRECTION OUTPUT ;
    USE SIGNAL ;
    PORT
      LAYER M5 ;
        RECT  99.456 30.156 99.48 30.24 ;
    END
  END xb[68]
  PIN xb[69]
    DIRECTION OUTPUT ;
    USE SIGNAL ;
    PORT
      LAYER M5 ;
        RECT  99.6 30.156 99.624 30.24 ;
    END
  END xb[69]
  PIN xb[6]
    DIRECTION OUTPUT ;
    USE SIGNAL ;
    PORT
      LAYER M5 ;
        RECT  90.528 30.156 90.552 30.24 ;
    END
  END xb[6]
  PIN xb[70]
    DIRECTION OUTPUT ;
    USE SIGNAL ;
    PORT
      LAYER M5 ;
        RECT  99.744 30.156 99.768 30.24 ;
    END
  END xb[70]
  PIN xb[71]
    DIRECTION OUTPUT ;
    USE SIGNAL ;
    PORT
      LAYER M5 ;
        RECT  99.888 30.156 99.912 30.24 ;
    END
  END xb[71]
  PIN xb[72]
    DIRECTION OUTPUT ;
    USE SIGNAL ;
    PORT
      LAYER M5 ;
        RECT  100.032 30.156 100.056 30.24 ;
    END
  END xb[72]
  PIN xb[73]
    DIRECTION OUTPUT ;
    USE SIGNAL ;
    PORT
      LAYER M5 ;
        RECT  100.176 30.156 100.2 30.24 ;
    END
  END xb[73]
  PIN xb[74]
    DIRECTION OUTPUT ;
    USE SIGNAL ;
    PORT
      LAYER M5 ;
        RECT  100.32 30.156 100.344 30.24 ;
    END
  END xb[74]
  PIN xb[75]
    DIRECTION OUTPUT ;
    USE SIGNAL ;
    PORT
      LAYER M5 ;
        RECT  100.464 30.156 100.488 30.24 ;
    END
  END xb[75]
  PIN xb[76]
    DIRECTION OUTPUT ;
    USE SIGNAL ;
    PORT
      LAYER M5 ;
        RECT  100.608 30.156 100.632 30.24 ;
    END
  END xb[76]
  PIN xb[77]
    DIRECTION OUTPUT ;
    USE SIGNAL ;
    PORT
      LAYER M5 ;
        RECT  100.752 30.156 100.776 30.24 ;
    END
  END xb[77]
  PIN xb[78]
    DIRECTION OUTPUT ;
    USE SIGNAL ;
    PORT
      LAYER M5 ;
        RECT  100.896 30.156 100.92 30.24 ;
    END
  END xb[78]
  PIN xb[79]
    DIRECTION OUTPUT ;
    USE SIGNAL ;
    PORT
      LAYER M5 ;
        RECT  101.04 30.156 101.064 30.24 ;
    END
  END xb[79]
  PIN xb[7]
    DIRECTION OUTPUT ;
    USE SIGNAL ;
    PORT
      LAYER M5 ;
        RECT  90.672 30.156 90.696 30.24 ;
    END
  END xb[7]
  PIN xb[80]
    DIRECTION OUTPUT ;
    USE SIGNAL ;
    PORT
      LAYER M5 ;
        RECT  101.184 30.156 101.208 30.24 ;
    END
  END xb[80]
  PIN xb[81]
    DIRECTION OUTPUT ;
    USE SIGNAL ;
    PORT
      LAYER M5 ;
        RECT  101.328 30.156 101.352 30.24 ;
    END
  END xb[81]
  PIN xb[82]
    DIRECTION OUTPUT ;
    USE SIGNAL ;
    PORT
      LAYER M5 ;
        RECT  101.472 30.156 101.496 30.24 ;
    END
  END xb[82]
  PIN xb[83]
    DIRECTION OUTPUT ;
    USE SIGNAL ;
    PORT
      LAYER M5 ;
        RECT  101.616 30.156 101.64 30.24 ;
    END
  END xb[83]
  PIN xb[84]
    DIRECTION OUTPUT ;
    USE SIGNAL ;
    PORT
      LAYER M5 ;
        RECT  101.76 30.156 101.784 30.24 ;
    END
  END xb[84]
  PIN xb[85]
    DIRECTION OUTPUT ;
    USE SIGNAL ;
    PORT
      LAYER M5 ;
        RECT  101.904 30.156 101.928 30.24 ;
    END
  END xb[85]
  PIN xb[86]
    DIRECTION OUTPUT ;
    USE SIGNAL ;
    PORT
      LAYER M5 ;
        RECT  102.048 30.156 102.072 30.24 ;
    END
  END xb[86]
  PIN xb[87]
    DIRECTION OUTPUT ;
    USE SIGNAL ;
    PORT
      LAYER M5 ;
        RECT  102.192 30.156 102.216 30.24 ;
    END
  END xb[87]
  PIN xb[88]
    DIRECTION OUTPUT ;
    USE SIGNAL ;
    PORT
      LAYER M5 ;
        RECT  102.336 30.156 102.36 30.24 ;
    END
  END xb[88]
  PIN xb[89]
    DIRECTION OUTPUT ;
    USE SIGNAL ;
    PORT
      LAYER M5 ;
        RECT  102.48 30.156 102.504 30.24 ;
    END
  END xb[89]
  PIN xb[8]
    DIRECTION OUTPUT ;
    USE SIGNAL ;
    PORT
      LAYER M5 ;
        RECT  90.816 30.156 90.84 30.24 ;
    END
  END xb[8]
  PIN xb[90]
    DIRECTION OUTPUT ;
    USE SIGNAL ;
    PORT
      LAYER M5 ;
        RECT  102.624 30.156 102.648 30.24 ;
    END
  END xb[90]
  PIN xb[91]
    DIRECTION OUTPUT ;
    USE SIGNAL ;
    PORT
      LAYER M5 ;
        RECT  102.768 30.156 102.792 30.24 ;
    END
  END xb[91]
  PIN xb[92]
    DIRECTION OUTPUT ;
    USE SIGNAL ;
    PORT
      LAYER M5 ;
        RECT  102.912 30.156 102.936 30.24 ;
    END
  END xb[92]
  PIN xb[93]
    DIRECTION OUTPUT ;
    USE SIGNAL ;
    PORT
      LAYER M5 ;
        RECT  103.056 30.156 103.08 30.24 ;
    END
  END xb[93]
  PIN xb[94]
    DIRECTION OUTPUT ;
    USE SIGNAL ;
    PORT
      LAYER M5 ;
        RECT  103.2 30.156 103.224 30.24 ;
    END
  END xb[94]
  PIN xb[95]
    DIRECTION OUTPUT ;
    USE SIGNAL ;
    PORT
      LAYER M5 ;
        RECT  103.344 30.156 103.368 30.24 ;
    END
  END xb[95]
  PIN xb[96]
    DIRECTION OUTPUT ;
    USE SIGNAL ;
    PORT
      LAYER M5 ;
        RECT  103.488 30.156 103.512 30.24 ;
    END
  END xb[96]
  PIN xb[97]
    DIRECTION OUTPUT ;
    USE SIGNAL ;
    PORT
      LAYER M5 ;
        RECT  103.632 30.156 103.656 30.24 ;
    END
  END xb[97]
  PIN xb[98]
    DIRECTION OUTPUT ;
    USE SIGNAL ;
    PORT
      LAYER M5 ;
        RECT  103.776 30.156 103.8 30.24 ;
    END
  END xb[98]
  PIN xb[99]
    DIRECTION OUTPUT ;
    USE SIGNAL ;
    PORT
      LAYER M5 ;
        RECT  103.92 30.156 103.944 30.24 ;
    END
  END xb[99]
  PIN xb[9]
    DIRECTION OUTPUT ;
    USE SIGNAL ;
    PORT
      LAYER M5 ;
        RECT  90.96 30.156 90.984 30.24 ;
    END
  END xb[9]
  PIN xbi[0]
    DIRECTION INPUT ;
    USE SIGNAL ;
    PORT
      LAYER M5 ;
        RECT  92.16 0 92.184 0.084 ;
    END
  END xbi[0]
  PIN xbi[100]
    DIRECTION INPUT ;
    USE SIGNAL ;
    PORT
      LAYER M5 ;
        RECT  106.56 0 106.584 0.084 ;
    END
  END xbi[100]
  PIN xbi[101]
    DIRECTION INPUT ;
    USE SIGNAL ;
    PORT
      LAYER M5 ;
        RECT  106.704 0 106.728 0.084 ;
    END
  END xbi[101]
  PIN xbi[102]
    DIRECTION INPUT ;
    USE SIGNAL ;
    PORT
      LAYER M5 ;
        RECT  106.848 0 106.872 0.084 ;
    END
  END xbi[102]
  PIN xbi[103]
    DIRECTION INPUT ;
    USE SIGNAL ;
    PORT
      LAYER M5 ;
        RECT  106.992 0 107.016 0.084 ;
    END
  END xbi[103]
  PIN xbi[104]
    DIRECTION INPUT ;
    USE SIGNAL ;
    PORT
      LAYER M5 ;
        RECT  107.136 0 107.16 0.084 ;
    END
  END xbi[104]
  PIN xbi[105]
    DIRECTION INPUT ;
    USE SIGNAL ;
    PORT
      LAYER M5 ;
        RECT  107.28 0 107.304 0.084 ;
    END
  END xbi[105]
  PIN xbi[106]
    DIRECTION INPUT ;
    USE SIGNAL ;
    PORT
      LAYER M5 ;
        RECT  107.424 0 107.448 0.084 ;
    END
  END xbi[106]
  PIN xbi[107]
    DIRECTION INPUT ;
    USE SIGNAL ;
    PORT
      LAYER M5 ;
        RECT  107.568 0 107.592 0.084 ;
    END
  END xbi[107]
  PIN xbi[108]
    DIRECTION INPUT ;
    USE SIGNAL ;
    PORT
      LAYER M5 ;
        RECT  107.712 0 107.736 0.084 ;
    END
  END xbi[108]
  PIN xbi[109]
    DIRECTION INPUT ;
    USE SIGNAL ;
    PORT
      LAYER M5 ;
        RECT  107.856 0 107.88 0.084 ;
    END
  END xbi[109]
  PIN xbi[10]
    DIRECTION INPUT ;
    USE SIGNAL ;
    PORT
      LAYER M5 ;
        RECT  93.6 0 93.624 0.084 ;
    END
  END xbi[10]
  PIN xbi[110]
    DIRECTION INPUT ;
    USE SIGNAL ;
    PORT
      LAYER M5 ;
        RECT  108 0 108.024 0.084 ;
    END
  END xbi[110]
  PIN xbi[111]
    DIRECTION INPUT ;
    USE SIGNAL ;
    PORT
      LAYER M5 ;
        RECT  108.144 0 108.168 0.084 ;
    END
  END xbi[111]
  PIN xbi[112]
    DIRECTION INPUT ;
    USE SIGNAL ;
    PORT
      LAYER M5 ;
        RECT  108.288 0 108.312 0.084 ;
    END
  END xbi[112]
  PIN xbi[113]
    DIRECTION INPUT ;
    USE SIGNAL ;
    PORT
      LAYER M5 ;
        RECT  108.432 0 108.456 0.084 ;
    END
  END xbi[113]
  PIN xbi[114]
    DIRECTION INPUT ;
    USE SIGNAL ;
    PORT
      LAYER M5 ;
        RECT  108.576 0 108.6 0.084 ;
    END
  END xbi[114]
  PIN xbi[115]
    DIRECTION INPUT ;
    USE SIGNAL ;
    PORT
      LAYER M5 ;
        RECT  108.72 0 108.744 0.084 ;
    END
  END xbi[115]
  PIN xbi[116]
    DIRECTION INPUT ;
    USE SIGNAL ;
    PORT
      LAYER M5 ;
        RECT  108.864 0 108.888 0.084 ;
    END
  END xbi[116]
  PIN xbi[117]
    DIRECTION INPUT ;
    USE SIGNAL ;
    PORT
      LAYER M5 ;
        RECT  109.008 0 109.032 0.084 ;
    END
  END xbi[117]
  PIN xbi[118]
    DIRECTION INPUT ;
    USE SIGNAL ;
    PORT
      LAYER M5 ;
        RECT  109.152 0 109.176 0.084 ;
    END
  END xbi[118]
  PIN xbi[119]
    DIRECTION INPUT ;
    USE SIGNAL ;
    PORT
      LAYER M5 ;
        RECT  109.296 0 109.32 0.084 ;
    END
  END xbi[119]
  PIN xbi[11]
    DIRECTION INPUT ;
    USE SIGNAL ;
    PORT
      LAYER M5 ;
        RECT  93.744 0 93.768 0.084 ;
    END
  END xbi[11]
  PIN xbi[120]
    DIRECTION INPUT ;
    USE SIGNAL ;
    PORT
      LAYER M5 ;
        RECT  109.44 0 109.464 0.084 ;
    END
  END xbi[120]
  PIN xbi[121]
    DIRECTION INPUT ;
    USE SIGNAL ;
    PORT
      LAYER M5 ;
        RECT  109.584 0 109.608 0.084 ;
    END
  END xbi[121]
  PIN xbi[122]
    DIRECTION INPUT ;
    USE SIGNAL ;
    PORT
      LAYER M5 ;
        RECT  109.728 0 109.752 0.084 ;
    END
  END xbi[122]
  PIN xbi[123]
    DIRECTION INPUT ;
    USE SIGNAL ;
    PORT
      LAYER M5 ;
        RECT  109.872 0 109.896 0.084 ;
    END
  END xbi[123]
  PIN xbi[124]
    DIRECTION INPUT ;
    USE SIGNAL ;
    PORT
      LAYER M5 ;
        RECT  110.016 0 110.04 0.084 ;
    END
  END xbi[124]
  PIN xbi[125]
    DIRECTION INPUT ;
    USE SIGNAL ;
    PORT
      LAYER M5 ;
        RECT  110.16 0 110.184 0.084 ;
    END
  END xbi[125]
  PIN xbi[126]
    DIRECTION INPUT ;
    USE SIGNAL ;
    PORT
      LAYER M5 ;
        RECT  110.304 0 110.328 0.084 ;
    END
  END xbi[126]
  PIN xbi[127]
    DIRECTION INPUT ;
    USE SIGNAL ;
    PORT
      LAYER M5 ;
        RECT  110.448 0 110.472 0.084 ;
    END
  END xbi[127]
  PIN xbi[128]
    DIRECTION INPUT ;
    USE SIGNAL ;
    PORT
      LAYER M5 ;
        RECT  110.592 0 110.616 0.084 ;
    END
  END xbi[128]
  PIN xbi[129]
    DIRECTION INPUT ;
    USE SIGNAL ;
    PORT
      LAYER M5 ;
        RECT  110.736 0 110.76 0.084 ;
    END
  END xbi[129]
  PIN xbi[12]
    DIRECTION INPUT ;
    USE SIGNAL ;
    PORT
      LAYER M5 ;
        RECT  93.888 0 93.912 0.084 ;
    END
  END xbi[12]
  PIN xbi[130]
    DIRECTION INPUT ;
    USE SIGNAL ;
    PORT
      LAYER M5 ;
        RECT  110.88 0 110.904 0.084 ;
    END
  END xbi[130]
  PIN xbi[131]
    DIRECTION INPUT ;
    USE SIGNAL ;
    PORT
      LAYER M5 ;
        RECT  111.024 0 111.048 0.084 ;
    END
  END xbi[131]
  PIN xbi[132]
    DIRECTION INPUT ;
    USE SIGNAL ;
    PORT
      LAYER M5 ;
        RECT  111.168 0 111.192 0.084 ;
    END
  END xbi[132]
  PIN xbi[133]
    DIRECTION INPUT ;
    USE SIGNAL ;
    PORT
      LAYER M5 ;
        RECT  111.312 0 111.336 0.084 ;
    END
  END xbi[133]
  PIN xbi[134]
    DIRECTION INPUT ;
    USE SIGNAL ;
    PORT
      LAYER M5 ;
        RECT  111.456 0 111.48 0.084 ;
    END
  END xbi[134]
  PIN xbi[135]
    DIRECTION INPUT ;
    USE SIGNAL ;
    PORT
      LAYER M5 ;
        RECT  111.6 0 111.624 0.084 ;
    END
  END xbi[135]
  PIN xbi[136]
    DIRECTION INPUT ;
    USE SIGNAL ;
    PORT
      LAYER M5 ;
        RECT  111.744 0 111.768 0.084 ;
    END
  END xbi[136]
  PIN xbi[137]
    DIRECTION INPUT ;
    USE SIGNAL ;
    PORT
      LAYER M5 ;
        RECT  111.888 0 111.912 0.084 ;
    END
  END xbi[137]
  PIN xbi[138]
    DIRECTION INPUT ;
    USE SIGNAL ;
    PORT
      LAYER M5 ;
        RECT  112.032 0 112.056 0.084 ;
    END
  END xbi[138]
  PIN xbi[139]
    DIRECTION INPUT ;
    USE SIGNAL ;
    PORT
      LAYER M5 ;
        RECT  112.176 0 112.2 0.084 ;
    END
  END xbi[139]
  PIN xbi[13]
    DIRECTION INPUT ;
    USE SIGNAL ;
    PORT
      LAYER M5 ;
        RECT  94.032 0 94.056 0.084 ;
    END
  END xbi[13]
  PIN xbi[140]
    DIRECTION INPUT ;
    USE SIGNAL ;
    PORT
      LAYER M5 ;
        RECT  112.32 0 112.344 0.084 ;
    END
  END xbi[140]
  PIN xbi[141]
    DIRECTION INPUT ;
    USE SIGNAL ;
    PORT
      LAYER M5 ;
        RECT  112.464 0 112.488 0.084 ;
    END
  END xbi[141]
  PIN xbi[142]
    DIRECTION INPUT ;
    USE SIGNAL ;
    PORT
      LAYER M5 ;
        RECT  112.608 0 112.632 0.084 ;
    END
  END xbi[142]
  PIN xbi[143]
    DIRECTION INPUT ;
    USE SIGNAL ;
    PORT
      LAYER M5 ;
        RECT  112.752 0 112.776 0.084 ;
    END
  END xbi[143]
  PIN xbi[144]
    DIRECTION INPUT ;
    USE SIGNAL ;
    PORT
      LAYER M5 ;
        RECT  112.896 0 112.92 0.084 ;
    END
  END xbi[144]
  PIN xbi[145]
    DIRECTION INPUT ;
    USE SIGNAL ;
    PORT
      LAYER M5 ;
        RECT  113.04 0 113.064 0.084 ;
    END
  END xbi[145]
  PIN xbi[146]
    DIRECTION INPUT ;
    USE SIGNAL ;
    PORT
      LAYER M5 ;
        RECT  113.184 0 113.208 0.084 ;
    END
  END xbi[146]
  PIN xbi[147]
    DIRECTION INPUT ;
    USE SIGNAL ;
    PORT
      LAYER M5 ;
        RECT  113.328 0 113.352 0.084 ;
    END
  END xbi[147]
  PIN xbi[148]
    DIRECTION INPUT ;
    USE SIGNAL ;
    PORT
      LAYER M5 ;
        RECT  113.472 0 113.496 0.084 ;
    END
  END xbi[148]
  PIN xbi[149]
    DIRECTION INPUT ;
    USE SIGNAL ;
    PORT
      LAYER M5 ;
        RECT  113.616 0 113.64 0.084 ;
    END
  END xbi[149]
  PIN xbi[14]
    DIRECTION INPUT ;
    USE SIGNAL ;
    PORT
      LAYER M5 ;
        RECT  94.176 0 94.2 0.084 ;
    END
  END xbi[14]
  PIN xbi[150]
    DIRECTION INPUT ;
    USE SIGNAL ;
    PORT
      LAYER M5 ;
        RECT  113.76 0 113.784 0.084 ;
    END
  END xbi[150]
  PIN xbi[151]
    DIRECTION INPUT ;
    USE SIGNAL ;
    PORT
      LAYER M5 ;
        RECT  113.904 0 113.928 0.084 ;
    END
  END xbi[151]
  PIN xbi[152]
    DIRECTION INPUT ;
    USE SIGNAL ;
    PORT
      LAYER M5 ;
        RECT  114.048 0 114.072 0.084 ;
    END
  END xbi[152]
  PIN xbi[153]
    DIRECTION INPUT ;
    USE SIGNAL ;
    PORT
      LAYER M5 ;
        RECT  114.192 0 114.216 0.084 ;
    END
  END xbi[153]
  PIN xbi[154]
    DIRECTION INPUT ;
    USE SIGNAL ;
    PORT
      LAYER M5 ;
        RECT  114.336 0 114.36 0.084 ;
    END
  END xbi[154]
  PIN xbi[155]
    DIRECTION INPUT ;
    USE SIGNAL ;
    PORT
      LAYER M5 ;
        RECT  114.48 0 114.504 0.084 ;
    END
  END xbi[155]
  PIN xbi[156]
    DIRECTION INPUT ;
    USE SIGNAL ;
    PORT
      LAYER M5 ;
        RECT  114.624 0 114.648 0.084 ;
    END
  END xbi[156]
  PIN xbi[157]
    DIRECTION INPUT ;
    USE SIGNAL ;
    PORT
      LAYER M5 ;
        RECT  114.768 0 114.792 0.084 ;
    END
  END xbi[157]
  PIN xbi[158]
    DIRECTION INPUT ;
    USE SIGNAL ;
    PORT
      LAYER M5 ;
        RECT  114.912 0 114.936 0.084 ;
    END
  END xbi[158]
  PIN xbi[159]
    DIRECTION INPUT ;
    USE SIGNAL ;
    PORT
      LAYER M5 ;
        RECT  115.056 0 115.08 0.084 ;
    END
  END xbi[159]
  PIN xbi[15]
    DIRECTION INPUT ;
    USE SIGNAL ;
    PORT
      LAYER M5 ;
        RECT  94.32 0 94.344 0.084 ;
    END
  END xbi[15]
  PIN xbi[160]
    DIRECTION INPUT ;
    USE SIGNAL ;
    PORT
      LAYER M5 ;
        RECT  115.2 0 115.224 0.084 ;
    END
  END xbi[160]
  PIN xbi[161]
    DIRECTION INPUT ;
    USE SIGNAL ;
    PORT
      LAYER M5 ;
        RECT  115.344 0 115.368 0.084 ;
    END
  END xbi[161]
  PIN xbi[162]
    DIRECTION INPUT ;
    USE SIGNAL ;
    PORT
      LAYER M5 ;
        RECT  115.488 0 115.512 0.084 ;
    END
  END xbi[162]
  PIN xbi[163]
    DIRECTION INPUT ;
    USE SIGNAL ;
    PORT
      LAYER M5 ;
        RECT  115.632 0 115.656 0.084 ;
    END
  END xbi[163]
  PIN xbi[164]
    DIRECTION INPUT ;
    USE SIGNAL ;
    PORT
      LAYER M5 ;
        RECT  115.776 0 115.8 0.084 ;
    END
  END xbi[164]
  PIN xbi[165]
    DIRECTION INPUT ;
    USE SIGNAL ;
    PORT
      LAYER M5 ;
        RECT  115.92 0 115.944 0.084 ;
    END
  END xbi[165]
  PIN xbi[166]
    DIRECTION INPUT ;
    USE SIGNAL ;
    PORT
      LAYER M5 ;
        RECT  116.064 0 116.088 0.084 ;
    END
  END xbi[166]
  PIN xbi[167]
    DIRECTION INPUT ;
    USE SIGNAL ;
    PORT
      LAYER M5 ;
        RECT  116.208 0 116.232 0.084 ;
    END
  END xbi[167]
  PIN xbi[168]
    DIRECTION INPUT ;
    USE SIGNAL ;
    PORT
      LAYER M5 ;
        RECT  116.352 0 116.376 0.084 ;
    END
  END xbi[168]
  PIN xbi[169]
    DIRECTION INPUT ;
    USE SIGNAL ;
    PORT
      LAYER M5 ;
        RECT  116.496 0 116.52 0.084 ;
    END
  END xbi[169]
  PIN xbi[16]
    DIRECTION INPUT ;
    USE SIGNAL ;
    PORT
      LAYER M5 ;
        RECT  94.464 0 94.488 0.084 ;
    END
  END xbi[16]
  PIN xbi[170]
    DIRECTION INPUT ;
    USE SIGNAL ;
    PORT
      LAYER M5 ;
        RECT  116.64 0 116.664 0.084 ;
    END
  END xbi[170]
  PIN xbi[171]
    DIRECTION INPUT ;
    USE SIGNAL ;
    PORT
      LAYER M5 ;
        RECT  116.784 0 116.808 0.084 ;
    END
  END xbi[171]
  PIN xbi[172]
    DIRECTION INPUT ;
    USE SIGNAL ;
    PORT
      LAYER M5 ;
        RECT  116.928 0 116.952 0.084 ;
    END
  END xbi[172]
  PIN xbi[173]
    DIRECTION INPUT ;
    USE SIGNAL ;
    PORT
      LAYER M5 ;
        RECT  117.072 0 117.096 0.084 ;
    END
  END xbi[173]
  PIN xbi[174]
    DIRECTION INPUT ;
    USE SIGNAL ;
    PORT
      LAYER M5 ;
        RECT  117.216 0 117.24 0.084 ;
    END
  END xbi[174]
  PIN xbi[175]
    DIRECTION INPUT ;
    USE SIGNAL ;
    PORT
      LAYER M5 ;
        RECT  117.36 0 117.384 0.084 ;
    END
  END xbi[175]
  PIN xbi[176]
    DIRECTION INPUT ;
    USE SIGNAL ;
    PORT
      LAYER M5 ;
        RECT  117.504 0 117.528 0.084 ;
    END
  END xbi[176]
  PIN xbi[177]
    DIRECTION INPUT ;
    USE SIGNAL ;
    PORT
      LAYER M5 ;
        RECT  117.648 0 117.672 0.084 ;
    END
  END xbi[177]
  PIN xbi[178]
    DIRECTION INPUT ;
    USE SIGNAL ;
    PORT
      LAYER M5 ;
        RECT  117.792 0 117.816 0.084 ;
    END
  END xbi[178]
  PIN xbi[179]
    DIRECTION INPUT ;
    USE SIGNAL ;
    PORT
      LAYER M5 ;
        RECT  117.936 0 117.96 0.084 ;
    END
  END xbi[179]
  PIN xbi[17]
    DIRECTION INPUT ;
    USE SIGNAL ;
    PORT
      LAYER M5 ;
        RECT  94.608 0 94.632 0.084 ;
    END
  END xbi[17]
  PIN xbi[180]
    DIRECTION INPUT ;
    USE SIGNAL ;
    PORT
      LAYER M5 ;
        RECT  118.08 0 118.104 0.084 ;
    END
  END xbi[180]
  PIN xbi[181]
    DIRECTION INPUT ;
    USE SIGNAL ;
    PORT
      LAYER M5 ;
        RECT  118.224 0 118.248 0.084 ;
    END
  END xbi[181]
  PIN xbi[182]
    DIRECTION INPUT ;
    USE SIGNAL ;
    PORT
      LAYER M5 ;
        RECT  118.368 0 118.392 0.084 ;
    END
  END xbi[182]
  PIN xbi[183]
    DIRECTION INPUT ;
    USE SIGNAL ;
    PORT
      LAYER M5 ;
        RECT  118.512 0 118.536 0.084 ;
    END
  END xbi[183]
  PIN xbi[184]
    DIRECTION INPUT ;
    USE SIGNAL ;
    PORT
      LAYER M5 ;
        RECT  118.656 0 118.68 0.084 ;
    END
  END xbi[184]
  PIN xbi[185]
    DIRECTION INPUT ;
    USE SIGNAL ;
    PORT
      LAYER M5 ;
        RECT  118.8 0 118.824 0.084 ;
    END
  END xbi[185]
  PIN xbi[186]
    DIRECTION INPUT ;
    USE SIGNAL ;
    PORT
      LAYER M5 ;
        RECT  118.944 0 118.968 0.084 ;
    END
  END xbi[186]
  PIN xbi[187]
    DIRECTION INPUT ;
    USE SIGNAL ;
    PORT
      LAYER M5 ;
        RECT  119.088 0 119.112 0.084 ;
    END
  END xbi[187]
  PIN xbi[188]
    DIRECTION INPUT ;
    USE SIGNAL ;
    PORT
      LAYER M5 ;
        RECT  119.232 0 119.256 0.084 ;
    END
  END xbi[188]
  PIN xbi[189]
    DIRECTION INPUT ;
    USE SIGNAL ;
    PORT
      LAYER M5 ;
        RECT  119.376 0 119.4 0.084 ;
    END
  END xbi[189]
  PIN xbi[18]
    DIRECTION INPUT ;
    USE SIGNAL ;
    PORT
      LAYER M5 ;
        RECT  94.752 0 94.776 0.084 ;
    END
  END xbi[18]
  PIN xbi[190]
    DIRECTION INPUT ;
    USE SIGNAL ;
    PORT
      LAYER M5 ;
        RECT  119.52 0 119.544 0.084 ;
    END
  END xbi[190]
  PIN xbi[191]
    DIRECTION INPUT ;
    USE SIGNAL ;
    PORT
      LAYER M5 ;
        RECT  119.664 0 119.688 0.084 ;
    END
  END xbi[191]
  PIN xbi[192]
    DIRECTION INPUT ;
    USE SIGNAL ;
    PORT
      LAYER M5 ;
        RECT  119.808 0 119.832 0.084 ;
    END
  END xbi[192]
  PIN xbi[193]
    DIRECTION INPUT ;
    USE SIGNAL ;
    PORT
      LAYER M5 ;
        RECT  119.952 0 119.976 0.084 ;
    END
  END xbi[193]
  PIN xbi[194]
    DIRECTION INPUT ;
    USE SIGNAL ;
    PORT
      LAYER M5 ;
        RECT  120.096 0 120.12 0.084 ;
    END
  END xbi[194]
  PIN xbi[195]
    DIRECTION INPUT ;
    USE SIGNAL ;
    PORT
      LAYER M5 ;
        RECT  120.24 0 120.264 0.084 ;
    END
  END xbi[195]
  PIN xbi[196]
    DIRECTION INPUT ;
    USE SIGNAL ;
    PORT
      LAYER M5 ;
        RECT  120.384 0 120.408 0.084 ;
    END
  END xbi[196]
  PIN xbi[197]
    DIRECTION INPUT ;
    USE SIGNAL ;
    PORT
      LAYER M5 ;
        RECT  120.528 0 120.552 0.084 ;
    END
  END xbi[197]
  PIN xbi[198]
    DIRECTION INPUT ;
    USE SIGNAL ;
    PORT
      LAYER M5 ;
        RECT  120.672 0 120.696 0.084 ;
    END
  END xbi[198]
  PIN xbi[199]
    DIRECTION INPUT ;
    USE SIGNAL ;
    PORT
      LAYER M5 ;
        RECT  120.816 0 120.84 0.084 ;
    END
  END xbi[199]
  PIN xbi[19]
    DIRECTION INPUT ;
    USE SIGNAL ;
    PORT
      LAYER M5 ;
        RECT  94.896 0 94.92 0.084 ;
    END
  END xbi[19]
  PIN xbi[1]
    DIRECTION INPUT ;
    USE SIGNAL ;
    PORT
      LAYER M5 ;
        RECT  92.304 0 92.328 0.084 ;
    END
  END xbi[1]
  PIN xbi[200]
    DIRECTION INPUT ;
    USE SIGNAL ;
    PORT
      LAYER M5 ;
        RECT  120.96 0 120.984 0.084 ;
    END
  END xbi[200]
  PIN xbi[201]
    DIRECTION INPUT ;
    USE SIGNAL ;
    PORT
      LAYER M5 ;
        RECT  121.104 0 121.128 0.084 ;
    END
  END xbi[201]
  PIN xbi[202]
    DIRECTION INPUT ;
    USE SIGNAL ;
    PORT
      LAYER M5 ;
        RECT  121.248 0 121.272 0.084 ;
    END
  END xbi[202]
  PIN xbi[203]
    DIRECTION INPUT ;
    USE SIGNAL ;
    PORT
      LAYER M5 ;
        RECT  121.392 0 121.416 0.084 ;
    END
  END xbi[203]
  PIN xbi[204]
    DIRECTION INPUT ;
    USE SIGNAL ;
    PORT
      LAYER M5 ;
        RECT  121.536 0 121.56 0.084 ;
    END
  END xbi[204]
  PIN xbi[205]
    DIRECTION INPUT ;
    USE SIGNAL ;
    PORT
      LAYER M5 ;
        RECT  121.68 0 121.704 0.084 ;
    END
  END xbi[205]
  PIN xbi[206]
    DIRECTION INPUT ;
    USE SIGNAL ;
    PORT
      LAYER M5 ;
        RECT  121.824 0 121.848 0.084 ;
    END
  END xbi[206]
  PIN xbi[207]
    DIRECTION INPUT ;
    USE SIGNAL ;
    PORT
      LAYER M5 ;
        RECT  121.968 0 121.992 0.084 ;
    END
  END xbi[207]
  PIN xbi[208]
    DIRECTION INPUT ;
    USE SIGNAL ;
    PORT
      LAYER M5 ;
        RECT  122.112 0 122.136 0.084 ;
    END
  END xbi[208]
  PIN xbi[209]
    DIRECTION INPUT ;
    USE SIGNAL ;
    PORT
      LAYER M5 ;
        RECT  122.256 0 122.28 0.084 ;
    END
  END xbi[209]
  PIN xbi[20]
    DIRECTION INPUT ;
    USE SIGNAL ;
    PORT
      LAYER M5 ;
        RECT  95.04 0 95.064 0.084 ;
    END
  END xbi[20]
  PIN xbi[210]
    DIRECTION INPUT ;
    USE SIGNAL ;
    PORT
      LAYER M5 ;
        RECT  122.4 0 122.424 0.084 ;
    END
  END xbi[210]
  PIN xbi[211]
    DIRECTION INPUT ;
    USE SIGNAL ;
    PORT
      LAYER M5 ;
        RECT  122.544 0 122.568 0.084 ;
    END
  END xbi[211]
  PIN xbi[212]
    DIRECTION INPUT ;
    USE SIGNAL ;
    PORT
      LAYER M5 ;
        RECT  122.688 0 122.712 0.084 ;
    END
  END xbi[212]
  PIN xbi[213]
    DIRECTION INPUT ;
    USE SIGNAL ;
    PORT
      LAYER M5 ;
        RECT  122.832 0 122.856 0.084 ;
    END
  END xbi[213]
  PIN xbi[214]
    DIRECTION INPUT ;
    USE SIGNAL ;
    PORT
      LAYER M5 ;
        RECT  122.976 0 123 0.084 ;
    END
  END xbi[214]
  PIN xbi[215]
    DIRECTION INPUT ;
    USE SIGNAL ;
    PORT
      LAYER M5 ;
        RECT  123.12 0 123.144 0.084 ;
    END
  END xbi[215]
  PIN xbi[216]
    DIRECTION INPUT ;
    USE SIGNAL ;
    PORT
      LAYER M5 ;
        RECT  123.264 0 123.288 0.084 ;
    END
  END xbi[216]
  PIN xbi[217]
    DIRECTION INPUT ;
    USE SIGNAL ;
    PORT
      LAYER M5 ;
        RECT  123.408 0 123.432 0.084 ;
    END
  END xbi[217]
  PIN xbi[218]
    DIRECTION INPUT ;
    USE SIGNAL ;
    PORT
      LAYER M5 ;
        RECT  123.552 0 123.576 0.084 ;
    END
  END xbi[218]
  PIN xbi[219]
    DIRECTION INPUT ;
    USE SIGNAL ;
    PORT
      LAYER M5 ;
        RECT  123.696 0 123.72 0.084 ;
    END
  END xbi[219]
  PIN xbi[21]
    DIRECTION INPUT ;
    USE SIGNAL ;
    PORT
      LAYER M5 ;
        RECT  95.184 0 95.208 0.084 ;
    END
  END xbi[21]
  PIN xbi[220]
    DIRECTION INPUT ;
    USE SIGNAL ;
    PORT
      LAYER M5 ;
        RECT  123.84 0 123.864 0.084 ;
    END
  END xbi[220]
  PIN xbi[221]
    DIRECTION INPUT ;
    USE SIGNAL ;
    PORT
      LAYER M5 ;
        RECT  123.984 0 124.008 0.084 ;
    END
  END xbi[221]
  PIN xbi[222]
    DIRECTION INPUT ;
    USE SIGNAL ;
    PORT
      LAYER M5 ;
        RECT  124.128 0 124.152 0.084 ;
    END
  END xbi[222]
  PIN xbi[223]
    DIRECTION INPUT ;
    USE SIGNAL ;
    PORT
      LAYER M5 ;
        RECT  124.272 0 124.296 0.084 ;
    END
  END xbi[223]
  PIN xbi[224]
    DIRECTION INPUT ;
    USE SIGNAL ;
    PORT
      LAYER M5 ;
        RECT  124.416 0 124.44 0.084 ;
    END
  END xbi[224]
  PIN xbi[225]
    DIRECTION INPUT ;
    USE SIGNAL ;
    PORT
      LAYER M5 ;
        RECT  124.56 0 124.584 0.084 ;
    END
  END xbi[225]
  PIN xbi[226]
    DIRECTION INPUT ;
    USE SIGNAL ;
    PORT
      LAYER M5 ;
        RECT  124.704 0 124.728 0.084 ;
    END
  END xbi[226]
  PIN xbi[227]
    DIRECTION INPUT ;
    USE SIGNAL ;
    PORT
      LAYER M5 ;
        RECT  124.848 0 124.872 0.084 ;
    END
  END xbi[227]
  PIN xbi[228]
    DIRECTION INPUT ;
    USE SIGNAL ;
    PORT
      LAYER M5 ;
        RECT  124.992 0 125.016 0.084 ;
    END
  END xbi[228]
  PIN xbi[229]
    DIRECTION INPUT ;
    USE SIGNAL ;
    PORT
      LAYER M5 ;
        RECT  125.136 0 125.16 0.084 ;
    END
  END xbi[229]
  PIN xbi[22]
    DIRECTION INPUT ;
    USE SIGNAL ;
    PORT
      LAYER M5 ;
        RECT  95.328 0 95.352 0.084 ;
    END
  END xbi[22]
  PIN xbi[230]
    DIRECTION INPUT ;
    USE SIGNAL ;
    PORT
      LAYER M5 ;
        RECT  125.28 0 125.304 0.084 ;
    END
  END xbi[230]
  PIN xbi[231]
    DIRECTION INPUT ;
    USE SIGNAL ;
    PORT
      LAYER M5 ;
        RECT  125.424 0 125.448 0.084 ;
    END
  END xbi[231]
  PIN xbi[232]
    DIRECTION INPUT ;
    USE SIGNAL ;
    PORT
      LAYER M5 ;
        RECT  125.568 0 125.592 0.084 ;
    END
  END xbi[232]
  PIN xbi[233]
    DIRECTION INPUT ;
    USE SIGNAL ;
    PORT
      LAYER M5 ;
        RECT  125.712 0 125.736 0.084 ;
    END
  END xbi[233]
  PIN xbi[234]
    DIRECTION INPUT ;
    USE SIGNAL ;
    PORT
      LAYER M5 ;
        RECT  125.856 0 125.88 0.084 ;
    END
  END xbi[234]
  PIN xbi[235]
    DIRECTION INPUT ;
    USE SIGNAL ;
    PORT
      LAYER M5 ;
        RECT  126 0 126.024 0.084 ;
    END
  END xbi[235]
  PIN xbi[236]
    DIRECTION INPUT ;
    USE SIGNAL ;
    PORT
      LAYER M5 ;
        RECT  126.144 0 126.168 0.084 ;
    END
  END xbi[236]
  PIN xbi[237]
    DIRECTION INPUT ;
    USE SIGNAL ;
    PORT
      LAYER M5 ;
        RECT  126.288 0 126.312 0.084 ;
    END
  END xbi[237]
  PIN xbi[238]
    DIRECTION INPUT ;
    USE SIGNAL ;
    PORT
      LAYER M5 ;
        RECT  126.432 0 126.456 0.084 ;
    END
  END xbi[238]
  PIN xbi[239]
    DIRECTION INPUT ;
    USE SIGNAL ;
    PORT
      LAYER M5 ;
        RECT  126.576 0 126.6 0.084 ;
    END
  END xbi[239]
  PIN xbi[23]
    DIRECTION INPUT ;
    USE SIGNAL ;
    PORT
      LAYER M5 ;
        RECT  95.472 0 95.496 0.084 ;
    END
  END xbi[23]
  PIN xbi[240]
    DIRECTION INPUT ;
    USE SIGNAL ;
    PORT
      LAYER M5 ;
        RECT  126.72 0 126.744 0.084 ;
    END
  END xbi[240]
  PIN xbi[241]
    DIRECTION INPUT ;
    USE SIGNAL ;
    PORT
      LAYER M5 ;
        RECT  126.864 0 126.888 0.084 ;
    END
  END xbi[241]
  PIN xbi[242]
    DIRECTION INPUT ;
    USE SIGNAL ;
    PORT
      LAYER M5 ;
        RECT  127.008 0 127.032 0.084 ;
    END
  END xbi[242]
  PIN xbi[243]
    DIRECTION INPUT ;
    USE SIGNAL ;
    PORT
      LAYER M5 ;
        RECT  127.152 0 127.176 0.084 ;
    END
  END xbi[243]
  PIN xbi[244]
    DIRECTION INPUT ;
    USE SIGNAL ;
    PORT
      LAYER M5 ;
        RECT  127.296 0 127.32 0.084 ;
    END
  END xbi[244]
  PIN xbi[245]
    DIRECTION INPUT ;
    USE SIGNAL ;
    PORT
      LAYER M5 ;
        RECT  127.44 0 127.464 0.084 ;
    END
  END xbi[245]
  PIN xbi[246]
    DIRECTION INPUT ;
    USE SIGNAL ;
    PORT
      LAYER M5 ;
        RECT  127.584 0 127.608 0.084 ;
    END
  END xbi[246]
  PIN xbi[247]
    DIRECTION INPUT ;
    USE SIGNAL ;
    PORT
      LAYER M5 ;
        RECT  127.728 0 127.752 0.084 ;
    END
  END xbi[247]
  PIN xbi[248]
    DIRECTION INPUT ;
    USE SIGNAL ;
    PORT
      LAYER M5 ;
        RECT  127.872 0 127.896 0.084 ;
    END
  END xbi[248]
  PIN xbi[249]
    DIRECTION INPUT ;
    USE SIGNAL ;
    PORT
      LAYER M5 ;
        RECT  128.016 0 128.04 0.084 ;
    END
  END xbi[249]
  PIN xbi[24]
    DIRECTION INPUT ;
    USE SIGNAL ;
    PORT
      LAYER M5 ;
        RECT  95.616 0 95.64 0.084 ;
    END
  END xbi[24]
  PIN xbi[250]
    DIRECTION INPUT ;
    USE SIGNAL ;
    PORT
      LAYER M5 ;
        RECT  128.16 0 128.184 0.084 ;
    END
  END xbi[250]
  PIN xbi[251]
    DIRECTION INPUT ;
    USE SIGNAL ;
    PORT
      LAYER M5 ;
        RECT  128.304 0 128.328 0.084 ;
    END
  END xbi[251]
  PIN xbi[252]
    DIRECTION INPUT ;
    USE SIGNAL ;
    PORT
      LAYER M5 ;
        RECT  128.448 0 128.472 0.084 ;
    END
  END xbi[252]
  PIN xbi[253]
    DIRECTION INPUT ;
    USE SIGNAL ;
    PORT
      LAYER M5 ;
        RECT  128.592 0 128.616 0.084 ;
    END
  END xbi[253]
  PIN xbi[254]
    DIRECTION INPUT ;
    USE SIGNAL ;
    PORT
      LAYER M5 ;
        RECT  128.736 0 128.76 0.084 ;
    END
  END xbi[254]
  PIN xbi[255]
    DIRECTION INPUT ;
    USE SIGNAL ;
    PORT
      LAYER M5 ;
        RECT  128.88 0 128.904 0.084 ;
    END
  END xbi[255]
  PIN xbi[256]
    DIRECTION INPUT ;
    USE SIGNAL ;
    PORT
      LAYER M5 ;
        RECT  129.024 0 129.048 0.084 ;
    END
  END xbi[256]
  PIN xbi[257]
    DIRECTION INPUT ;
    USE SIGNAL ;
    PORT
      LAYER M5 ;
        RECT  129.168 0 129.192 0.084 ;
    END
  END xbi[257]
  PIN xbi[258]
    DIRECTION INPUT ;
    USE SIGNAL ;
    PORT
      LAYER M5 ;
        RECT  129.312 0 129.336 0.084 ;
    END
  END xbi[258]
  PIN xbi[259]
    DIRECTION INPUT ;
    USE SIGNAL ;
    PORT
      LAYER M5 ;
        RECT  129.456 0 129.48 0.084 ;
    END
  END xbi[259]
  PIN xbi[25]
    DIRECTION INPUT ;
    USE SIGNAL ;
    PORT
      LAYER M5 ;
        RECT  95.76 0 95.784 0.084 ;
    END
  END xbi[25]
  PIN xbi[260]
    DIRECTION INPUT ;
    USE SIGNAL ;
    PORT
      LAYER M5 ;
        RECT  129.6 0 129.624 0.084 ;
    END
  END xbi[260]
  PIN xbi[261]
    DIRECTION INPUT ;
    USE SIGNAL ;
    PORT
      LAYER M5 ;
        RECT  129.744 0 129.768 0.084 ;
    END
  END xbi[261]
  PIN xbi[262]
    DIRECTION INPUT ;
    USE SIGNAL ;
    PORT
      LAYER M5 ;
        RECT  129.888 0 129.912 0.084 ;
    END
  END xbi[262]
  PIN xbi[263]
    DIRECTION INPUT ;
    USE SIGNAL ;
    PORT
      LAYER M5 ;
        RECT  130.032 0 130.056 0.084 ;
    END
  END xbi[263]
  PIN xbi[264]
    DIRECTION INPUT ;
    USE SIGNAL ;
    PORT
      LAYER M5 ;
        RECT  130.176 0 130.2 0.084 ;
    END
  END xbi[264]
  PIN xbi[265]
    DIRECTION INPUT ;
    USE SIGNAL ;
    PORT
      LAYER M5 ;
        RECT  130.32 0 130.344 0.084 ;
    END
  END xbi[265]
  PIN xbi[26]
    DIRECTION INPUT ;
    USE SIGNAL ;
    PORT
      LAYER M5 ;
        RECT  95.904 0 95.928 0.084 ;
    END
  END xbi[26]
  PIN xbi[27]
    DIRECTION INPUT ;
    USE SIGNAL ;
    PORT
      LAYER M5 ;
        RECT  96.048 0 96.072 0.084 ;
    END
  END xbi[27]
  PIN xbi[28]
    DIRECTION INPUT ;
    USE SIGNAL ;
    PORT
      LAYER M5 ;
        RECT  96.192 0 96.216 0.084 ;
    END
  END xbi[28]
  PIN xbi[29]
    DIRECTION INPUT ;
    USE SIGNAL ;
    PORT
      LAYER M5 ;
        RECT  96.336 0 96.36 0.084 ;
    END
  END xbi[29]
  PIN xbi[2]
    DIRECTION INPUT ;
    USE SIGNAL ;
    PORT
      LAYER M5 ;
        RECT  92.448 0 92.472 0.084 ;
    END
  END xbi[2]
  PIN xbi[30]
    DIRECTION INPUT ;
    USE SIGNAL ;
    PORT
      LAYER M5 ;
        RECT  96.48 0 96.504 0.084 ;
    END
  END xbi[30]
  PIN xbi[31]
    DIRECTION INPUT ;
    USE SIGNAL ;
    PORT
      LAYER M5 ;
        RECT  96.624 0 96.648 0.084 ;
    END
  END xbi[31]
  PIN xbi[32]
    DIRECTION INPUT ;
    USE SIGNAL ;
    PORT
      LAYER M5 ;
        RECT  96.768 0 96.792 0.084 ;
    END
  END xbi[32]
  PIN xbi[33]
    DIRECTION INPUT ;
    USE SIGNAL ;
    PORT
      LAYER M5 ;
        RECT  96.912 0 96.936 0.084 ;
    END
  END xbi[33]
  PIN xbi[34]
    DIRECTION INPUT ;
    USE SIGNAL ;
    PORT
      LAYER M5 ;
        RECT  97.056 0 97.08 0.084 ;
    END
  END xbi[34]
  PIN xbi[35]
    DIRECTION INPUT ;
    USE SIGNAL ;
    PORT
      LAYER M5 ;
        RECT  97.2 0 97.224 0.084 ;
    END
  END xbi[35]
  PIN xbi[36]
    DIRECTION INPUT ;
    USE SIGNAL ;
    PORT
      LAYER M5 ;
        RECT  97.344 0 97.368 0.084 ;
    END
  END xbi[36]
  PIN xbi[37]
    DIRECTION INPUT ;
    USE SIGNAL ;
    PORT
      LAYER M5 ;
        RECT  97.488 0 97.512 0.084 ;
    END
  END xbi[37]
  PIN xbi[38]
    DIRECTION INPUT ;
    USE SIGNAL ;
    PORT
      LAYER M5 ;
        RECT  97.632 0 97.656 0.084 ;
    END
  END xbi[38]
  PIN xbi[39]
    DIRECTION INPUT ;
    USE SIGNAL ;
    PORT
      LAYER M5 ;
        RECT  97.776 0 97.8 0.084 ;
    END
  END xbi[39]
  PIN xbi[3]
    DIRECTION INPUT ;
    USE SIGNAL ;
    PORT
      LAYER M5 ;
        RECT  92.592 0 92.616 0.084 ;
    END
  END xbi[3]
  PIN xbi[40]
    DIRECTION INPUT ;
    USE SIGNAL ;
    PORT
      LAYER M5 ;
        RECT  97.92 0 97.944 0.084 ;
    END
  END xbi[40]
  PIN xbi[41]
    DIRECTION INPUT ;
    USE SIGNAL ;
    PORT
      LAYER M5 ;
        RECT  98.064 0 98.088 0.084 ;
    END
  END xbi[41]
  PIN xbi[42]
    DIRECTION INPUT ;
    USE SIGNAL ;
    PORT
      LAYER M5 ;
        RECT  98.208 0 98.232 0.084 ;
    END
  END xbi[42]
  PIN xbi[43]
    DIRECTION INPUT ;
    USE SIGNAL ;
    PORT
      LAYER M5 ;
        RECT  98.352 0 98.376 0.084 ;
    END
  END xbi[43]
  PIN xbi[44]
    DIRECTION INPUT ;
    USE SIGNAL ;
    PORT
      LAYER M5 ;
        RECT  98.496 0 98.52 0.084 ;
    END
  END xbi[44]
  PIN xbi[45]
    DIRECTION INPUT ;
    USE SIGNAL ;
    PORT
      LAYER M5 ;
        RECT  98.64 0 98.664 0.084 ;
    END
  END xbi[45]
  PIN xbi[46]
    DIRECTION INPUT ;
    USE SIGNAL ;
    PORT
      LAYER M5 ;
        RECT  98.784 0 98.808 0.084 ;
    END
  END xbi[46]
  PIN xbi[47]
    DIRECTION INPUT ;
    USE SIGNAL ;
    PORT
      LAYER M5 ;
        RECT  98.928 0 98.952 0.084 ;
    END
  END xbi[47]
  PIN xbi[48]
    DIRECTION INPUT ;
    USE SIGNAL ;
    PORT
      LAYER M5 ;
        RECT  99.072 0 99.096 0.084 ;
    END
  END xbi[48]
  PIN xbi[49]
    DIRECTION INPUT ;
    USE SIGNAL ;
    PORT
      LAYER M5 ;
        RECT  99.216 0 99.24 0.084 ;
    END
  END xbi[49]
  PIN xbi[4]
    DIRECTION INPUT ;
    USE SIGNAL ;
    PORT
      LAYER M5 ;
        RECT  92.736 0 92.76 0.084 ;
    END
  END xbi[4]
  PIN xbi[50]
    DIRECTION INPUT ;
    USE SIGNAL ;
    PORT
      LAYER M5 ;
        RECT  99.36 0 99.384 0.084 ;
    END
  END xbi[50]
  PIN xbi[51]
    DIRECTION INPUT ;
    USE SIGNAL ;
    PORT
      LAYER M5 ;
        RECT  99.504 0 99.528 0.084 ;
    END
  END xbi[51]
  PIN xbi[52]
    DIRECTION INPUT ;
    USE SIGNAL ;
    PORT
      LAYER M5 ;
        RECT  99.648 0 99.672 0.084 ;
    END
  END xbi[52]
  PIN xbi[53]
    DIRECTION INPUT ;
    USE SIGNAL ;
    PORT
      LAYER M5 ;
        RECT  99.792 0 99.816 0.084 ;
    END
  END xbi[53]
  PIN xbi[54]
    DIRECTION INPUT ;
    USE SIGNAL ;
    PORT
      LAYER M5 ;
        RECT  99.936 0 99.96 0.084 ;
    END
  END xbi[54]
  PIN xbi[55]
    DIRECTION INPUT ;
    USE SIGNAL ;
    PORT
      LAYER M5 ;
        RECT  100.08 0 100.104 0.084 ;
    END
  END xbi[55]
  PIN xbi[56]
    DIRECTION INPUT ;
    USE SIGNAL ;
    PORT
      LAYER M5 ;
        RECT  100.224 0 100.248 0.084 ;
    END
  END xbi[56]
  PIN xbi[57]
    DIRECTION INPUT ;
    USE SIGNAL ;
    PORT
      LAYER M5 ;
        RECT  100.368 0 100.392 0.084 ;
    END
  END xbi[57]
  PIN xbi[58]
    DIRECTION INPUT ;
    USE SIGNAL ;
    PORT
      LAYER M5 ;
        RECT  100.512 0 100.536 0.084 ;
    END
  END xbi[58]
  PIN xbi[59]
    DIRECTION INPUT ;
    USE SIGNAL ;
    PORT
      LAYER M5 ;
        RECT  100.656 0 100.68 0.084 ;
    END
  END xbi[59]
  PIN xbi[5]
    DIRECTION INPUT ;
    USE SIGNAL ;
    PORT
      LAYER M5 ;
        RECT  92.88 0 92.904 0.084 ;
    END
  END xbi[5]
  PIN xbi[60]
    DIRECTION INPUT ;
    USE SIGNAL ;
    PORT
      LAYER M5 ;
        RECT  100.8 0 100.824 0.084 ;
    END
  END xbi[60]
  PIN xbi[61]
    DIRECTION INPUT ;
    USE SIGNAL ;
    PORT
      LAYER M5 ;
        RECT  100.944 0 100.968 0.084 ;
    END
  END xbi[61]
  PIN xbi[62]
    DIRECTION INPUT ;
    USE SIGNAL ;
    PORT
      LAYER M5 ;
        RECT  101.088 0 101.112 0.084 ;
    END
  END xbi[62]
  PIN xbi[63]
    DIRECTION INPUT ;
    USE SIGNAL ;
    PORT
      LAYER M5 ;
        RECT  101.232 0 101.256 0.084 ;
    END
  END xbi[63]
  PIN xbi[64]
    DIRECTION INPUT ;
    USE SIGNAL ;
    PORT
      LAYER M5 ;
        RECT  101.376 0 101.4 0.084 ;
    END
  END xbi[64]
  PIN xbi[65]
    DIRECTION INPUT ;
    USE SIGNAL ;
    PORT
      LAYER M5 ;
        RECT  101.52 0 101.544 0.084 ;
    END
  END xbi[65]
  PIN xbi[66]
    DIRECTION INPUT ;
    USE SIGNAL ;
    PORT
      LAYER M5 ;
        RECT  101.664 0 101.688 0.084 ;
    END
  END xbi[66]
  PIN xbi[67]
    DIRECTION INPUT ;
    USE SIGNAL ;
    PORT
      LAYER M5 ;
        RECT  101.808 0 101.832 0.084 ;
    END
  END xbi[67]
  PIN xbi[68]
    DIRECTION INPUT ;
    USE SIGNAL ;
    PORT
      LAYER M5 ;
        RECT  101.952 0 101.976 0.084 ;
    END
  END xbi[68]
  PIN xbi[69]
    DIRECTION INPUT ;
    USE SIGNAL ;
    PORT
      LAYER M5 ;
        RECT  102.096 0 102.12 0.084 ;
    END
  END xbi[69]
  PIN xbi[6]
    DIRECTION INPUT ;
    USE SIGNAL ;
    PORT
      LAYER M5 ;
        RECT  93.024 0 93.048 0.084 ;
    END
  END xbi[6]
  PIN xbi[70]
    DIRECTION INPUT ;
    USE SIGNAL ;
    PORT
      LAYER M5 ;
        RECT  102.24 0 102.264 0.084 ;
    END
  END xbi[70]
  PIN xbi[71]
    DIRECTION INPUT ;
    USE SIGNAL ;
    PORT
      LAYER M5 ;
        RECT  102.384 0 102.408 0.084 ;
    END
  END xbi[71]
  PIN xbi[72]
    DIRECTION INPUT ;
    USE SIGNAL ;
    PORT
      LAYER M5 ;
        RECT  102.528 0 102.552 0.084 ;
    END
  END xbi[72]
  PIN xbi[73]
    DIRECTION INPUT ;
    USE SIGNAL ;
    PORT
      LAYER M5 ;
        RECT  102.672 0 102.696 0.084 ;
    END
  END xbi[73]
  PIN xbi[74]
    DIRECTION INPUT ;
    USE SIGNAL ;
    PORT
      LAYER M5 ;
        RECT  102.816 0 102.84 0.084 ;
    END
  END xbi[74]
  PIN xbi[75]
    DIRECTION INPUT ;
    USE SIGNAL ;
    PORT
      LAYER M5 ;
        RECT  102.96 0 102.984 0.084 ;
    END
  END xbi[75]
  PIN xbi[76]
    DIRECTION INPUT ;
    USE SIGNAL ;
    PORT
      LAYER M5 ;
        RECT  103.104 0 103.128 0.084 ;
    END
  END xbi[76]
  PIN xbi[77]
    DIRECTION INPUT ;
    USE SIGNAL ;
    PORT
      LAYER M5 ;
        RECT  103.248 0 103.272 0.084 ;
    END
  END xbi[77]
  PIN xbi[78]
    DIRECTION INPUT ;
    USE SIGNAL ;
    PORT
      LAYER M5 ;
        RECT  103.392 0 103.416 0.084 ;
    END
  END xbi[78]
  PIN xbi[79]
    DIRECTION INPUT ;
    USE SIGNAL ;
    PORT
      LAYER M5 ;
        RECT  103.536 0 103.56 0.084 ;
    END
  END xbi[79]
  PIN xbi[7]
    DIRECTION INPUT ;
    USE SIGNAL ;
    PORT
      LAYER M5 ;
        RECT  93.168 0 93.192 0.084 ;
    END
  END xbi[7]
  PIN xbi[80]
    DIRECTION INPUT ;
    USE SIGNAL ;
    PORT
      LAYER M5 ;
        RECT  103.68 0 103.704 0.084 ;
    END
  END xbi[80]
  PIN xbi[81]
    DIRECTION INPUT ;
    USE SIGNAL ;
    PORT
      LAYER M5 ;
        RECT  103.824 0 103.848 0.084 ;
    END
  END xbi[81]
  PIN xbi[82]
    DIRECTION INPUT ;
    USE SIGNAL ;
    PORT
      LAYER M5 ;
        RECT  103.968 0 103.992 0.084 ;
    END
  END xbi[82]
  PIN xbi[83]
    DIRECTION INPUT ;
    USE SIGNAL ;
    PORT
      LAYER M5 ;
        RECT  104.112 0 104.136 0.084 ;
    END
  END xbi[83]
  PIN xbi[84]
    DIRECTION INPUT ;
    USE SIGNAL ;
    PORT
      LAYER M5 ;
        RECT  104.256 0 104.28 0.084 ;
    END
  END xbi[84]
  PIN xbi[85]
    DIRECTION INPUT ;
    USE SIGNAL ;
    PORT
      LAYER M5 ;
        RECT  104.4 0 104.424 0.084 ;
    END
  END xbi[85]
  PIN xbi[86]
    DIRECTION INPUT ;
    USE SIGNAL ;
    PORT
      LAYER M5 ;
        RECT  104.544 0 104.568 0.084 ;
    END
  END xbi[86]
  PIN xbi[87]
    DIRECTION INPUT ;
    USE SIGNAL ;
    PORT
      LAYER M5 ;
        RECT  104.688 0 104.712 0.084 ;
    END
  END xbi[87]
  PIN xbi[88]
    DIRECTION INPUT ;
    USE SIGNAL ;
    PORT
      LAYER M5 ;
        RECT  104.832 0 104.856 0.084 ;
    END
  END xbi[88]
  PIN xbi[89]
    DIRECTION INPUT ;
    USE SIGNAL ;
    PORT
      LAYER M5 ;
        RECT  104.976 0 105 0.084 ;
    END
  END xbi[89]
  PIN xbi[8]
    DIRECTION INPUT ;
    USE SIGNAL ;
    PORT
      LAYER M5 ;
        RECT  93.312 0 93.336 0.084 ;
    END
  END xbi[8]
  PIN xbi[90]
    DIRECTION INPUT ;
    USE SIGNAL ;
    PORT
      LAYER M5 ;
        RECT  105.12 0 105.144 0.084 ;
    END
  END xbi[90]
  PIN xbi[91]
    DIRECTION INPUT ;
    USE SIGNAL ;
    PORT
      LAYER M5 ;
        RECT  105.264 0 105.288 0.084 ;
    END
  END xbi[91]
  PIN xbi[92]
    DIRECTION INPUT ;
    USE SIGNAL ;
    PORT
      LAYER M5 ;
        RECT  105.408 0 105.432 0.084 ;
    END
  END xbi[92]
  PIN xbi[93]
    DIRECTION INPUT ;
    USE SIGNAL ;
    PORT
      LAYER M5 ;
        RECT  105.552 0 105.576 0.084 ;
    END
  END xbi[93]
  PIN xbi[94]
    DIRECTION INPUT ;
    USE SIGNAL ;
    PORT
      LAYER M5 ;
        RECT  105.696 0 105.72 0.084 ;
    END
  END xbi[94]
  PIN xbi[95]
    DIRECTION INPUT ;
    USE SIGNAL ;
    PORT
      LAYER M5 ;
        RECT  105.84 0 105.864 0.084 ;
    END
  END xbi[95]
  PIN xbi[96]
    DIRECTION INPUT ;
    USE SIGNAL ;
    PORT
      LAYER M5 ;
        RECT  105.984 0 106.008 0.084 ;
    END
  END xbi[96]
  PIN xbi[97]
    DIRECTION INPUT ;
    USE SIGNAL ;
    PORT
      LAYER M5 ;
        RECT  106.128 0 106.152 0.084 ;
    END
  END xbi[97]
  PIN xbi[98]
    DIRECTION INPUT ;
    USE SIGNAL ;
    PORT
      LAYER M5 ;
        RECT  106.272 0 106.296 0.084 ;
    END
  END xbi[98]
  PIN xbi[99]
    DIRECTION INPUT ;
    USE SIGNAL ;
    PORT
      LAYER M5 ;
        RECT  106.416 0 106.44 0.084 ;
    END
  END xbi[99]
  PIN xbi[9]
    DIRECTION INPUT ;
    USE SIGNAL ;
    PORT
      LAYER M5 ;
        RECT  93.456 0 93.48 0.084 ;
    END
  END xbi[9]
  PIN VDD
    DIRECTION INOUT ;
    USE POWER ;
    PORT
      LAYER M5 ;
        RECT  169.992 2.151 170.112 28.089 ;
        RECT  167.292 2.151 167.412 28.089 ;
        RECT  164.592 2.151 164.712 28.089 ;
        RECT  161.892 2.151 162.012 28.089 ;
        RECT  159.192 2.151 159.312 28.089 ;
        RECT  156.492 2.151 156.612 28.089 ;
        RECT  153.792 2.151 153.912 28.089 ;
        RECT  151.092 2.151 151.212 28.089 ;
        RECT  148.392 2.151 148.512 28.089 ;
        RECT  145.692 2.151 145.812 28.089 ;
        RECT  142.992 2.151 143.112 28.089 ;
        RECT  140.292 2.151 140.412 28.089 ;
        RECT  137.592 2.151 137.712 28.089 ;
        RECT  134.892 2.151 135.012 28.089 ;
        RECT  132.192 2.151 132.312 28.089 ;
        RECT  129.492 2.151 129.612 28.089 ;
        RECT  126.792 2.151 126.912 28.089 ;
        RECT  124.092 2.151 124.212 28.089 ;
        RECT  121.392 2.151 121.512 28.089 ;
        RECT  118.692 2.151 118.812 28.089 ;
        RECT  115.992 2.151 116.112 28.089 ;
        RECT  113.292 2.151 113.412 28.089 ;
        RECT  110.592 2.151 110.712 28.089 ;
        RECT  107.892 2.151 108.012 28.089 ;
        RECT  105.192 2.151 105.312 28.089 ;
        RECT  102.492 2.151 102.612 28.089 ;
        RECT  99.792 2.151 99.912 28.089 ;
        RECT  97.092 2.151 97.212 28.089 ;
        RECT  94.392 2.151 94.512 28.089 ;
        RECT  91.692 2.151 91.812 28.089 ;
        RECT  88.992 2.151 89.112 28.089 ;
        RECT  86.292 2.151 86.412 28.089 ;
        RECT  83.592 2.151 83.712 28.089 ;
        RECT  80.892 2.151 81.012 28.089 ;
        RECT  78.192 2.151 78.312 28.089 ;
        RECT  75.492 2.151 75.612 28.089 ;
        RECT  72.792 2.151 72.912 28.089 ;
        RECT  70.092 2.151 70.212 28.089 ;
        RECT  67.392 2.151 67.512 28.089 ;
        RECT  64.692 2.151 64.812 28.089 ;
        RECT  61.992 2.151 62.112 28.089 ;
        RECT  59.292 2.151 59.412 28.089 ;
        RECT  56.592 2.151 56.712 28.089 ;
        RECT  53.892 2.151 54.012 28.089 ;
        RECT  51.192 2.151 51.312 28.089 ;
        RECT  48.492 2.151 48.612 28.089 ;
        RECT  45.792 2.151 45.912 28.089 ;
        RECT  43.092 2.151 43.212 28.089 ;
        RECT  40.392 2.151 40.512 28.089 ;
        RECT  37.692 2.151 37.812 28.089 ;
        RECT  34.992 2.151 35.112 28.089 ;
        RECT  32.292 2.151 32.412 28.089 ;
        RECT  29.592 2.151 29.712 28.089 ;
        RECT  26.892 2.151 27.012 28.089 ;
        RECT  24.192 2.151 24.312 28.089 ;
        RECT  21.492 2.151 21.612 28.089 ;
        RECT  18.792 2.151 18.912 28.089 ;
        RECT  16.092 2.151 16.212 28.089 ;
        RECT  13.392 2.151 13.512 28.089 ;
        RECT  10.692 2.151 10.812 28.089 ;
        RECT  7.992 2.151 8.112 28.089 ;
        RECT  5.292 2.151 5.412 28.089 ;
        RECT  2.592 2.151 2.712 28.089 ;
    END
  END VDD
  PIN VSS
    DIRECTION INOUT ;
    USE GROUND ;
    PORT
      LAYER M5 ;
        RECT  169.8 2.137 169.92 28.103 ;
        RECT  167.1 2.137 167.22 28.103 ;
        RECT  164.4 2.137 164.52 28.103 ;
        RECT  161.7 2.137 161.82 28.103 ;
        RECT  159 2.137 159.12 28.103 ;
        RECT  156.3 2.137 156.42 28.103 ;
        RECT  153.6 2.137 153.72 28.103 ;
        RECT  150.9 2.137 151.02 28.103 ;
        RECT  148.2 2.137 148.32 28.103 ;
        RECT  145.5 2.137 145.62 28.103 ;
        RECT  142.8 2.137 142.92 28.103 ;
        RECT  140.1 2.137 140.22 28.103 ;
        RECT  137.4 2.137 137.52 28.103 ;
        RECT  134.7 2.137 134.82 28.103 ;
        RECT  132 2.137 132.12 28.103 ;
        RECT  129.3 2.137 129.42 28.103 ;
        RECT  126.6 2.137 126.72 28.103 ;
        RECT  123.9 2.137 124.02 28.103 ;
        RECT  121.2 2.137 121.32 28.103 ;
        RECT  118.5 2.137 118.62 28.103 ;
        RECT  115.8 2.137 115.92 28.103 ;
        RECT  113.1 2.137 113.22 28.103 ;
        RECT  110.4 2.137 110.52 28.103 ;
        RECT  107.7 2.137 107.82 28.103 ;
        RECT  105 2.137 105.12 28.103 ;
        RECT  102.3 2.137 102.42 28.103 ;
        RECT  99.6 2.137 99.72 28.103 ;
        RECT  96.9 2.137 97.02 28.103 ;
        RECT  94.2 2.137 94.32 28.103 ;
        RECT  91.5 2.137 91.62 28.103 ;
        RECT  88.8 2.137 88.92 28.103 ;
        RECT  86.1 2.137 86.22 28.103 ;
        RECT  83.4 2.137 83.52 28.103 ;
        RECT  80.7 2.137 80.82 28.103 ;
        RECT  78 2.137 78.12 28.103 ;
        RECT  75.3 2.137 75.42 28.103 ;
        RECT  72.6 2.137 72.72 28.103 ;
        RECT  69.9 2.137 70.02 28.103 ;
        RECT  67.2 2.137 67.32 28.103 ;
        RECT  64.5 2.137 64.62 28.103 ;
        RECT  61.8 2.137 61.92 28.103 ;
        RECT  59.1 2.137 59.22 28.103 ;
        RECT  56.4 2.137 56.52 28.103 ;
        RECT  53.7 2.137 53.82 28.103 ;
        RECT  51 2.137 51.12 28.103 ;
        RECT  48.3 2.137 48.42 28.103 ;
        RECT  45.6 2.137 45.72 28.103 ;
        RECT  42.9 2.137 43.02 28.103 ;
        RECT  40.2 2.137 40.32 28.103 ;
        RECT  37.5 2.137 37.62 28.103 ;
        RECT  34.8 2.137 34.92 28.103 ;
        RECT  32.1 2.137 32.22 28.103 ;
        RECT  29.4 2.137 29.52 28.103 ;
        RECT  26.7 2.137 26.82 28.103 ;
        RECT  24 2.137 24.12 28.103 ;
        RECT  21.3 2.137 21.42 28.103 ;
        RECT  18.6 2.137 18.72 28.103 ;
        RECT  15.9 2.137 16.02 28.103 ;
        RECT  13.2 2.137 13.32 28.103 ;
        RECT  10.5 2.137 10.62 28.103 ;
        RECT  7.8 2.137 7.92 28.103 ;
        RECT  5.1 2.137 5.22 28.103 ;
        RECT  2.4 2.137 2.52 28.103 ;
    END
  END VSS
  # OT_OBS_CLOSED layer=M5 d_um=1.536 added=153
  OBS
    LAYER RVTN ;
     RECT  2.16 2.16 170.64 2.295 ;
     RECT  2.16 2.565 170.64 2.835 ;
     RECT  2.16 3.105 170.64 3.375 ;
     RECT  2.16 3.645 170.64 3.915 ;
     RECT  2.16 4.185 170.64 4.455 ;
     RECT  2.16 4.725 170.64 4.995 ;
     RECT  2.16 5.265 170.64 5.535 ;
     RECT  2.16 5.805 170.64 6.075 ;
     RECT  2.16 6.345 170.64 6.615 ;
     RECT  2.16 6.885 170.64 7.155 ;
     RECT  2.16 7.425 170.64 7.695 ;
     RECT  2.16 7.965 170.64 8.235 ;
     RECT  2.16 8.505 170.64 8.775 ;
     RECT  2.16 9.045 170.64 9.315 ;
     RECT  2.16 9.585 170.64 9.855 ;
     RECT  2.16 10.125 170.64 10.395 ;
     RECT  2.16 10.665 170.64 10.935 ;
     RECT  2.16 11.205 170.64 11.475 ;
     RECT  2.16 11.745 170.64 12.015 ;
     RECT  2.16 12.285 170.64 12.555 ;
     RECT  2.16 12.825 170.64 13.095 ;
     RECT  2.16 13.365 170.64 13.635 ;
     RECT  2.16 13.905 170.64 14.175 ;
     RECT  2.16 14.445 170.64 14.715 ;
     RECT  2.16 14.985 170.64 15.255 ;
     RECT  2.16 15.525 170.64 15.795 ;
     RECT  2.16 16.065 170.64 16.335 ;
     RECT  2.16 16.605 170.64 16.875 ;
     RECT  2.16 17.145 170.64 17.415 ;
     RECT  2.16 17.685 170.64 17.955 ;
     RECT  2.16 18.225 170.64 18.495 ;
     RECT  2.16 18.765 170.64 19.035 ;
     RECT  2.16 19.305 170.64 19.575 ;
     RECT  2.16 19.845 170.64 20.115 ;
     RECT  2.16 20.385 170.64 20.655 ;
     RECT  2.16 20.925 170.64 21.195 ;
     RECT  2.16 21.465 170.64 21.735 ;
     RECT  2.16 22.005 170.64 22.275 ;
     RECT  2.16 22.545 170.64 22.815 ;
     RECT  2.16 23.085 170.64 23.355 ;
     RECT  2.16 23.625 170.64 23.895 ;
     RECT  2.16 24.165 170.64 24.435 ;
     RECT  2.16 24.705 170.64 24.975 ;
     RECT  2.16 25.245 170.64 25.515 ;
     RECT  2.16 25.785 170.64 26.055 ;
     RECT  2.16 26.325 170.64 26.595 ;
     RECT  2.16 26.865 170.64 27.135 ;
     RECT  2.16 27.405 170.64 27.675 ;
     RECT  2.16 27.945 170.64 28.08 ;
    LAYER RVTP ;
     RECT  2.16 2.295 170.64 2.565 ;
     RECT  2.16 2.835 170.64 3.105 ;
     RECT  2.16 3.375 170.64 3.645 ;
     RECT  2.16 3.915 170.64 4.185 ;
     RECT  2.16 4.455 170.64 4.725 ;
     RECT  2.16 4.995 170.64 5.265 ;
     RECT  2.16 5.535 170.64 5.805 ;
     RECT  2.16 6.075 170.64 6.345 ;
     RECT  2.16 6.615 170.64 6.885 ;
     RECT  2.16 7.155 170.64 7.425 ;
     RECT  2.16 7.695 170.64 7.965 ;
     RECT  2.16 8.235 170.64 8.505 ;
     RECT  2.16 8.775 170.64 9.045 ;
     RECT  2.16 9.315 170.64 9.585 ;
     RECT  2.16 9.855 170.64 10.125 ;
     RECT  2.16 10.395 170.64 10.665 ;
     RECT  2.16 10.935 170.64 11.205 ;
     RECT  2.16 11.475 170.64 11.745 ;
     RECT  2.16 12.015 170.64 12.285 ;
     RECT  2.16 12.555 170.64 12.825 ;
     RECT  2.16 13.095 170.64 13.365 ;
     RECT  2.16 13.635 170.64 13.905 ;
     RECT  2.16 14.175 170.64 14.445 ;
     RECT  2.16 14.715 170.64 14.985 ;
     RECT  2.16 15.255 170.64 15.525 ;
     RECT  2.16 15.795 170.64 16.065 ;
     RECT  2.16 16.335 170.64 16.605 ;
     RECT  2.16 16.875 170.64 17.145 ;
     RECT  2.16 17.415 170.64 17.685 ;
     RECT  2.16 17.955 170.64 18.225 ;
     RECT  2.16 18.495 170.64 18.765 ;
     RECT  2.16 19.035 170.64 19.305 ;
     RECT  2.16 19.575 170.64 19.845 ;
     RECT  2.16 20.115 170.64 20.385 ;
     RECT  2.16 20.655 170.64 20.925 ;
     RECT  2.16 21.195 170.64 21.465 ;
     RECT  2.16 21.735 170.64 22.005 ;
     RECT  2.16 22.275 170.64 22.545 ;
     RECT  2.16 22.815 170.64 23.085 ;
     RECT  2.16 23.355 170.64 23.625 ;
     RECT  2.16 23.895 170.64 24.165 ;
     RECT  2.16 24.435 170.64 24.705 ;
     RECT  2.16 24.975 170.64 25.245 ;
     RECT  2.16 25.515 170.64 25.785 ;
     RECT  2.16 26.055 170.64 26.325 ;
     RECT  2.16 26.595 170.64 26.865 ;
     RECT  2.16 27.135 170.64 27.405 ;
     RECT  2.16 27.675 170.64 27.945 ;
    LAYER M1 ;
     RECT  2.16 2.151 170.64 28.089 ;
    LAYER M2 ;
     RECT  2.16 2.151 60.115 28.089 ;
     RECT  60.115 1.881 60.187 28.089 ;
     RECT  62.707 29.034 62.987 29.052 ;
     RECT  60.187 1.836 90.643 28.089 ;
     RECT  90.643 1.8 93.047 28.089 ;
     RECT  92.983 29.034 93.155 29.052 ;
     RECT  93.047 1.836 93.991 28.089 ;
     RECT  93.991 1.8 94.675 28.089 ;
     RECT  94.675 1.152 94.811 28.089 ;
     RECT  94.811 1.8 95.683 28.089 ;
     RECT  95.683 1.728 97.655 28.089 ;
     RECT  97.655 1.836 106.735 28.089 ;
     RECT  108.103 29.034 108.311 29.052 ;
     RECT  106.735 1.8 109.319 28.089 ;
     RECT  109.319 1.836 115.339 28.089 ;
     RECT  115.339 1.8 118.031 28.089 ;
     RECT  118.031 1.836 132.799 28.089 ;
     RECT  132.799 1.8 138.523 28.089 ;
     RECT  138.523 1.764 144.743 28.089 ;
     RECT  144.743 1.8 152.779 28.089 ;
     RECT  152.779 1.728 157.991 28.089 ;
     RECT  157.991 1.764 166.451 28.089 ;
     RECT  166.451 1.8 169.475 28.089 ;
     RECT  169.475 1.926 169.799 28.089 ;
     RECT  169.799 2.151 170.64 28.089 ;
     RECT  170.64 3.654 170.699 5.256 ;
     RECT  170.699 3.654 170.735 4.95 ;
     RECT  170.735 3.654 171.311 4.716 ;
     RECT  171.311 4.392 171.491 4.716 ;
     RECT  171.491 4.698 171.563 4.716 ;
    LAYER M3 ;
     RECT  171.864 0.043 171.882 0.091 ;
     RECT  171.468 0.091 171.882 0.173 ;
     RECT  169.128 0.043 169.146 0.523 ;
     RECT  90.936 0.091 91.206 0.571 ;
     RECT  92.988 0.523 93.006 0.571 ;
     RECT  170.352 0.523 170.37 1.051 ;
     RECT  87.804 0.571 87.822 1.099 ;
     RECT  131.724 0.523 131.742 1.099 ;
     RECT  169.128 0.523 169.218 1.099 ;
     RECT  94.788 0.571 94.806 1.147 ;
     RECT  169.128 1.099 169.254 1.627 ;
     RECT  170.352 1.051 170.55 1.627 ;
     RECT  169.128 1.627 170.55 1.675 ;
     RECT  87.804 1.099 88.254 1.723 ;
     RECT  90.936 0.571 93.006 1.723 ;
     RECT  94.68 1.147 94.806 1.723 ;
     RECT  96.408 0.571 96.426 1.723 ;
     RECT  99.468 0.523 99.486 1.723 ;
     RECT  105.3 1.627 105.318 1.723 ;
     RECT  108.936 0.571 108.954 1.723 ;
     RECT  110.268 0.523 110.286 1.723 ;
     RECT  117.432 1.675 117.45 1.723 ;
     RECT  123.12 1.147 123.138 1.723 ;
     RECT  126.504 0.571 126.522 1.723 ;
     RECT  131.724 1.099 131.814 1.723 ;
     RECT  132.624 0.091 132.642 1.723 ;
     RECT  135.18 0.571 135.198 1.723 ;
     RECT  147.672 1.147 147.69 1.723 ;
     RECT  159.156 0.523 159.174 1.723 ;
     RECT  169.128 1.675 170.694 1.723 ;
     RECT  97.452 1.723 100.314 1.771 ;
     RECT  101.232 1.723 104.562 1.771 ;
     RECT  105.3 1.723 107.478 1.771 ;
     RECT  108.396 1.723 111.402 1.771 ;
     RECT  112.464 1.723 112.698 1.771 ;
     RECT  123.12 1.723 123.786 1.771 ;
     RECT  124.56 1.723 125.658 1.771 ;
     RECT  126.432 1.723 127.818 1.771 ;
     RECT  128.772 1.723 129.006 1.771 ;
     RECT  137.196 1.723 147.942 1.771 ;
     RECT  148.68 1.723 148.986 1.771 ;
     RECT  150.012 1.723 150.174 1.771 ;
     RECT  151.056 1.723 156.042 1.771 ;
     RECT  90.936 1.723 96.606 1.795 ;
     RECT  90.648 1.795 96.606 1.819 ;
     RECT  97.452 1.771 100.422 1.819 ;
     RECT  108.396 1.771 111.618 1.819 ;
     RECT  112.464 1.771 112.77 1.819 ;
     RECT  113.544 1.723 114.066 1.819 ;
     RECT  114.876 1.723 118.962 1.819 ;
     RECT  119.952 1.723 122.346 1.819 ;
     RECT  123.12 1.771 129.006 1.819 ;
     RECT  129.78 1.723 130.518 1.819 ;
     RECT  131.364 1.723 136.422 1.819 ;
     RECT  156.924 1.723 157.23 1.831 ;
     RECT  157.968 1.723 166.59 1.831 ;
     RECT  113.544 1.819 118.962 1.867 ;
     RECT  60.192 1.831 60.21 1.876 ;
     RECT  101.232 1.771 107.55 1.915 ;
     RECT  108.396 1.819 112.77 1.915 ;
     RECT  156.924 1.831 166.59 1.963 ;
     RECT  101.232 1.915 112.77 2.011 ;
     RECT  113.544 1.867 118.998 2.011 ;
     RECT  150.012 1.771 156.042 2.011 ;
     RECT  156.852 1.963 166.59 2.011 ;
     RECT  87.804 1.723 89.838 2.029 ;
     RECT  90.648 1.819 100.422 2.029 ;
     RECT  87.804 2.029 100.422 2.065 ;
     RECT  150.012 2.011 166.59 2.065 ;
     RECT  167.436 1.723 170.694 2.065 ;
     RECT  119.952 1.819 130.518 2.101 ;
     RECT  131.364 1.819 136.458 2.101 ;
     RECT  137.196 1.771 149.13 2.101 ;
     RECT  150.012 2.065 170.694 2.101 ;
     RECT  62.388 1.993 62.406 2.143 ;
     RECT  84.06 2.101 84.078 2.143 ;
     RECT  119.952 2.101 136.458 2.155 ;
     RECT  137.196 2.101 170.694 2.155 ;
     RECT  87.228 2.065 100.422 2.191 ;
     RECT  101.232 2.011 118.998 2.191 ;
     RECT  119.952 2.155 170.694 2.191 ;
     RECT  2.415 2.143 2.505 2.413 ;
     RECT  5.115 2.143 5.205 2.413 ;
     RECT  7.815 2.143 7.905 2.413 ;
     RECT  10.515 2.143 10.605 2.413 ;
     RECT  13.215 2.143 13.305 2.413 ;
     RECT  15.915 2.143 16.005 2.413 ;
     RECT  18.615 2.143 18.705 2.413 ;
     RECT  21.315 2.143 21.405 2.413 ;
     RECT  24.015 2.143 24.105 2.413 ;
     RECT  26.715 2.143 26.805 2.413 ;
     RECT  29.415 2.143 29.505 2.413 ;
     RECT  32.115 2.143 32.205 2.413 ;
     RECT  34.815 2.143 34.905 2.413 ;
     RECT  37.515 2.143 37.605 2.413 ;
     RECT  40.215 2.143 40.305 2.413 ;
     RECT  42.915 2.143 43.005 2.413 ;
     RECT  45.615 2.143 45.705 2.413 ;
     RECT  48.315 2.143 48.405 2.413 ;
     RECT  51.015 2.143 51.105 2.413 ;
     RECT  53.715 2.143 53.805 2.413 ;
     RECT  56.415 2.143 56.505 2.413 ;
     RECT  59.115 2.143 59.205 2.413 ;
     RECT  64.515 2.143 64.605 2.413 ;
     RECT  67.215 2.143 67.305 2.413 ;
     RECT  69.915 2.143 70.005 2.413 ;
     RECT  72.615 2.143 72.705 2.413 ;
     RECT  75.315 2.143 75.405 2.413 ;
     RECT  78.015 2.143 78.105 2.413 ;
     RECT  80.715 2.143 80.805 2.413 ;
     RECT  86.115 2.143 86.205 2.413 ;
     RECT  59.115 2.413 59.397 2.533 ;
     RECT  64.515 2.413 64.797 2.539 ;
     RECT  84.924 2.335 84.942 2.569 ;
     RECT  84.924 2.569 85.014 2.669 ;
     RECT  69.915 2.413 70.197 2.731 ;
     RECT  78.015 2.413 78.297 2.731 ;
     RECT  87.228 2.191 170.694 2.827 ;
     RECT  171.468 0.173 171.486 2.827 ;
     RECT  69.915 2.731 70.722 2.861 ;
     RECT  78.015 2.731 78.678 2.861 ;
     RECT  48.315 2.413 48.597 2.911 ;
     RECT  84.924 2.669 84.942 2.939 ;
     RECT  63.54 2.641 63.558 3.073 ;
     RECT  86.115 2.413 86.397 3.073 ;
     RECT  87.228 2.827 171.486 3.073 ;
     RECT  64.515 2.539 65.25 3.181 ;
     RECT  86.115 3.073 171.486 3.299 ;
     RECT  86.115 3.299 129.978 3.335 ;
     RECT  130.788 3.299 171.486 3.403 ;
     RECT  128.304 3.335 128.322 3.443 ;
     RECT  51.015 2.413 51.297 3.451 ;
     RECT  52.236 2.605 52.254 3.451 ;
     RECT  83.415 2.143 84.078 3.649 ;
     RECT  48.315 2.911 49.302 3.685 ;
     RECT  86.115 3.335 124.197 3.713 ;
     RECT  56.415 2.413 56.697 3.721 ;
     RECT  75.315 2.413 75.597 3.811 ;
     RECT  82.728 3.649 84.078 3.991 ;
     RECT  82.656 3.991 84.078 4.109 ;
     RECT  53.715 2.413 53.997 4.261 ;
     RECT  83.088 4.109 84.078 4.415 ;
     RECT  86.115 3.713 86.397 4.507 ;
     RECT  87.156 3.713 124.197 4.507 ;
     RECT  130.788 3.403 171.558 4.685 ;
     RECT  171.54 4.685 171.558 4.721 ;
     RECT  84.924 4.801 84.942 4.891 ;
     RECT  130.788 4.685 170.73 4.955 ;
     RECT  84.924 4.891 84.978 4.991 ;
     RECT  84.96 4.991 84.978 5.027 ;
     RECT  83.088 4.415 83.697 5.035 ;
     RECT  69.915 2.861 70.197 5.071 ;
     RECT  130.788 4.955 170.694 5.261 ;
     RECT  61.815 2.143 62.406 5.305 ;
     RECT  63.504 3.073 63.558 5.305 ;
     RECT  80.715 2.413 80.997 5.341 ;
     RECT  130.788 5.261 170.514 5.459 ;
     RECT  66.384 2.827 66.402 5.467 ;
     RECT  67.215 2.413 67.497 5.467 ;
     RECT  78.015 2.861 78.297 5.575 ;
     RECT  66.384 5.467 67.497 5.701 ;
     RECT  72.615 2.413 72.897 5.809 ;
     RECT  74.052 5.503 74.07 5.809 ;
     RECT  82.908 5.035 83.697 5.845 ;
     RECT  45.615 2.413 45.897 5.971 ;
     RECT  60.984 4.387 61.002 5.971 ;
     RECT  61.815 5.305 63.558 5.971 ;
     RECT  66.384 5.701 68.094 6.241 ;
     RECT  130.788 5.459 169.002 6.269 ;
     RECT  125.172 3.335 127.566 6.421 ;
     RECT  124.92 6.421 127.566 6.449 ;
     RECT  69.516 5.071 70.197 6.511 ;
     RECT  82.368 5.845 83.697 6.583 ;
     RECT  66.132 6.241 68.094 6.619 ;
     RECT  53.715 4.261 54.414 6.655 ;
     RECT  69.516 6.511 70.722 6.691 ;
     RECT  76.32 4.891 76.338 6.817 ;
     RECT  51.015 3.451 52.254 7.087 ;
     RECT  53.136 6.655 54.414 7.087 ;
     RECT  69.3 6.691 70.722 7.123 ;
     RECT  77.976 5.575 78.297 7.159 ;
     RECT  69.3 7.123 70.83 7.195 ;
     RECT  85.32 5.995 85.338 7.357 ;
     RECT  86.115 4.507 124.197 7.357 ;
     RECT  85.32 7.357 124.197 7.627 ;
     RECT  77.472 7.159 78.297 7.663 ;
     RECT  79.452 6.781 79.47 7.663 ;
     RECT  51.015 7.087 54.414 7.699 ;
     RECT  76.32 6.817 76.626 7.735 ;
     RECT  82.368 6.583 84.078 8.275 ;
     RECT  84.852 7.627 124.197 8.275 ;
     RECT  76.32 7.735 76.698 8.311 ;
     RECT  77.472 7.663 79.47 8.311 ;
     RECT  72.615 5.809 74.07 8.401 ;
     RECT  75.132 3.811 75.597 8.779 ;
     RECT  76.32 8.311 79.47 8.779 ;
     RECT  45.615 5.971 46.386 8.851 ;
     RECT  47.556 3.991 47.574 8.851 ;
     RECT  130.788 6.269 150.066 9.041 ;
     RECT  75.132 8.779 79.47 9.355 ;
     RECT  80.715 5.341 81.306 9.419 ;
     RECT  130.788 9.041 136.242 9.581 ;
     RECT  56.415 3.721 57.294 9.931 ;
     RECT  55.548 7.933 55.566 10.021 ;
     RECT  58.536 2.533 59.397 10.057 ;
     RECT  55.188 10.021 55.566 10.093 ;
     RECT  58.5 10.057 59.397 10.129 ;
     RECT  124.92 6.449 127.206 10.499 ;
     RECT  72.615 8.401 74.358 10.597 ;
     RECT  75.132 9.355 79.686 10.597 ;
     RECT  80.715 9.419 81.234 10.741 ;
     RECT  82.368 8.275 124.197 10.741 ;
     RECT  72.615 10.597 79.686 10.831 ;
     RECT  130.788 9.581 136.098 11.165 ;
     RECT  72.615 10.831 79.758 11.173 ;
     RECT  60.984 5.971 63.558 11.209 ;
     RECT  64.515 3.181 65.286 11.209 ;
     RECT  71.964 11.173 79.758 11.245 ;
     RECT  150.876 6.269 169.002 11.309 ;
     RECT  45.615 8.851 47.574 11.371 ;
     RECT  48.315 3.685 49.41 11.371 ;
     RECT  66.132 6.619 68.526 11.551 ;
     RECT  69.3 7.195 71.118 11.551 ;
     RECT  50.508 7.699 54.414 11.641 ;
     RECT  55.152 10.093 55.566 11.641 ;
     RECT  137.052 9.041 150.066 11.669 ;
     RECT  150.915 11.309 169.002 11.777 ;
     RECT  50.508 11.641 55.566 11.785 ;
     RECT  60.984 11.209 65.286 11.821 ;
     RECT  66.132 11.551 71.118 11.821 ;
     RECT  129.132 3.335 129.978 11.983 ;
     RECT  130.788 11.165 135.99 11.983 ;
     RECT  124.92 10.499 127.17 11.995 ;
     RECT  129.132 11.983 135.99 11.995 ;
     RECT  60.12 1.876 60.21 12.019 ;
     RECT  60.984 11.821 71.118 12.019 ;
     RECT  124.92 11.995 127.71 12.181 ;
     RECT  45.615 11.371 49.41 12.253 ;
     RECT  124.92 12.181 127.782 12.451 ;
     RECT  80.715 10.741 124.197 12.571 ;
     RECT  124.92 12.451 127.818 12.571 ;
     RECT  80.715 12.571 127.818 12.631 ;
     RECT  128.808 11.995 135.99 12.631 ;
     RECT  60.12 12.019 71.118 12.829 ;
     RECT  71.964 11.245 79.794 12.829 ;
     RECT  80.715 12.631 135.99 13.085 ;
     RECT  162.72 11.777 169.002 13.163 ;
     RECT  162.72 13.163 168.714 13.433 ;
     RECT  50.4 11.785 55.566 13.441 ;
     RECT  125.1 13.085 135.99 13.661 ;
     RECT  150.915 11.777 161.997 13.739 ;
     RECT  162.72 13.433 165.042 13.973 ;
     RECT  125.1 13.661 127.962 14.135 ;
     RECT  129.132 13.661 129.834 14.141 ;
     RECT  45.54 12.253 49.41 14.215 ;
     RECT  50.148 13.441 55.566 14.215 ;
     RECT  125.136 14.135 127.962 14.237 ;
     RECT  129.132 14.141 129.762 14.243 ;
     RECT  169.815 5.459 170.514 14.711 ;
     RECT  0.108 14.587 0.126 14.717 ;
     RECT  60.12 12.829 79.794 14.719 ;
     RECT  80.715 13.085 124.197 14.719 ;
     RECT  166.104 13.433 168.714 14.783 ;
     RECT  160.452 13.739 161.997 14.819 ;
     RECT  160.956 14.819 161.997 15.089 ;
     RECT  58.068 10.129 59.397 15.295 ;
     RECT  60.12 14.719 124.197 15.295 ;
     RECT  2.415 2.413 2.697 15.592 ;
     RECT  5.115 2.413 5.397 15.592 ;
     RECT  2.304 15.592 2.697 15.629 ;
     RECT  5.004 15.592 5.397 15.629 ;
     RECT  10.515 2.413 10.797 15.739 ;
     RECT  162.72 13.973 164.898 15.755 ;
     RECT  56.376 9.931 57.294 15.763 ;
     RECT  58.068 15.295 124.197 15.763 ;
     RECT  6.84 15.595 6.858 15.773 ;
     RECT  150.915 13.739 159.297 15.899 ;
     RECT  160.992 15.089 161.997 16.259 ;
     RECT  150.915 15.899 152.658 16.295 ;
     RECT  153.615 15.899 159.297 16.367 ;
     RECT  150.915 16.295 152.55 16.835 ;
     RECT  130.788 13.661 135.99 16.979 ;
     RECT  45.54 14.215 55.566 17.077 ;
     RECT  10.515 15.739 11.106 17.105 ;
     RECT  130.788 16.979 133.542 17.375 ;
     RECT  150.915 16.835 152.514 17.447 ;
     RECT  162.72 15.755 164.697 17.519 ;
     RECT  155.304 16.367 159.297 17.645 ;
     RECT  45.54 17.077 55.602 17.653 ;
     RECT  137.088 11.669 150.066 17.681 ;
     RECT  157.356 17.645 159.297 17.951 ;
     RECT  137.415 17.681 150.066 18.023 ;
     RECT  161.136 16.259 161.997 18.059 ;
     RECT  45.54 17.653 55.638 18.121 ;
     RECT  56.376 15.763 124.197 18.121 ;
     RECT  150.915 17.447 152.154 18.185 ;
     RECT  155.304 17.645 156.597 18.563 ;
     RECT  137.415 18.023 149.814 18.599 ;
     RECT  163.152 17.519 164.697 18.689 ;
     RECT  19.944 17.041 19.962 18.725 ;
     RECT  137.415 18.599 148.806 18.761 ;
     RECT  21.315 2.413 21.597 18.841 ;
     RECT  150.915 18.185 152.082 19.067 ;
     RECT  157.536 17.951 159.297 19.139 ;
     RECT  138.78 18.761 148.806 19.229 ;
     RECT  157.536 19.139 157.914 19.265 ;
     RECT  163.152 18.689 163.458 19.301 ;
     RECT  149.652 18.599 149.814 19.337 ;
     RECT  134.715 16.979 135.99 19.373 ;
     RECT  157.536 19.265 157.554 19.679 ;
     RECT  153.615 16.367 154.386 19.769 ;
     RECT  163.152 19.301 163.17 19.841 ;
     RECT  166.32 14.783 168.714 19.877 ;
     RECT  166.752 19.877 168.714 19.913 ;
     RECT  134.715 19.373 135.846 19.949 ;
     RECT  155.664 18.563 156.597 20.219 ;
     RECT  166.752 19.913 167.85 20.309 ;
     RECT  149.652 19.337 149.67 20.345 ;
     RECT  138.78 19.229 148.497 20.381 ;
     RECT  138.78 20.381 147.438 20.417 ;
     RECT  138.78 20.417 147.33 20.453 ;
     RECT  150.915 19.067 151.902 20.489 ;
     RECT  45.54 18.121 124.197 20.821 ;
     RECT  125.136 14.237 125.55 20.821 ;
     RECT  129.132 14.243 129.597 20.827 ;
     RECT  130.788 17.375 133.29 20.827 ;
     RECT  138.78 20.453 144.45 20.849 ;
     RECT  145.296 20.453 147.33 20.885 ;
     RECT  130.536 20.827 133.29 20.957 ;
     RECT  137.415 18.761 138.006 20.957 ;
     RECT  135.828 19.949 135.846 20.993 ;
     RECT  45.54 20.821 125.55 21.091 ;
     RECT  126.324 14.237 127.962 21.091 ;
     RECT  45.54 21.091 127.962 21.115 ;
     RECT  129.132 20.827 129.69 21.115 ;
     RECT  130.788 20.957 133.29 21.119 ;
     RECT  145.296 20.885 146.754 21.155 ;
     RECT  21.315 18.841 22.23 21.425 ;
     RECT  45.54 21.115 129.69 21.569 ;
     RECT  131.112 21.119 133.29 21.659 ;
     RECT  133.056 21.659 133.29 21.731 ;
     RECT  138.78 20.849 143.097 22.613 ;
     RECT  141.156 22.613 143.097 22.649 ;
     RECT  143.892 20.849 144.45 23.117 ;
     RECT  131.112 21.659 132.297 23.189 ;
     RECT  141.84 22.649 143.097 23.351 ;
     RECT  45.54 21.569 129.597 23.371 ;
     RECT  131.4 23.189 132.297 23.621 ;
     RECT  145.515 21.155 146.754 23.657 ;
     RECT  142.308 23.351 143.097 23.693 ;
     RECT  145.515 23.657 146.466 23.693 ;
     RECT  145.515 23.693 146.322 23.855 ;
     RECT  137.415 20.957 137.97 23.891 ;
     RECT  45.504 23.371 129.597 23.947 ;
     RECT  133.056 21.731 133.11 23.999 ;
     RECT  45.504 23.947 129.906 24.061 ;
     RECT  143.892 23.117 144.018 24.197 ;
     RECT  45.504 24.061 130.302 24.241 ;
     RECT  138.78 22.613 140.397 24.269 ;
     RECT  45.468 24.241 130.302 24.431 ;
     RECT  139.356 24.269 140.397 24.431 ;
     RECT  45.468 24.431 129.978 24.511 ;
     RECT  45.36 24.511 129.978 24.619 ;
     RECT  133.056 23.999 133.074 24.737 ;
     RECT  166.752 20.309 167.397 24.773 ;
     RECT  168.696 19.913 168.714 24.809 ;
     RECT  155.952 20.219 156.597 25.079 ;
     RECT  142.344 23.693 143.097 25.277 ;
     RECT  143.892 24.197 143.91 25.313 ;
     RECT  45.18 24.619 129.978 25.321 ;
     RECT  139.356 24.431 139.374 25.619 ;
     RECT  45.072 25.321 130.086 25.675 ;
     RECT  44.928 25.675 130.086 25.781 ;
     RECT  44.928 25.781 129.798 25.861 ;
     RECT  44.676 25.861 129.798 25.979 ;
     RECT  44.784 25.979 129.798 26.671 ;
     RECT  42.915 2.413 43.197 26.941 ;
     RECT  43.992 26.869 44.01 26.941 ;
     RECT  42.915 26.941 44.01 27.031 ;
     RECT  44.784 26.671 129.87 27.031 ;
     RECT  42.915 27.031 129.87 27.211 ;
     RECT  42.915 27.211 130.086 27.481 ;
     RECT  42.915 27.481 130.23 27.715 ;
     RECT  2.415 15.629 2.697 27.827 ;
     RECT  5.115 15.629 5.397 27.827 ;
     RECT  7.815 2.413 8.097 27.827 ;
     RECT  10.515 17.105 10.797 27.827 ;
     RECT  13.215 2.413 13.497 27.827 ;
     RECT  15.915 2.413 16.197 27.827 ;
     RECT  18.615 2.413 18.897 27.827 ;
     RECT  21.315 21.425 21.597 27.827 ;
     RECT  24.015 2.413 24.297 27.827 ;
     RECT  26.715 2.413 26.997 27.827 ;
     RECT  29.415 2.413 29.697 27.827 ;
     RECT  32.115 2.413 32.397 27.827 ;
     RECT  34.815 2.413 35.097 27.827 ;
     RECT  37.515 2.413 37.797 27.827 ;
     RECT  40.215 2.413 40.497 27.827 ;
     RECT  42.915 27.715 130.302 27.827 ;
     RECT  132.015 23.621 132.297 27.827 ;
     RECT  134.715 19.949 134.997 27.827 ;
     RECT  137.415 23.891 137.697 27.827 ;
     RECT  140.115 24.431 140.397 27.827 ;
     RECT  142.815 25.277 143.097 27.827 ;
     RECT  145.515 23.855 145.797 27.827 ;
     RECT  148.215 20.381 148.497 27.827 ;
     RECT  150.915 20.489 151.197 27.827 ;
     RECT  153.615 19.769 153.897 27.827 ;
     RECT  156.315 25.079 156.597 27.827 ;
     RECT  159.015 19.139 159.297 27.827 ;
     RECT  161.715 18.059 161.997 27.827 ;
     RECT  164.415 18.689 164.697 27.827 ;
     RECT  167.115 24.773 167.397 27.827 ;
     RECT  169.815 14.711 170.097 27.827 ;
     RECT  43.848 27.827 130.302 27.869 ;
     RECT  58.104 27.869 59.454 27.875 ;
     RECT  117.396 27.869 118.605 27.875 ;
     RECT  123.768 27.869 130.23 27.905 ;
     RECT  123.768 27.905 129.405 27.917 ;
     RECT  44.028 27.869 51.39 27.941 ;
     RECT  53.715 27.869 54.594 27.941 ;
     RECT  55.692 27.869 57.222 27.941 ;
     RECT  58.104 27.875 58.266 27.941 ;
     RECT  64.476 27.869 64.926 27.941 ;
     RECT  66.492 27.869 68.958 27.941 ;
     RECT  69.915 27.869 70.758 27.941 ;
     RECT  74.088 27.869 76.77 27.941 ;
     RECT  80.676 27.869 82.35 27.941 ;
     RECT  83.196 27.869 84.834 27.941 ;
     RECT  85.86 27.869 94.305 27.941 ;
     RECT  95.076 27.869 102.654 27.941 ;
     RECT  103.536 27.869 105.105 27.941 ;
     RECT  106.164 27.869 106.506 27.941 ;
     RECT  107.388 27.869 108.234 27.941 ;
     RECT  110.415 27.869 111.726 27.941 ;
     RECT  61.056 27.869 61.074 27.965 ;
     RECT  62.964 27.869 63.09 27.965 ;
     RECT  77.868 27.869 79.146 27.965 ;
     RECT  81.72 27.941 81.81 27.965 ;
     RECT  87.264 27.941 88.905 27.965 ;
     RECT  96.552 27.941 101.322 27.965 ;
     RECT  103.536 27.941 104.166 27.965 ;
     RECT  119.664 27.869 119.682 27.965 ;
     RECT  123.768 27.917 125.262 27.965 ;
     RECT  103.608 27.965 104.166 28.049 ;
     RECT  126.468 27.917 129.405 28.049 ;
     RECT  2.415 27.827 2.505 28.097 ;
     RECT  5.115 27.827 5.205 28.097 ;
     RECT  7.815 27.827 7.905 28.097 ;
     RECT  10.515 27.827 10.605 28.097 ;
     RECT  13.215 27.827 13.305 28.097 ;
     RECT  15.915 27.827 16.005 28.097 ;
     RECT  18.615 27.827 18.705 28.097 ;
     RECT  21.315 27.827 21.405 28.097 ;
     RECT  24.015 27.827 24.105 28.097 ;
     RECT  26.715 27.827 26.805 28.097 ;
     RECT  29.415 27.827 29.505 28.097 ;
     RECT  32.115 27.827 32.205 28.097 ;
     RECT  34.815 27.827 34.905 28.097 ;
     RECT  37.515 27.827 37.605 28.097 ;
     RECT  40.215 27.827 40.305 28.097 ;
     RECT  42.915 27.827 43.005 28.097 ;
     RECT  44.028 27.941 51.105 28.097 ;
     RECT  53.715 27.941 53.805 28.097 ;
     RECT  55.728 27.941 56.505 28.097 ;
     RECT  59.115 27.875 59.454 28.097 ;
     RECT  61.815 27.869 61.905 28.097 ;
     RECT  64.476 27.941 64.605 28.097 ;
     RECT  66.492 27.941 67.305 28.097 ;
     RECT  69.915 27.941 70.506 28.097 ;
     RECT  71.964 27.869 72.705 28.097 ;
     RECT  74.088 27.941 76.194 28.097 ;
     RECT  77.868 27.965 79.038 28.097 ;
     RECT  80.676 27.941 80.805 28.097 ;
     RECT  83.415 27.941 83.505 28.097 ;
     RECT  88.2 27.965 88.905 28.097 ;
     RECT  89.784 27.941 91.605 28.097 ;
     RECT  92.52 27.941 94.305 28.097 ;
     RECT  96.552 27.965 100.278 28.097 ;
     RECT  102.315 27.941 102.654 28.097 ;
     RECT  104.904 27.941 105.105 28.097 ;
     RECT  110.415 27.941 110.79 28.097 ;
     RECT  112.86 27.869 113.205 28.097 ;
     RECT  118.368 27.875 118.605 28.097 ;
     RECT  121.215 27.869 121.305 28.097 ;
     RECT  126.615 28.049 129.405 28.097 ;
     RECT  132.015 27.827 132.105 28.097 ;
     RECT  134.715 27.827 134.805 28.097 ;
     RECT  137.415 27.827 137.505 28.097 ;
     RECT  140.115 27.827 140.205 28.097 ;
     RECT  142.815 27.827 142.905 28.097 ;
     RECT  145.515 27.827 145.605 28.097 ;
     RECT  148.215 27.827 148.305 28.097 ;
     RECT  150.915 27.827 151.005 28.097 ;
     RECT  153.615 27.827 153.705 28.097 ;
     RECT  156.315 27.827 156.405 28.097 ;
     RECT  159.015 27.827 159.105 28.097 ;
     RECT  161.715 27.827 161.805 28.097 ;
     RECT  164.415 27.827 164.505 28.097 ;
     RECT  167.115 27.827 167.205 28.097 ;
     RECT  169.815 27.827 169.905 28.097 ;
     RECT  111.564 27.941 111.726 28.205 ;
     RECT  44.028 28.097 50.886 28.253 ;
     RECT  92.52 28.097 94.194 28.253 ;
     RECT  104.904 28.097 104.922 28.253 ;
     RECT  126.756 28.097 129.294 28.253 ;
     RECT  64.476 28.097 64.494 28.301 ;
     RECT  81.72 27.965 81.738 28.301 ;
     RECT  123.768 27.965 124.254 28.397 ;
     RECT  126.756 28.253 128.934 28.397 ;
     RECT  128.304 28.397 128.934 28.445 ;
     RECT  44.028 28.253 50.454 28.493 ;
     RECT  74.088 28.097 74.646 28.493 ;
     RECT  88.2 28.097 88.218 28.493 ;
     RECT  89.784 28.097 91.35 28.493 ;
     RECT  95.076 27.941 95.706 28.493 ;
     RECT  97.452 28.097 99.27 28.493 ;
     RECT  103.608 28.049 104.022 28.493 ;
     RECT  107.388 27.941 108.126 28.493 ;
     RECT  126.756 28.397 127.386 28.493 ;
     RECT  128.916 28.445 128.934 28.493 ;
     RECT  46.332 28.493 47.106 28.541 ;
     RECT  58.104 27.941 58.122 28.541 ;
     RECT  59.436 28.097 59.454 28.541 ;
     RECT  68.364 27.941 68.958 28.541 ;
     RECT  70.308 28.097 70.506 28.541 ;
     RECT  71.964 28.097 72.414 28.541 ;
     RECT  74.628 28.493 74.646 28.541 ;
     RECT  75.996 28.097 76.194 28.541 ;
     RECT  84.816 27.941 84.834 28.541 ;
     RECT  85.86 27.941 86.526 28.541 ;
     RECT  87.264 27.965 87.282 28.541 ;
     RECT  95.364 28.493 95.706 28.541 ;
     RECT  97.452 28.493 98.19 28.541 ;
     RECT  99.18 28.493 99.27 28.541 ;
     RECT  100.08 28.097 100.278 28.541 ;
     RECT  110.772 28.097 110.79 28.541 ;
     RECT  112.86 28.097 113.022 28.541 ;
     RECT  115.452 27.869 116.442 28.541 ;
     RECT  117.396 27.875 117.414 28.541 ;
     RECT  118.368 28.097 118.494 28.541 ;
     RECT  47.988 28.493 49.878 28.589 ;
     RECT  54.576 27.941 54.594 28.829 ;
     RECT  55.728 28.097 56.286 28.829 ;
     RECT  66.492 28.097 67.122 28.829 ;
     RECT  75.996 28.541 76.014 28.829 ;
     RECT  72.396 28.541 72.414 28.973 ;
     RECT  118.368 28.541 118.386 28.973 ;
     RECT  62.964 27.965 62.982 29.029 ;
     RECT  107.604 28.493 108.126 29.029 ;
     RECT  62.712 29.029 62.982 29.057 ;
     RECT  46.548 28.541 47.106 29.069 ;
     RECT  49.212 28.589 49.878 29.069 ;
     RECT  52.128 27.869 52.794 29.069 ;
     RECT  55.728 28.829 55.746 29.069 ;
     RECT  61.596 28.843 61.614 29.069 ;
     RECT  67.104 28.829 67.122 29.069 ;
     RECT  68.796 28.541 68.814 29.069 ;
     RECT  70.308 28.541 70.326 29.069 ;
     RECT  77.868 28.097 77.886 29.069 ;
     RECT  78.624 28.097 79.038 29.069 ;
     RECT  80.676 28.097 80.694 29.069 ;
     RECT  85.86 28.541 85.878 29.069 ;
     RECT  92.52 28.253 93.942 29.069 ;
     RECT  95.364 28.541 95.382 29.069 ;
     RECT  96.552 28.097 96.57 29.069 ;
     RECT  99.18 28.541 99.198 29.069 ;
     RECT  100.08 28.541 100.098 29.069 ;
     RECT  101.304 27.965 101.322 29.069 ;
     RECT  102.636 28.097 102.654 29.069 ;
     RECT  107.604 29.029 108.306 29.069 ;
     RECT  109.584 27.869 109.602 29.069 ;
     RECT  112.86 28.541 112.878 29.069 ;
     RECT  114.228 27.869 114.246 29.069 ;
     RECT  115.704 28.541 115.722 29.069 ;
     RECT  126.756 28.493 127.062 29.069 ;
     RECT  78.624 29.069 78.642 29.083 ;
     RECT  44.028 28.493 45.558 29.117 ;
     RECT  47.988 28.589 48.114 29.117 ;
     RECT  78.552 29.083 78.642 29.117 ;
     RECT  89.784 28.493 90.45 29.117 ;
     RECT  93.132 29.069 93.942 29.117 ;
     RECT  125.208 27.965 125.262 29.117 ;
     RECT  126.756 29.069 126.774 29.117 ;
     RECT  108.072 29.069 108.306 29.549 ;
     RECT  44.028 29.117 45.162 29.645 ;
     RECT  47.988 29.117 48.006 29.645 ;
     RECT  93.132 29.117 93.69 29.645 ;
     RECT  97.452 28.541 97.47 29.645 ;
     RECT  106.164 27.941 106.182 29.645 ;
     RECT  108.072 29.549 108.09 29.645 ;
     RECT  122.436 27.869 122.454 29.645 ;
     RECT  125.244 29.117 125.262 29.645 ;
     RECT  44.892 29.645 45.162 29.693 ;
     RECT  49.212 29.069 49.23 29.693 ;
     RECT  62.712 29.057 62.73 29.693 ;
     RECT  78.552 29.117 78.57 29.899 ;
     RECT  44.028 29.645 44.046 30.077 ;
     RECT  78.552 29.899 78.642 30.077 ;
     RECT  44.892 29.693 44.91 30.125 ;
     RECT  52.128 29.069 52.146 30.125 ;
     RECT  54.648 29.995 54.666 30.125 ;
     RECT  78.552 30.077 78.57 30.125 ;
     RECT  89.964 29.117 90.45 30.125 ;
     RECT  111.564 28.205 111.582 30.125 ;
     RECT  124.236 28.397 124.254 30.125 ;
     RECT  47.088 29.069 47.106 30.173 ;
     RECT  90.432 30.125 90.45 30.221 ;
     RECT  104.004 28.493 104.022 30.221 ;
    LAYER M4 ;
     RECT  0.097 14.592 0.137 15.624 ;
     RECT  0.137 14.688 2.408 15.624 ;
     RECT  2.408 2.148 2.512 28.092 ;
     RECT  2.512 2.418 2.704 27.822 ;
     RECT  2.704 14.688 5.108 15.624 ;
     RECT  5.108 2.148 5.212 28.092 ;
     RECT  5.212 2.418 5.404 27.822 ;
     RECT  5.404 14.688 6.829 15.624 ;
     RECT  6.829 14.688 7.808 15.768 ;
     RECT  7.808 2.148 7.912 28.092 ;
     RECT  7.912 2.418 8.104 27.822 ;
     RECT  8.104 14.688 10.508 14.712 ;
     RECT  8.104 15.744 10.508 15.768 ;
     RECT  10.508 2.148 10.612 28.092 ;
     RECT  10.612 2.418 10.804 27.822 ;
     RECT  10.804 15.744 11.117 15.768 ;
     RECT  10.804 14.688 13.208 14.712 ;
     RECT  13.208 2.148 13.312 28.092 ;
     RECT  13.312 2.418 13.504 27.822 ;
     RECT  13.504 14.688 15.908 14.712 ;
     RECT  15.908 2.148 16.012 28.092 ;
     RECT  16.012 2.418 16.204 27.822 ;
     RECT  16.204 14.688 18.608 14.712 ;
     RECT  18.608 2.148 18.712 28.092 ;
     RECT  18.712 2.418 18.904 27.822 ;
     RECT  18.904 14.688 21.308 14.712 ;
     RECT  21.308 2.148 21.412 28.092 ;
     RECT  21.412 2.418 21.604 27.822 ;
     RECT  21.604 14.688 24.008 14.712 ;
     RECT  24.008 2.148 24.112 28.092 ;
     RECT  24.112 2.418 24.304 27.822 ;
     RECT  24.304 14.688 26.708 14.712 ;
     RECT  26.708 2.148 26.812 28.092 ;
     RECT  26.812 2.418 27.004 27.822 ;
     RECT  27.004 14.688 29.408 14.712 ;
     RECT  29.408 2.148 29.512 28.092 ;
     RECT  29.512 2.418 29.704 27.822 ;
     RECT  29.704 14.688 32.108 14.712 ;
     RECT  32.108 2.148 32.212 28.092 ;
     RECT  32.212 2.418 32.404 27.822 ;
     RECT  32.404 14.688 34.808 14.712 ;
     RECT  34.808 2.148 34.912 28.092 ;
     RECT  34.912 2.418 35.104 27.822 ;
     RECT  35.104 14.688 37.508 14.712 ;
     RECT  37.508 2.148 37.612 28.092 ;
     RECT  37.612 2.418 37.804 27.822 ;
     RECT  37.804 14.688 40.208 14.712 ;
     RECT  40.208 2.148 40.312 28.092 ;
     RECT  40.312 2.418 40.504 27.822 ;
     RECT  42.325 30.048 42.565 30.072 ;
     RECT  42.565 30.048 42.611 30.168 ;
     RECT  40.504 14.688 42.908 14.712 ;
     RECT  42.469 28.752 42.908 28.776 ;
     RECT  42.908 2.148 43.012 28.776 ;
     RECT  43.012 2.418 43.204 28.776 ;
     RECT  42.611 30.144 43.717 30.168 ;
     RECT  43.717 30.096 43.813 30.168 ;
     RECT  43.813 30.096 44.017 30.216 ;
     RECT  43.204 28.752 44.557 28.776 ;
     RECT  44.017 30.048 44.557 30.216 ;
     RECT  44.557 28.752 44.78 30.216 ;
     RECT  43.204 26.016 44.917 26.04 ;
     RECT  44.78 28.512 44.945 30.216 ;
     RECT  44.917 25.68 45.013 26.04 ;
     RECT  45.013 25.056 45.169 26.04 ;
     RECT  44.945 28.464 45.587 30.216 ;
     RECT  43.204 14.688 45.608 14.712 ;
     RECT  45.493 23.376 45.608 23.4 ;
     RECT  45.169 24.624 45.608 26.04 ;
     RECT  45.313 27.072 45.608 27.096 ;
     RECT  45.587 28.464 45.608 29.112 ;
     RECT  45.608 2.148 45.712 29.112 ;
     RECT  45.712 2.418 45.731 29.112 ;
     RECT  45.731 2.418 45.904 29.064 ;
     RECT  45.904 27.312 46.577 29.064 ;
     RECT  46.577 27.312 46.739 28.776 ;
     RECT  45.904 21.84 46.924 26.04 ;
     RECT  46.924 21.84 47.005 24.648 ;
     RECT  46.924 26.016 47.077 26.04 ;
     RECT  46.739 27.312 47.077 27.336 ;
     RECT  47.005 21.792 47.333 24.648 ;
     RECT  46.739 28.464 47.933 28.776 ;
     RECT  45.587 30.144 47.933 30.216 ;
     RECT  47.933 28.464 48.017 30.216 ;
     RECT  48.017 28.464 48.131 29.112 ;
     RECT  47.333 24.624 48.265 24.648 ;
     RECT  47.077 26.016 48.265 27.336 ;
     RECT  48.131 28.464 48.265 28.776 ;
     RECT  45.904 14.688 48.308 14.712 ;
     RECT  47.333 21.792 48.308 22.824 ;
     RECT  48.265 24.624 48.308 24.984 ;
     RECT  48.265 26.016 48.308 28.776 ;
     RECT  48.308 2.148 48.412 28.776 ;
     RECT  48.412 2.418 48.604 28.776 ;
     RECT  48.604 22.8 48.773 22.824 ;
     RECT  48.604 27.936 49.201 28.776 ;
     RECT  48.017 30.192 49.201 30.216 ;
     RECT  49.201 27.936 49.571 30.216 ;
     RECT  48.604 24.624 49.633 26.568 ;
     RECT  49.571 28.464 49.715 30.216 ;
     RECT  49.633 23.952 49.813 26.568 ;
     RECT  49.813 23.952 49.849 26.808 ;
     RECT  49.715 28.464 49.889 29.064 ;
     RECT  48.604 21.792 49.993 21.816 ;
     RECT  49.993 21.792 50.137 22.2 ;
     RECT  49.849 23.904 50.165 26.808 ;
     RECT  50.165 23.856 50.173 26.808 ;
     RECT  50.137 21.792 50.281 22.632 ;
     RECT  50.173 23.856 50.281 27.432 ;
     RECT  49.715 30.192 50.773 30.216 ;
     RECT  50.281 21.792 50.857 27.432 ;
     RECT  49.889 28.464 50.857 28.776 ;
     RECT  48.604 14.688 51.008 14.712 ;
     RECT  50.857 21.792 51.008 28.776 ;
     RECT  51.008 2.148 51.112 28.776 ;
     RECT  51.112 2.418 51.304 28.776 ;
     RECT  50.773 30.048 51.875 30.216 ;
     RECT  51.875 30.096 52.157 30.216 ;
     RECT  51.304 21.792 52.441 26.856 ;
     RECT  51.304 28.752 52.549 28.776 ;
     RECT  52.441 21.504 52.613 26.856 ;
     RECT  52.613 21.504 52.697 27.144 ;
     RECT  52.549 28.752 52.805 29.064 ;
     RECT  52.805 28.752 53.701 28.776 ;
     RECT  51.304 14.688 53.708 14.712 ;
     RECT  52.697 21.504 53.708 27.048 ;
     RECT  53.701 28.224 53.708 28.776 ;
     RECT  53.708 2.148 53.812 28.776 ;
     RECT  52.157 30.192 53.989 30.216 ;
     RECT  53.812 2.418 54.004 28.776 ;
     RECT  54.004 28.224 54.133 28.776 ;
     RECT  54.133 28.224 54.277 28.968 ;
     RECT  53.989 30.048 54.277 30.216 ;
     RECT  54.277 28.224 54.371 30.216 ;
     RECT  54.004 21.504 54.425 21.528 ;
     RECT  54.371 28.704 54.611 30.216 ;
     RECT  54.611 30 54.71 30.216 ;
     RECT  54.71 30.048 54.995 30.216 ;
     RECT  54.004 22.752 55.033 26.952 ;
     RECT  54.997 21.552 55.084 21.576 ;
     RECT  55.033 22.752 55.297 27.672 ;
     RECT  54.611 28.704 55.573 28.776 ;
     RECT  55.573 28.272 55.717 28.776 ;
     RECT  54.995 30.192 56.149 30.216 ;
     RECT  55.297 22.752 56.285 26.808 ;
     RECT  55.717 28.272 56.285 29.064 ;
     RECT  54.004 14.688 56.408 14.712 ;
     RECT  56.285 22.752 56.408 29.064 ;
     RECT  56.408 2.148 56.437 29.064 ;
     RECT  56.149 30.048 56.437 30.216 ;
     RECT  56.437 2.148 56.512 30.216 ;
     RECT  56.512 2.418 56.704 30.216 ;
     RECT  56.704 28.752 57.155 30.216 ;
     RECT  56.704 22.176 57.709 27.576 ;
     RECT  57.155 28.752 57.877 29.064 ;
     RECT  57.709 22.176 58.597 26.616 ;
     RECT  57.877 27.84 58.643 29.064 ;
     RECT  57.155 30.192 58.933 30.216 ;
     RECT  58.933 30.048 58.981 30.216 ;
     RECT  56.704 14.688 59.108 14.712 ;
     RECT  56.704 20.928 59.108 20.952 ;
     RECT  58.597 22.032 59.108 26.616 ;
     RECT  58.643 27.84 59.108 28.776 ;
     RECT  59.108 2.148 59.212 28.776 ;
     RECT  59.212 2.418 59.404 28.776 ;
     RECT  59.404 28.512 59.465 28.776 ;
     RECT  59.465 28.752 59.941 28.776 ;
     RECT  58.981 29.952 59.941 30.216 ;
     RECT  59.941 28.752 60.227 30.216 ;
     RECT  59.404 22.512 60.437 27.384 ;
     RECT  60.227 28.752 61.004 29.064 ;
     RECT  60.227 30.192 61.189 30.216 ;
     RECT  60.437 22.512 61.441 26.808 ;
     RECT  61.441 22.272 61.477 26.808 ;
     RECT  61.477 22.032 61.513 26.808 ;
     RECT  61.004 27.936 61.513 29.064 ;
     RECT  59.404 20.928 61.549 20.952 ;
     RECT  61.513 22.032 61.549 29.064 ;
     RECT  61.549 20.928 61.573 29.064 ;
     RECT  61.189 30.048 61.573 30.216 ;
     RECT  61.573 20.928 61.625 30.216 ;
     RECT  61.625 20.928 61.715 28.968 ;
     RECT  59.404 14.688 61.808 14.712 ;
     RECT  61.715 20.928 61.808 28.776 ;
     RECT  61.808 2.148 61.912 28.776 ;
     RECT  61.912 2.418 62.104 28.776 ;
     RECT  62.104 20.832 62.701 28.776 ;
     RECT  61.625 30 62.701 30.216 ;
     RECT  62.701 20.832 62.741 30.216 ;
     RECT  62.741 20.928 62.963 30.216 ;
     RECT  62.963 20.928 63.101 28.776 ;
     RECT  62.963 30.192 64.213 30.216 ;
     RECT  63.101 20.928 64.261 27.432 ;
     RECT  64.261 20.928 64.465 27.48 ;
     RECT  63.101 28.752 64.465 28.776 ;
     RECT  62.104 14.688 64.508 14.712 ;
     RECT  64.465 20.928 64.508 28.776 ;
     RECT  64.508 2.148 64.612 28.776 ;
     RECT  64.612 2.418 64.804 28.776 ;
     RECT  64.804 20.928 65.075 28.776 ;
     RECT  65.075 27.84 65.081 28.776 ;
     RECT  65.075 20.928 65.123 26.856 ;
     RECT  64.213 30.048 65.219 30.216 ;
     RECT  65.123 20.928 66.301 26.808 ;
     RECT  64.804 2.544 66.373 2.568 ;
     RECT  65.081 28.752 66.373 28.776 ;
     RECT  66.373 28.752 66.841 28.824 ;
     RECT  66.841 28.512 67.093 28.824 ;
     RECT  67.093 28.512 67.177 29.064 ;
     RECT  66.373 2.544 67.208 2.856 ;
     RECT  64.804 14.688 67.208 14.712 ;
     RECT  66.301 20.928 67.208 27.432 ;
     RECT  67.177 28.512 67.208 28.776 ;
     RECT  65.219 30.192 67.237 30.216 ;
     RECT  67.208 2.148 67.312 28.776 ;
     RECT  67.237 30.048 67.381 30.216 ;
     RECT  67.312 2.418 67.504 28.776 ;
     RECT  67.381 29.952 67.763 30.216 ;
     RECT  67.504 20.928 67.811 27.144 ;
     RECT  67.504 28.512 68.533 28.776 ;
     RECT  67.811 20.928 68.773 26.856 ;
     RECT  68.533 28.512 68.825 29.064 ;
     RECT  68.773 20.928 68.897 27.384 ;
     RECT  67.763 30.048 69.637 30.216 ;
     RECT  67.504 2.544 69.908 2.856 ;
     RECT  67.504 14.688 69.908 14.712 ;
     RECT  68.897 20.928 69.908 26.76 ;
     RECT  68.825 28.512 69.908 28.776 ;
     RECT  69.908 2.148 70.012 28.776 ;
     RECT  69.637 30 70.019 30.216 ;
     RECT  70.012 2.418 70.204 28.776 ;
     RECT  70.204 28.512 70.253 28.776 ;
     RECT  70.253 28.512 70.337 29.064 ;
     RECT  70.019 30.048 70.355 30.216 ;
     RECT  70.337 28.512 70.517 28.776 ;
     RECT  70.204 20.832 70.733 27.384 ;
     RECT  70.733 20.928 71.363 27.384 ;
     RECT  70.355 30.192 71.461 30.216 ;
     RECT  70.517 28.752 71.948 28.776 ;
     RECT  71.948 28.512 72.229 28.776 ;
     RECT  72.229 28.512 72.371 29.064 ;
     RECT  71.363 20.928 72.449 26.808 ;
     RECT  72.371 28.512 72.469 28.968 ;
     RECT  70.204 2.544 72.608 2.856 ;
     RECT  70.204 14.688 72.608 14.712 ;
     RECT  72.449 20.928 72.608 27.144 ;
     RECT  72.469 28.512 72.608 28.872 ;
     RECT  72.608 2.148 72.712 28.872 ;
     RECT  72.712 2.418 72.899 28.872 ;
     RECT  72.899 2.418 72.904 28.776 ;
     RECT  72.904 20.928 73.043 28.776 ;
     RECT  73.043 20.928 73.153 27.384 ;
     RECT  71.461 30.048 73.475 30.216 ;
     RECT  73.043 28.752 74.005 28.776 ;
     RECT  74.005 28.464 74.117 28.776 ;
     RECT  73.153 20.928 74.149 26.856 ;
     RECT  74.149 20.64 74.905 26.856 ;
     RECT  74.117 28.512 75.301 28.776 ;
     RECT  72.904 2.544 75.308 2.856 ;
     RECT  72.904 14.688 75.308 14.712 ;
     RECT  74.905 20.64 75.308 27.384 ;
     RECT  75.301 28.512 75.308 28.968 ;
     RECT  75.308 2.148 75.412 28.968 ;
     RECT  73.475 30.192 75.589 30.216 ;
     RECT  75.412 2.418 75.604 28.968 ;
     RECT  75.604 28.224 75.685 28.968 ;
     RECT  75.685 28.224 75.827 29.064 ;
     RECT  75.827 28.32 75.923 29.064 ;
     RECT  75.923 28.512 76.205 29.064 ;
     RECT  75.604 20.64 76.547 27.048 ;
     RECT  76.547 20.64 77.509 26.76 ;
     RECT  77.509 20.64 77.845 26.808 ;
     RECT  75.604 2.544 78.008 2.856 ;
     RECT  75.604 14.688 78.008 14.712 ;
     RECT  77.845 20.64 78.008 26.856 ;
     RECT  76.205 28.752 78.008 29.064 ;
     RECT  78.008 2.148 78.112 29.064 ;
     RECT  78.112 2.418 78.181 29.064 ;
     RECT  75.589 30.048 78.181 30.216 ;
     RECT  78.181 2.418 78.304 30.216 ;
     RECT  78.304 20.64 78.659 30.216 ;
     RECT  78.659 20.64 78.995 29.064 ;
     RECT  78.995 27.936 79.093 29.064 ;
     RECT  79.093 27.936 79.235 28.776 ;
     RECT  78.995 20.64 79.331 26.808 ;
     RECT  78.659 30.048 80.197 30.216 ;
     RECT  79.331 20.64 80.485 26.76 ;
     RECT  80.485 20.64 80.581 26.856 ;
     RECT  79.235 28.752 80.621 28.776 ;
     RECT  80.197 29.952 80.621 30.216 ;
     RECT  80.621 28.752 80.705 30.216 ;
     RECT  78.304 2.544 80.708 2.856 ;
     RECT  78.304 14.688 80.708 14.712 ;
     RECT  80.581 20.64 80.708 27.096 ;
     RECT  80.705 28.752 80.708 28.776 ;
     RECT  80.708 2.148 80.812 28.776 ;
     RECT  80.812 2.418 81.004 28.776 ;
     RECT  81.004 20.64 81.203 28.776 ;
     RECT  81.203 20.64 81.779 26.712 ;
     RECT  81.203 27.936 81.821 28.776 ;
     RECT  80.705 29.952 82.069 30.216 ;
     RECT  82.069 29.904 82.643 30.216 ;
     RECT  81.821 28.752 82.645 28.776 ;
     RECT  81.779 20.64 82.741 26.616 ;
     RECT  82.741 20.64 82.753 26.664 ;
     RECT  82.645 28.752 82.883 29.064 ;
     RECT  82.753 20.64 83.125 26.856 ;
     RECT  81.004 2.544 83.408 2.856 ;
     RECT  83.077 4.224 83.408 4.248 ;
     RECT  81.004 14.688 83.408 14.712 ;
     RECT  83.125 20.64 83.408 26.952 ;
     RECT  82.883 28.752 83.408 28.776 ;
     RECT  83.408 2.148 83.512 28.776 ;
     RECT  83.512 2.418 83.704 28.776 ;
     RECT  83.704 20.64 84.083 28.776 ;
     RECT  84.083 28.512 84.229 28.776 ;
     RECT  84.229 28.512 84.371 29.064 ;
     RECT  84.371 28.512 84.845 28.776 ;
     RECT  82.643 30.048 84.947 30.216 ;
     RECT  84.845 28.752 85.805 28.776 ;
     RECT  85.805 28.752 85.889 29.064 ;
     RECT  84.947 30.192 86.101 30.216 ;
     RECT  83.704 2.544 86.108 2.856 ;
     RECT  83.704 4.224 86.108 4.248 ;
     RECT  85.309 6 86.108 6.024 ;
     RECT  83.704 14.688 86.108 14.712 ;
     RECT  84.083 20.64 86.108 27.384 ;
     RECT  85.889 28.752 86.108 28.776 ;
     RECT  86.108 2.148 86.212 28.776 ;
     RECT  86.101 30.048 86.389 30.216 ;
     RECT  86.212 2.418 86.404 28.776 ;
     RECT  86.389 30 86.531 30.216 ;
     RECT  86.404 20.64 86.675 28.776 ;
     RECT  86.404 5.568 86.861 6.024 ;
     RECT  86.404 18.144 86.861 18.168 ;
     RECT  86.675 27.552 86.917 28.776 ;
     RECT  86.917 27.552 87.155 29.064 ;
     RECT  87.155 27.552 87.193 28.776 ;
     RECT  86.404 14.688 87.365 14.712 ;
     RECT  86.675 20.64 87.731 26.568 ;
     RECT  87.685 14.784 87.769 14.808 ;
     RECT  87.749 0.576 87.833 0.6 ;
     RECT  86.404 2.544 87.925 4.536 ;
     RECT  86.531 30.048 88.115 30.216 ;
     RECT  87.925 1.728 88.225 4.536 ;
     RECT  88.225 1.104 88.297 4.536 ;
     RECT  86.861 6 88.297 6.024 ;
     RECT  87.731 20.832 88.513 26.568 ;
     RECT  87.193 27.936 88.513 28.776 ;
     RECT  88.297 1.104 88.547 6.024 ;
     RECT  88.547 1.728 88.808 6.024 ;
     RECT  87.685 19.536 88.808 19.56 ;
     RECT  88.513 20.832 88.808 26.712 ;
     RECT  88.513 27.888 88.808 28.776 ;
     RECT  88.808 1.728 89.104 28.776 ;
     RECT  89.104 21.984 89.417 26.808 ;
     RECT  89.417 26.256 89.525 26.808 ;
     RECT  89.104 27.888 89.756 28.776 ;
     RECT  89.104 1.728 89.849 6.84 ;
     RECT  88.115 30.192 89.909 30.216 ;
     RECT  89.849 2.544 89.957 6.84 ;
     RECT  89.104 10.656 90.029 10.68 ;
     RECT  89.756 27.888 90.085 29.112 ;
     RECT  89.909 30.096 90.085 30.216 ;
     RECT  89.525 26.592 90.133 26.808 ;
     RECT  90.085 27.888 90.133 30.216 ;
     RECT  90.133 26.592 90.275 30.216 ;
     RECT  90.275 27.936 90.281 30.216 ;
     RECT  90.281 27.936 90.419 28.776 ;
     RECT  90.419 28.176 90.425 28.776 ;
     RECT  90.281 30 90.461 30.216 ;
     RECT  89.417 21.984 90.517 25.08 ;
     RECT  90.275 26.592 90.517 26.616 ;
     RECT  89.104 20.832 90.637 20.856 ;
     RECT  90.637 20.832 90.673 20.952 ;
     RECT  90.517 21.984 90.673 26.616 ;
     RECT  90.277 15.216 90.925 15.24 ;
     RECT  90.229 13.296 91.213 13.32 ;
     RECT  90.881 0.096 91.217 0.12 ;
     RECT  90.425 28.176 91.361 28.488 ;
     RECT  91.361 28.176 91.381 28.2 ;
     RECT  89.957 2.544 91.508 6.696 ;
     RECT  90.997 10.656 91.508 10.68 ;
     RECT  91.213 13.104 91.508 13.32 ;
     RECT  90.925 14.832 91.508 15.24 ;
     RECT  89.104 19.536 91.508 19.56 ;
     RECT  90.673 20.832 91.508 26.616 ;
     RECT  91.381 27.6 91.508 28.2 ;
     RECT  90.461 30 91.571 30.072 ;
     RECT  91.508 2.148 91.715 28.2 ;
     RECT  91.715 2.148 91.804 27.822 ;
     RECT  91.571 30.048 91.955 30.072 ;
     RECT  91.804 20.928 92.051 27.624 ;
     RECT  91.804 2.148 92.293 6.024 ;
     RECT  92.293 1.728 92.333 6.024 ;
     RECT  92.333 5.712 92.369 6.024 ;
     RECT  91.897 0.576 92.521 0.6 ;
     RECT  92.509 29.04 92.593 29.064 ;
     RECT  92.051 20.928 93.049 26.232 ;
     RECT  92.051 27.36 93.049 27.624 ;
     RECT  92.333 1.728 93.233 4.248 ;
     RECT  93.049 20.928 93.253 27.624 ;
     RECT  92.977 0.528 93.347 0.552 ;
     RECT  93.253 20.928 93.829 28.488 ;
     RECT  93.077 29.616 93.829 29.64 ;
     RECT  93.829 20.928 93.953 29.64 ;
     RECT  93.233 1.728 94.208 2.856 ;
     RECT  93.233 4.224 94.208 4.248 ;
     RECT  92.369 6 94.208 6.024 ;
     RECT  91.804 19.536 94.208 19.56 ;
     RECT  93.953 20.928 94.208 29.064 ;
     RECT  94.069 30.048 94.451 30.072 ;
     RECT  94.208 1.728 94.504 29.064 ;
     RECT  94.597 0.144 94.693 0.168 ;
     RECT  94.693 0.144 94.739 0.6 ;
     RECT  94.739 0.576 94.817 0.6 ;
     RECT  94.504 1.728 95.285 2.904 ;
     RECT  94.504 20.832 95.393 29.064 ;
     RECT  95.393 20.832 95.747 28.536 ;
     RECT  95.747 20.832 95.941 27.672 ;
     RECT  96.325 0.576 96.437 0.6 ;
     RECT  96.421 28.992 96.755 29.064 ;
     RECT  95.285 1.728 96.757 2.856 ;
     RECT  96.757 1.728 96.901 2.904 ;
     RECT  96.901 1.728 96.908 3 ;
     RECT  94.504 4.224 96.908 4.248 ;
     RECT  94.504 6 96.908 6.024 ;
     RECT  94.504 19.536 96.908 19.56 ;
     RECT  95.941 20.832 96.908 27.624 ;
     RECT  95.845 30.048 96.997 30.072 ;
     RECT  96.908 1.728 97.012 28.092 ;
     RECT  97.012 1.728 97.204 27.822 ;
     RECT  97.204 1.728 97.331 3.192 ;
     RECT  96.997 29.616 97.481 30.072 ;
     RECT  97.481 30.048 97.715 30.072 ;
     RECT  97.204 20.832 97.811 27.822 ;
     RECT  97.811 20.832 97.841 26.184 ;
     RECT  97.811 27.36 98.149 27.822 ;
     RECT  98.149 27.36 98.161 28.488 ;
     RECT  97.331 1.728 98.449 2.904 ;
     RECT  98.161 27.36 98.485 28.536 ;
     RECT  98.449 1.728 98.533 3.096 ;
     RECT  97.841 20.832 98.809 26.088 ;
     RECT  98.809 20.832 98.989 26.328 ;
     RECT  98.485 27.36 98.989 29.064 ;
     RECT  98.533 1.728 99.608 3.048 ;
     RECT  97.204 4.224 99.608 4.248 ;
     RECT  97.204 6 99.608 6.024 ;
     RECT  97.204 19.536 99.608 19.56 ;
     RECT  98.989 20.832 99.608 29.064 ;
     RECT  99.457 0.528 99.827 0.552 ;
     RECT  99.608 1.728 99.904 29.064 ;
     RECT  99.904 20.832 100.289 29.064 ;
     RECT  99.013 30.048 100.739 30.072 ;
     RECT  100.289 20.832 100.901 27.96 ;
     RECT  99.904 19.536 101.297 19.56 ;
     RECT  100.289 29.04 101.333 29.064 ;
     RECT  99.904 1.728 101.365 3.096 ;
     RECT  99.904 4.224 101.365 4.248 ;
     RECT  100.901 20.832 101.977 27.624 ;
     RECT  102.085 30.048 102.133 30.072 ;
     RECT  102.133 0.144 102.275 0.168 ;
     RECT  101.365 1.728 102.308 4.248 ;
     RECT  99.904 6 102.308 6.024 ;
     RECT  101.977 19.92 102.308 27.624 ;
     RECT  102.133 29.952 102.371 30.072 ;
     RECT  102.308 1.728 102.412 28.092 ;
     RECT  102.371 29.952 102.515 29.976 ;
     RECT  102.412 1.728 102.604 27.96 ;
     RECT  102.581 29.04 102.899 29.064 ;
     RECT  102.604 20.832 103.597 27.96 ;
     RECT  102.604 1.728 103.669 3.096 ;
     RECT  103.597 20.832 103.681 28.488 ;
     RECT  103.681 20.832 103.955 27.624 ;
     RECT  103.909 29.04 104.051 29.064 ;
     RECT  103.669 1.728 104.821 3.144 ;
     RECT  102.604 4.224 104.821 4.248 ;
     RECT  103.955 27.36 104.821 27.624 ;
     RECT  103.955 20.832 104.965 26.232 ;
     RECT  104.821 27.36 104.965 28.248 ;
     RECT  104.821 1.728 105.008 4.248 ;
     RECT  102.604 6 105.008 6.024 ;
     RECT  104.965 20.832 105.008 28.248 ;
     RECT  103.993 30.192 105.205 30.216 ;
     RECT  105.008 1.728 105.289 28.248 ;
     RECT  105.289 1.632 105.304 28.248 ;
     RECT  105.304 1.632 105.443 3.144 ;
     RECT  105.304 20.832 105.493 28.248 ;
     RECT  105.493 20.832 105.683 29.064 ;
     RECT  105.683 28.944 105.779 29.064 ;
     RECT  105.304 4.224 105.977 6.024 ;
     RECT  105.205 30.048 106.069 30.216 ;
     RECT  106.069 29.616 106.193 30.216 ;
     RECT  105.443 1.728 106.297 3.144 ;
     RECT  105.977 4.224 106.297 4.248 ;
     RECT  105.683 20.832 106.625 27.624 ;
     RECT  106.625 20.928 107.333 27.624 ;
     RECT  107.333 20.928 107.593 28.488 ;
     RECT  107.593 20.928 107.699 29.064 ;
     RECT  106.297 1.728 107.708 4.248 ;
     RECT  105.977 6 107.708 6.024 ;
     RECT  107.699 20.928 107.708 28.092 ;
     RECT  107.461 0.144 107.747 0.168 ;
     RECT  107.708 1.728 107.812 28.092 ;
     RECT  106.193 30.048 107.941 30.216 ;
     RECT  107.812 1.728 108.004 27.822 ;
     RECT  107.941 29.424 108.275 30.216 ;
     RECT  108.275 29.52 108.317 30.216 ;
     RECT  108.853 0.576 108.965 0.6 ;
     RECT  108.004 1.728 108.965 4.248 ;
     RECT  108.004 13.104 109.037 13.128 ;
     RECT  108.317 30.048 109.139 30.216 ;
     RECT  108.965 1.728 109.361 3.096 ;
     RECT  109.525 29.04 109.613 29.064 ;
     RECT  109.429 12.864 110.005 12.888 ;
     RECT  110.005 12.864 110.101 13.08 ;
     RECT  109.139 30.192 110.149 30.216 ;
     RECT  110.101 12.864 110.197 13.656 ;
     RECT  110.149 30.048 110.197 30.216 ;
     RECT  108.004 20.928 110.221 27.624 ;
     RECT  110.245 0.144 110.257 0.168 ;
     RECT  110.197 12.816 110.285 13.656 ;
     RECT  109.361 1.728 110.408 3.048 ;
     RECT  108.965 4.224 110.408 4.248 ;
     RECT  108.004 6 110.408 6.024 ;
     RECT  110.285 12.528 110.408 13.656 ;
     RECT  110.221 20.928 110.408 27.672 ;
     RECT  110.257 0.144 110.483 0.552 ;
     RECT  110.197 29.952 110.579 30.216 ;
     RECT  110.483 0.528 110.627 0.552 ;
     RECT  110.408 1.728 110.677 28.092 ;
     RECT  110.677 1.728 110.704 28.536 ;
     RECT  110.704 20.928 110.845 28.536 ;
     RECT  110.845 27.456 111.013 28.536 ;
     RECT  111.013 27.456 111.155 29.064 ;
     RECT  110.704 1.728 111.491 2.904 ;
     RECT  110.704 12.528 111.629 13.656 ;
     RECT  111.491 1.776 111.841 2.904 ;
     RECT  110.845 20.928 111.841 26.376 ;
     RECT  111.155 27.456 111.841 28.2 ;
     RECT  111.841 1.776 111.925 3.096 ;
     RECT  110.579 30.096 111.973 30.216 ;
     RECT  111.925 1.776 112.453 3 ;
     RECT  111.629 12.528 112.669 13.608 ;
     RECT  111.841 20.928 112.837 28.2 ;
     RECT  111.973 30.048 112.837 30.216 ;
     RECT  112.453 1.728 112.921 3 ;
     RECT  112.921 1.728 112.949 3.096 ;
     RECT  112.949 1.728 113.108 3.144 ;
     RECT  110.704 4.224 113.108 4.248 ;
     RECT  110.704 6 113.108 6.024 ;
     RECT  112.669 12 113.108 13.608 ;
     RECT  112.837 20.928 113.108 30.216 ;
     RECT  113.108 1.728 113.171 30.216 ;
     RECT  113.171 1.728 113.404 29.064 ;
     RECT  113.653 0.144 113.795 0.168 ;
     RECT  113.404 12.528 113.825 13.608 ;
     RECT  113.404 20.832 114.257 29.064 ;
     RECT  113.171 30.048 114.277 30.216 ;
     RECT  114.257 20.832 114.563 28.2 ;
     RECT  113.825 12.528 114.613 13.56 ;
     RECT  114.563 20.832 114.653 26.616 ;
     RECT  114.613 12 114.697 13.56 ;
     RECT  114.697 12.528 114.761 13.56 ;
     RECT  114.761 12.576 114.803 13.56 ;
     RECT  114.277 29.904 114.803 30.216 ;
     RECT  114.803 30.048 114.995 30.216 ;
     RECT  114.563 27.648 115.429 28.2 ;
     RECT  115.525 0.144 115.667 0.168 ;
     RECT  115.429 27.648 115.693 28.536 ;
     RECT  114.653 20.928 115.729 26.616 ;
     RECT  115.693 27.648 115.729 29.064 ;
     RECT  113.404 1.728 115.808 3.144 ;
     RECT  113.404 4.224 115.808 4.248 ;
     RECT  113.404 6 115.808 6.024 ;
     RECT  114.803 12.864 115.808 13.56 ;
     RECT  115.729 20.928 115.808 29.064 ;
     RECT  115.808 1.728 116.104 29.064 ;
     RECT  114.995 30.192 116.149 30.216 ;
     RECT  116.104 1.728 116.165 3.096 ;
     RECT  116.104 12.768 116.243 13.368 ;
     RECT  116.243 12.768 116.291 12.888 ;
     RECT  116.291 12.864 116.309 12.888 ;
     RECT  116.104 20.928 116.581 29.064 ;
     RECT  116.149 30.048 116.581 30.216 ;
     RECT  116.581 20.928 116.675 30.216 ;
     RECT  116.675 29.952 116.723 30.216 ;
     RECT  116.165 1.728 117.341 2.904 ;
     RECT  117.341 1.728 117.421 2.952 ;
     RECT  117.421 1.68 117.539 2.952 ;
     RECT  116.675 20.928 118.309 28.536 ;
     RECT  117.539 1.728 118.357 2.952 ;
     RECT  116.104 4.224 118.357 4.248 ;
     RECT  118.309 20.928 118.397 28.968 ;
     RECT  118.357 1.728 118.508 4.248 ;
     RECT  116.104 6 118.508 6.024 ;
     RECT  118.397 20.928 118.508 28.536 ;
     RECT  118.508 1.728 118.54 28.536 ;
     RECT  118.261 0.144 118.547 0.168 ;
     RECT  116.723 30.048 118.597 30.216 ;
     RECT  118.54 1.728 118.804 28.2 ;
     RECT  118.597 29.76 118.931 30.216 ;
     RECT  118.804 12 118.937 12.024 ;
     RECT  118.931 29.856 118.979 30.216 ;
     RECT  118.804 13.056 119.797 13.08 ;
     RECT  118.804 14.16 119.797 14.184 ;
     RECT  119.797 13.056 119.893 14.184 ;
     RECT  119.893 13.056 120.013 14.232 ;
     RECT  118.979 29.904 120.083 30.216 ;
     RECT  120.013 12.528 120.097 14.232 ;
     RECT  120.097 13.056 120.161 14.232 ;
     RECT  118.804 1.728 121.208 3.144 ;
     RECT  118.804 4.224 121.208 4.248 ;
     RECT  118.804 6 121.208 6.024 ;
     RECT  120.161 13.104 121.208 14.232 ;
     RECT  118.804 20.928 121.208 28.2 ;
     RECT  120.083 30 121.235 30.216 ;
     RECT  121.208 1.728 121.333 28.2 ;
     RECT  121.333 1.728 121.504 28.248 ;
     RECT  121.504 20.832 121.619 28.248 ;
     RECT  121.235 30.048 122.341 30.216 ;
     RECT  122.341 29.616 122.465 30.216 ;
     RECT  121.619 20.832 122.573 28.2 ;
     RECT  121.504 1.728 123.109 2.904 ;
     RECT  123.109 1.152 123.193 2.904 ;
     RECT  122.533 12 123.721 12.024 ;
     RECT  121.504 13.008 123.721 14.232 ;
     RECT  122.573 20.928 123.757 28.2 ;
     RECT  123.193 1.728 123.781 2.904 ;
     RECT  123.757 20.928 123.841 28.392 ;
     RECT  123.781 1.728 123.908 3.096 ;
     RECT  121.504 4.224 123.908 4.248 ;
     RECT  121.504 6 123.908 6.024 ;
     RECT  123.721 12 123.908 14.232 ;
     RECT  123.721 17.232 123.908 17.256 ;
     RECT  123.841 20.928 123.908 28.296 ;
     RECT  123.908 1.728 123.971 28.296 ;
     RECT  123.781 0.144 124.163 0.168 ;
     RECT  123.971 1.728 124.204 28.2 ;
     RECT  124.204 1.728 124.885 3.144 ;
     RECT  124.204 26.16 124.933 28.2 ;
     RECT  122.465 30.048 124.933 30.216 ;
     RECT  124.204 12 125.065 14.232 ;
     RECT  124.204 20.928 125.197 21.144 ;
     RECT  124.204 22.464 125.197 24.936 ;
     RECT  124.933 26.16 125.237 30.216 ;
     RECT  125.237 26.16 125.269 28.488 ;
     RECT  125.237 29.616 125.273 30.216 ;
     RECT  124.204 6 125.305 6.024 ;
     RECT  125.305 6 125.417 6.552 ;
     RECT  125.197 20.928 125.629 24.936 ;
     RECT  124.885 1.728 125.909 2.856 ;
     RECT  125.845 0.144 125.987 0.168 ;
     RECT  125.629 20.928 126.097 25.128 ;
     RECT  125.269 26.112 126.097 28.488 ;
     RECT  125.065 12.48 126.449 14.232 ;
     RECT  125.273 30.192 126.517 30.216 ;
     RECT  125.909 1.728 126.608 3.048 ;
     RECT  124.204 4.224 126.608 4.248 ;
     RECT  125.417 6 126.608 6.024 ;
     RECT  126.449 12 126.608 14.232 ;
     RECT  126.097 20.928 126.608 28.488 ;
     RECT  126.493 0.576 126.611 0.6 ;
     RECT  126.608 1.728 126.613 28.488 ;
     RECT  126.613 1.728 126.745 29.064 ;
     RECT  126.517 30.048 126.745 30.216 ;
     RECT  126.745 1.728 126.904 30.216 ;
     RECT  126.904 26.304 127.091 30.216 ;
     RECT  127.091 26.304 127.181 29.112 ;
     RECT  127.181 26.496 127.619 29.112 ;
     RECT  127.619 26.688 127.685 29.112 ;
     RECT  126.904 20.928 127.933 22.2 ;
     RECT  126.904 23.376 127.933 24.744 ;
     RECT  127.933 20.928 128.005 24.744 ;
     RECT  128.005 20.928 128.017 25.08 ;
     RECT  126.904 12 128.149 14.184 ;
     RECT  128.149 12 128.677 14.232 ;
     RECT  126.904 1.728 128.797 2.952 ;
     RECT  128.017 23.664 128.905 25.08 ;
     RECT  127.685 27.072 129.107 29.112 ;
     RECT  129.107 27.072 129.305 28.248 ;
     RECT  128.797 1.728 129.308 3.096 ;
     RECT  126.904 4.224 129.308 4.248 ;
     RECT  126.904 6 129.308 6.024 ;
     RECT  128.677 11.952 129.308 14.232 ;
     RECT  128.017 20.928 129.308 22.2 ;
     RECT  128.905 23.664 129.308 25.128 ;
     RECT  129.305 27.072 129.308 28.2 ;
     RECT  129.308 1.728 129.604 28.2 ;
     RECT  129.604 27.072 129.737 28.2 ;
     RECT  129.604 11.664 129.779 14.184 ;
     RECT  129.737 27.456 129.845 28.2 ;
     RECT  129.779 12 129.875 14.184 ;
     RECT  129.845 27.696 129.881 28.2 ;
     RECT  129.604 23.664 129.961 23.976 ;
     RECT  129.875 12 129.971 13.656 ;
     RECT  129.971 12.528 129.989 13.656 ;
     RECT  127.091 30.192 130.069 30.216 ;
     RECT  130.069 30.096 130.115 30.216 ;
     RECT  129.881 28.176 130.211 28.2 ;
     RECT  130.115 30.096 130.355 30.12 ;
     RECT  129.989 13.104 130.357 13.656 ;
     RECT  130.357 13.632 130.421 13.656 ;
     RECT  129.604 20.832 130.565 20.952 ;
     RECT  129.604 1.728 130.601 3.048 ;
     RECT  130.601 1.728 131.749 2.856 ;
     RECT  129.604 4.224 131.749 4.248 ;
     RECT  131.713 0.528 131.785 0.552 ;
     RECT  131.749 1.728 131.785 4.248 ;
     RECT  131.785 0.528 132.008 4.248 ;
     RECT  129.604 6 132.008 6.024 ;
     RECT  130.565 20.928 132.008 20.952 ;
     RECT  129.961 23.664 132.008 23.688 ;
     RECT  132.008 0.528 132.112 28.092 ;
     RECT  132.112 0.528 132.179 27.822 ;
     RECT  132.179 1.104 132.304 27.822 ;
     RECT  132.304 1.104 132.323 4.248 ;
     RECT  132.323 1.728 132.797 4.248 ;
     RECT  132.613 0.096 132.899 0.12 ;
     RECT  132.797 1.728 133.981 2.856 ;
     RECT  133.981 1.728 134.161 3.048 ;
     RECT  134.161 1.728 134.708 3.192 ;
     RECT  132.797 4.224 134.708 4.248 ;
     RECT  132.304 6 134.708 6.024 ;
     RECT  132.304 20.928 134.708 20.952 ;
     RECT  132.304 23.664 134.708 23.688 ;
     RECT  134.708 1.728 134.812 28.092 ;
     RECT  134.812 1.728 135.004 27.822 ;
     RECT  135.125 0.576 135.209 0.6 ;
     RECT  135.004 1.728 135.997 2.904 ;
     RECT  135.997 1.728 136.133 2.952 ;
     RECT  136.133 1.728 136.217 3.096 ;
     RECT  136.217 1.728 136.645 2.952 ;
     RECT  136.645 1.152 136.787 2.952 ;
     RECT  137.221 0.144 137.363 0.168 ;
     RECT  136.787 1.728 137.408 2.952 ;
     RECT  135.004 4.224 137.408 4.248 ;
     RECT  135.004 6 137.408 6.024 ;
     RECT  135.004 20.928 137.408 20.952 ;
     RECT  135.004 23.664 137.408 23.688 ;
     RECT  137.408 1.728 137.512 28.092 ;
     RECT  137.512 1.728 137.704 27.822 ;
     RECT  137.704 20.928 138.017 20.952 ;
     RECT  137.704 1.728 138.949 3.096 ;
     RECT  138.949 1.728 140.108 3.144 ;
     RECT  137.704 4.224 140.108 4.248 ;
     RECT  137.704 6 140.108 6.024 ;
     RECT  137.704 23.664 140.108 23.688 ;
     RECT  140.108 1.728 140.212 28.092 ;
     RECT  140.212 1.728 140.404 27.822 ;
     RECT  140.404 1.728 141.757 3.144 ;
     RECT  141.757 1.728 141.841 3.192 ;
     RECT  141.841 1.728 142.808 3.096 ;
     RECT  140.404 4.224 142.808 4.248 ;
     RECT  140.404 6 142.808 6.024 ;
     RECT  140.404 23.664 142.808 23.688 ;
     RECT  142.808 1.728 142.912 28.092 ;
     RECT  142.693 0.144 142.979 0.168 ;
     RECT  142.912 1.728 143.104 27.822 ;
     RECT  143.104 1.728 144.085 2.904 ;
     RECT  143.104 6 144.101 6.024 ;
     RECT  144.085 1.728 144.745 3.096 ;
     RECT  144.745 1.728 145.508 3.192 ;
     RECT  143.104 4.224 145.508 4.248 ;
     RECT  145.508 1.728 145.612 28.092 ;
     RECT  145.612 1.728 145.804 27.822 ;
     RECT  145.804 6.72 146.333 6.84 ;
     RECT  145.804 4.224 146.477 4.248 ;
     RECT  146.333 6.72 146.477 6.744 ;
     RECT  145.804 1.728 147.397 2.904 ;
     RECT  147.397 1.728 147.661 3.096 ;
     RECT  147.661 1.152 147.745 3.096 ;
     RECT  147.745 1.728 148.208 3.096 ;
     RECT  148.208 1.728 148.312 28.092 ;
     RECT  148.312 1.728 148.504 27.822 ;
     RECT  148.504 1.728 149.185 3.192 ;
     RECT  149.185 1.728 149.897 3.144 ;
     RECT  149.897 1.728 149.933 3.048 ;
     RECT  149.933 1.728 150.908 2.616 ;
     RECT  150.908 1.728 151.012 28.092 ;
     RECT  151.012 1.728 151.204 27.822 ;
     RECT  151.204 1.728 152.201 3.048 ;
     RECT  152.201 1.776 153.445 3.048 ;
     RECT  153.445 1.728 153.608 3.048 ;
     RECT  153.608 1.728 153.712 28.092 ;
     RECT  153.712 1.728 153.904 27.822 ;
     RECT  153.904 1.728 154.885 2.664 ;
     RECT  154.885 1.728 155.008 2.904 ;
     RECT  155.008 1.728 155.173 2.952 ;
     RECT  155.173 1.728 156.149 3.048 ;
     RECT  156.149 1.728 156.308 3.096 ;
     RECT  156.308 1.728 156.412 28.092 ;
     RECT  156.412 1.728 156.604 27.822 ;
     RECT  156.325 0.144 156.755 0.168 ;
     RECT  156.604 1.728 156.755 3.048 ;
     RECT  156.755 1.728 157.241 2.952 ;
     RECT  157.241 2.016 157.765 2.952 ;
     RECT  157.765 2.016 157.853 3.144 ;
     RECT  157.853 2.016 158.341 2.952 ;
     RECT  158.341 1.728 158.821 2.952 ;
     RECT  158.821 0.144 158.963 0.168 ;
     RECT  158.821 1.728 159.008 3.048 ;
     RECT  159.008 1.728 159.112 28.092 ;
     RECT  159.061 0.528 159.185 0.552 ;
     RECT  159.112 1.728 159.304 27.822 ;
     RECT  159.304 1.728 160.337 3.096 ;
     RECT  160.337 1.728 161.557 2.952 ;
     RECT  161.557 1.728 161.708 3.048 ;
     RECT  161.708 1.728 161.812 28.092 ;
     RECT  161.557 0.144 161.843 0.168 ;
     RECT  161.812 1.728 162.004 27.822 ;
     RECT  162.004 1.728 163.069 3.096 ;
     RECT  163.069 1.728 164.408 3.24 ;
     RECT  164.408 1.728 164.512 28.092 ;
     RECT  164.293 0.144 164.579 0.168 ;
     RECT  164.512 1.728 164.704 27.822 ;
     RECT  164.704 1.728 165.449 3.192 ;
     RECT  165.449 1.728 166.693 2.904 ;
     RECT  166.693 1.728 166.949 2.952 ;
     RECT  166.949 1.728 167.108 3.096 ;
     RECT  167.108 1.728 167.212 28.092 ;
     RECT  167.212 1.728 167.404 27.822 ;
     RECT  167.413 0.144 167.555 0.168 ;
     RECT  167.404 1.728 168.757 3.384 ;
     RECT  169.117 0.048 169.189 0.072 ;
     RECT  169.189 0.048 169.225 0.552 ;
     RECT  168.757 1.728 169.225 3.432 ;
     RECT  169.225 0.048 169.808 3.432 ;
     RECT  169.808 0.048 169.912 28.092 ;
     RECT  169.912 0.048 170.104 27.822 ;
     RECT  170.104 2.88 170.281 4.584 ;
     RECT  170.281 4.128 170.339 4.584 ;
     RECT  170.339 4.128 170.435 4.152 ;
     RECT  170.104 0.048 170.915 1.704 ;
     RECT  170.915 0.048 171.059 0.552 ;
     RECT  170.281 2.88 171.116 2.904 ;
     RECT  171.116 2.832 171.203 2.904 ;
     RECT  171.203 2.88 171.361 2.904 ;
     RECT  171.421 3.408 171.635 3.48 ;
     RECT  170.915 1.68 171.779 1.704 ;
     RECT  171.059 0.048 171.893 0.168 ;
     RECT  171.893 0.144 171.937 0.168 ;
     RECT  171.635 3.456 172.067 3.48 ;
    LAYER M5 ;
     RECT  90.912 0.016 91.08 0.131 ;
     RECT  87.792 0.016 89.832 0.611 ;
     RECT  92.16 0.016 130.344 0.611 ;
     RECT  87.936 0.611 89.832 1.763 ;
     RECT  131.424 0.016 172.056 1.763 ;
     RECT  88.08 1.763 89.4 1.811 ;
     RECT  92.304 0.611 130.344 1.811 ;
     RECT  88.224 1.811 89.112 1.859 ;
     RECT  93.168 1.811 130.056 1.859 ;
     RECT  131.856 1.763 172.056 1.859 ;
     RECT  131.856 1.859 149.88 1.907 ;
     RECT  150.864 1.859 172.056 1.907 ;
     RECT  93.888 1.859 94.776 2.099 ;
     RECT  131.856 1.907 133.608 2.099 ;
     RECT  94.032 2.099 94.512 2.147 ;
     RECT  2.4 2.137 2.52 2.151 ;
     RECT  5.1 2.137 5.22 2.151 ;
     RECT  7.8 2.137 7.92 2.151 ;
     RECT  10.5 2.137 10.62 2.151 ;
     RECT  13.2 2.137 13.32 2.151 ;
     RECT  15.9 2.137 16.02 2.151 ;
     RECT  18.6 2.137 18.72 2.151 ;
     RECT  21.3 2.137 21.42 2.151 ;
     RECT  24 2.137 24.12 2.151 ;
     RECT  26.7 2.137 26.82 2.151 ;
     RECT  29.4 2.137 29.52 2.151 ;
     RECT  32.1 2.137 32.22 2.151 ;
     RECT  34.8 2.137 34.92 2.151 ;
     RECT  37.5 2.137 37.62 2.151 ;
     RECT  40.2 2.137 40.32 2.151 ;
     RECT  42.9 2.137 43.02 2.151 ;
     RECT  45.6 2.137 45.72 2.151 ;
     RECT  48.3 2.137 48.42 2.151 ;
     RECT  51 2.137 51.12 2.151 ;
     RECT  53.7 2.137 53.82 2.151 ;
     RECT  56.4 2.137 56.52 2.151 ;
     RECT  59.1 2.137 59.22 2.151 ;
     RECT  61.8 2.137 61.92 2.151 ;
     RECT  64.5 2.137 64.62 2.151 ;
     RECT  67.2 2.137 67.32 2.151 ;
     RECT  69.9 2.137 70.02 2.151 ;
     RECT  72.6 2.137 72.72 2.151 ;
     RECT  75.3 2.137 75.42 2.151 ;
     RECT  78 2.137 78.12 2.151 ;
     RECT  80.7 2.137 80.82 2.151 ;
     RECT  83.4 2.137 83.52 2.151 ;
     RECT  86.1 2.137 86.22 2.151 ;
     RECT  96.768 1.859 130.056 2.243 ;
     RECT  133.296 2.099 133.32 2.243 ;
     RECT  150.9 1.907 168.024 2.243 ;
     RECT  131.856 2.099 132.312 2.291 ;
     RECT  134.592 1.907 149.88 2.291 ;
     RECT  169.008 1.907 172.056 2.291 ;
     RECT  91.5 2.137 91.812 2.773 ;
     RECT  98.496 2.243 130.056 2.773 ;
     RECT  96.768 2.243 97.32 2.915 ;
     RECT  98.496 2.773 130.344 2.915 ;
     RECT  134.592 2.291 143.112 2.915 ;
     RECT  144.096 2.291 149.88 2.915 ;
     RECT  150.9 2.243 153.912 2.915 ;
     RECT  154.896 2.243 168.024 2.915 ;
     RECT  169.248 2.291 172.056 2.915 ;
     RECT  117.36 2.915 117.384 2.963 ;
     RECT  136.032 2.915 143.112 2.963 ;
     RECT  155.04 2.915 165.288 2.963 ;
     RECT  166.704 2.915 168.024 2.963 ;
     RECT  137.4 2.963 140.412 3.011 ;
     RECT  98.496 2.915 103.704 3.059 ;
     RECT  107.472 2.915 116.28 3.059 ;
     RECT  134.592 2.915 135.012 3.059 ;
     RECT  139.056 3.011 140.412 3.059 ;
     RECT  150.9 2.915 152.184 3.059 ;
     RECT  153.312 2.915 153.912 3.059 ;
     RECT  155.184 2.963 156.744 3.059 ;
     RECT  158.832 2.963 160.104 3.059 ;
     RECT  161.568 2.963 165.288 3.059 ;
     RECT  98.496 3.059 98.52 3.107 ;
     RECT  99.6 3.059 103.704 3.107 ;
     RECT  107.472 3.059 109.32 3.107 ;
     RECT  118.368 2.915 121.512 3.107 ;
     RECT  136.176 2.963 136.2 3.107 ;
     RECT  137.4 3.011 137.928 3.107 ;
     RECT  141.792 2.963 143.112 3.107 ;
     RECT  144.096 2.915 145.812 3.107 ;
     RECT  147.408 2.915 149.88 3.107 ;
     RECT  156.192 3.059 156.612 3.107 ;
     RECT  159 3.059 160.104 3.107 ;
     RECT  161.7 3.059 165.288 3.107 ;
     RECT  166.992 2.963 167.412 3.107 ;
     RECT  103.68 3.107 103.704 3.155 ;
     RECT  104.832 2.915 105.432 3.155 ;
     RECT  139.056 3.059 139.08 3.155 ;
     RECT  148.2 3.107 149.88 3.155 ;
     RECT  157.776 2.963 157.8 3.155 ;
     RECT  96.9 2.915 97.32 3.203 ;
     RECT  141.792 3.107 141.816 3.203 ;
     RECT  144.816 3.107 145.812 3.203 ;
     RECT  148.2 3.155 149.16 3.203 ;
     RECT  164.4 3.107 165.288 3.203 ;
     RECT  106.416 2.915 106.44 3.251 ;
     RECT  104.832 3.155 105.312 3.347 ;
     RECT  107.472 3.107 108.012 3.347 ;
     RECT  118.368 3.107 118.812 3.347 ;
     RECT  101.376 3.107 102.612 3.395 ;
     RECT  169.248 2.915 170.424 3.443 ;
     RECT  171.6 2.915 172.056 3.443 ;
     RECT  172.032 3.443 172.056 3.491 ;
     RECT  169.8 3.443 170.424 4.163 ;
     RECT  169.8 4.163 170.328 4.595 ;
     RECT  88.8 1.859 89.112 4.981 ;
     RECT  88.8 4.981 89.208 5.123 ;
     RECT  91.248 2.773 91.812 5.365 ;
     RECT  91.152 5.365 91.812 5.653 ;
     RECT  90.624 5.653 91.812 5.797 ;
     RECT  90.624 5.797 92.04 5.843 ;
     RECT  120.048 3.107 121.512 12.563 ;
     RECT  110.304 3.059 116.28 12.803 ;
     RECT  110.304 12.803 116.232 12.805 ;
     RECT  110.208 12.805 116.232 12.853 ;
     RECT  120.912 12.563 121.512 12.997 ;
     RECT  122.976 2.915 130.344 12.997 ;
     RECT  118.5 3.347 118.812 13.045 ;
     RECT  109.44 12.853 116.232 13.139 ;
     RECT  120.912 12.997 130.344 13.139 ;
     RECT  91.152 5.843 92.04 13.285 ;
     RECT  115.8 13.139 116.232 13.379 ;
     RECT  118.5 13.045 118.968 13.621 ;
     RECT  120.912 13.139 129.912 13.715 ;
     RECT  118.5 13.621 119.832 14.197 ;
     RECT  90.24 13.285 92.04 14.867 ;
     RECT  102.3 3.395 102.612 19.909 ;
     RECT  87.696 14.773 87.72 20.675 ;
     RECT  75.3 2.151 75.612 20.725 ;
     RECT  105 3.347 105.312 21.493 ;
     RECT  102 19.909 102.612 21.539 ;
     RECT  74.64 20.725 75.612 21.541 ;
     RECT  80.7 2.151 81.012 21.541 ;
     RECT  88.8 5.123 89.112 21.637 ;
     RECT  74.64 21.541 76.44 21.971 ;
     RECT  94.2 2.147 94.512 22.021 ;
     RECT  51 2.151 51.312 22.165 ;
     RECT  96.9 3.203 97.212 22.165 ;
     RECT  51 22.165 51.816 22.213 ;
     RECT  67.2 2.151 67.512 22.213 ;
     RECT  68.88 21.637 68.904 22.213 ;
     RECT  69.9 2.151 70.212 22.213 ;
     RECT  96.24 22.165 97.212 22.213 ;
     RECT  98.208 21.397 98.232 22.213 ;
     RECT  88.176 21.637 89.112 22.499 ;
     RECT  118.5 14.197 119.928 22.549 ;
     RECT  105 21.493 106.296 22.693 ;
     RECT  107.7 3.347 108.012 22.693 ;
     RECT  53.7 2.151 54.012 22.741 ;
     RECT  55.008 21.541 55.032 22.741 ;
     RECT  61.8 2.151 62.112 22.741 ;
     RECT  61.2 22.741 62.112 22.789 ;
     RECT  67.2 22.213 70.212 22.789 ;
     RECT  109.44 13.139 114.696 22.835 ;
     RECT  59.1 2.151 59.412 22.837 ;
     RECT  51 22.213 52.68 22.885 ;
     RECT  53.7 22.741 55.032 22.885 ;
     RECT  83.4 2.151 83.712 22.885 ;
     RECT  67.056 22.789 70.212 22.981 ;
     RECT  67.056 22.981 70.92 23.029 ;
     RECT  61.008 22.789 62.112 23.173 ;
     RECT  64.5 2.151 64.812 23.269 ;
     RECT  80.7 21.541 81.72 23.269 ;
     RECT  91.5 14.867 92.04 23.315 ;
     RECT  51 22.885 55.032 23.317 ;
     RECT  61.008 23.173 62.232 23.317 ;
     RECT  67.008 23.029 70.92 23.317 ;
     RECT  72.6 2.151 72.912 23.317 ;
     RECT  94.08 22.021 94.512 23.317 ;
     RECT  96.24 22.213 98.232 23.317 ;
     RECT  118.272 22.549 119.928 23.317 ;
     RECT  121.2 13.715 122.376 23.317 ;
     RECT  51 23.317 55.272 23.365 ;
     RECT  56.4 2.151 56.712 23.365 ;
     RECT  78 2.151 78.312 23.365 ;
     RECT  103.68 22.789 103.704 23.365 ;
     RECT  105 22.693 108.012 23.365 ;
     RECT  112.224 22.835 114.696 23.365 ;
     RECT  115.8 13.379 116.112 23.365 ;
     RECT  80.7 23.269 82.056 23.411 ;
     RECT  90.24 14.867 90.312 23.411 ;
     RECT  110.112 22.835 111.144 23.411 ;
     RECT  121.008 23.317 122.376 23.411 ;
     RECT  51 23.365 56.712 23.413 ;
     RECT  83.4 22.885 84.36 23.413 ;
     RECT  110.16 23.411 111.144 23.507 ;
     RECT  51 23.413 57.336 23.557 ;
     RECT  58.608 22.837 59.412 23.557 ;
     RECT  96.24 23.317 98.616 23.749 ;
     RECT  102.144 21.539 102.612 23.749 ;
     RECT  103.68 23.365 103.896 23.749 ;
     RECT  74.64 21.971 75.612 23.797 ;
     RECT  51 23.557 59.412 23.845 ;
     RECT  86.1 2.151 86.412 23.845 ;
     RECT  112.224 23.365 116.568 23.893 ;
     RECT  117.984 23.317 119.928 23.893 ;
     RECT  50.208 23.845 59.412 23.941 ;
     RECT  60.432 23.317 62.232 23.941 ;
     RECT  83.136 23.413 84.648 23.941 ;
     RECT  110.256 23.507 111.144 23.941 ;
     RECT  112.224 23.893 119.928 23.941 ;
     RECT  67.008 23.317 72.912 23.987 ;
     RECT  86.1 23.845 86.616 23.987 ;
     RECT  121.008 23.411 122.328 23.987 ;
     RECT  123.648 13.715 129.912 23.987 ;
     RECT  102.144 23.749 103.896 23.989 ;
     RECT  110.256 23.941 119.928 24.035 ;
     RECT  74.256 23.797 75.612 24.181 ;
     RECT  76.848 23.365 76.872 24.181 ;
     RECT  82.8 23.941 84.648 24.325 ;
     RECT  86.1 23.987 86.412 24.325 ;
     RECT  95.904 23.749 98.616 24.325 ;
     RECT  99.6 3.107 99.912 24.325 ;
     RECT  110.304 24.035 119.928 24.373 ;
     RECT  121.008 23.987 122.28 24.373 ;
     RECT  67.008 23.987 68.904 24.517 ;
     RECT  69.9 23.987 72.912 24.517 ;
     RECT  74.256 24.181 76.872 24.517 ;
     RECT  78 23.365 78.984 24.517 ;
     RECT  80.7 23.411 81.816 24.517 ;
     RECT  82.8 24.325 86.412 24.517 ;
     RECT  90.288 23.411 90.312 24.563 ;
     RECT  123.648 23.987 127.032 24.563 ;
     RECT  110.304 24.373 122.28 24.611 ;
     RECT  128.16 23.987 129.612 24.611 ;
     RECT  45.6 2.151 45.912 24.613 ;
     RECT  101.376 23.989 103.896 24.613 ;
     RECT  104.88 23.365 108.792 24.613 ;
     RECT  123.648 24.563 124.584 24.707 ;
     RECT  91.5 23.315 91.812 24.949 ;
     RECT  63.696 23.269 64.968 24.997 ;
     RECT  66.192 24.517 68.904 24.997 ;
     RECT  80.7 24.517 86.412 24.997 ;
     RECT  45.6 24.613 46.872 25.045 ;
     RECT  95.904 24.325 99.912 25.045 ;
     RECT  101.376 24.613 108.792 25.045 ;
     RECT  69.9 24.517 73.128 25.093 ;
     RECT  74.256 24.517 78.984 25.093 ;
     RECT  80.4 24.997 86.412 25.093 ;
     RECT  125.808 24.563 126.912 25.139 ;
     RECT  128.928 24.611 129.612 25.139 ;
     RECT  63.696 24.997 68.904 25.141 ;
     RECT  69.9 25.093 79.128 25.141 ;
     RECT  95.904 25.045 108.792 25.141 ;
     RECT  110.304 24.611 119.64 25.141 ;
     RECT  45.024 25.045 46.872 25.187 ;
     RECT  91.392 24.949 91.812 25.189 ;
     RECT  50.208 23.941 62.232 25.381 ;
     RECT  123.648 24.707 124.212 25.429 ;
     RECT  63.696 25.141 79.128 25.525 ;
     RECT  80.112 25.093 87.144 25.525 ;
     RECT  50.208 25.381 62.664 25.621 ;
     RECT  63.696 25.525 87.144 25.621 ;
     RECT  93.312 23.317 94.512 25.621 ;
     RECT  95.904 25.141 119.64 25.621 ;
     RECT  120.72 24.611 122.28 25.621 ;
     RECT  88.8 22.499 89.112 25.669 ;
     RECT  91.392 25.189 92.04 25.669 ;
     RECT  93.312 25.621 122.28 25.669 ;
     RECT  123.6 25.429 124.212 25.669 ;
     RECT  45.024 25.187 45.912 25.715 ;
     RECT  50.208 25.621 87.144 25.717 ;
     RECT  88.8 25.669 89.352 25.717 ;
     RECT  91.104 25.669 124.212 25.717 ;
     RECT  50.208 25.717 89.352 25.861 ;
     RECT  42.9 2.151 43.212 26.005 ;
     RECT  48.3 2.151 48.612 26.101 ;
     RECT  125.28 26.101 125.304 26.149 ;
     RECT  90.528 25.717 124.212 26.197 ;
     RECT  125.184 26.149 125.304 26.197 ;
     RECT  48.3 26.101 48.984 26.293 ;
     RECT  49.968 25.861 89.352 26.293 ;
     RECT  126.6 25.139 126.912 26.293 ;
     RECT  90.528 26.197 125.304 26.485 ;
     RECT  126.6 26.293 127.032 26.485 ;
     RECT  48.3 26.293 89.352 26.819 ;
     RECT  90.528 26.485 127.608 27.253 ;
     RECT  45.6 25.715 45.912 27.301 ;
     RECT  90.528 27.253 127.704 27.349 ;
     RECT  129.3 25.139 129.612 27.637 ;
     RECT  49.968 26.819 89.112 27.877 ;
     RECT  90.24 27.349 127.704 27.877 ;
     RECT  45.6 27.301 46.584 27.925 ;
     RECT  48.3 26.819 48.984 27.925 ;
     RECT  49.968 27.877 127.704 27.925 ;
     RECT  2.4 2.151 2.712 28.089 ;
     RECT  5.1 2.151 5.412 28.089 ;
     RECT  7.8 2.151 8.112 28.089 ;
     RECT  10.5 2.151 10.812 28.089 ;
     RECT  13.2 2.151 13.512 28.089 ;
     RECT  15.9 2.151 16.212 28.089 ;
     RECT  18.6 2.151 18.912 28.089 ;
     RECT  21.3 2.151 21.612 28.089 ;
     RECT  24 2.151 24.312 28.089 ;
     RECT  26.7 2.151 27.012 28.089 ;
     RECT  29.4 2.151 29.712 28.089 ;
     RECT  32.1 2.151 32.412 28.089 ;
     RECT  34.8 2.151 35.112 28.089 ;
     RECT  37.5 2.151 37.812 28.089 ;
     RECT  40.2 2.151 40.512 28.089 ;
     RECT  132 2.291 132.312 28.089 ;
     RECT  134.7 3.059 135.012 28.089 ;
     RECT  137.4 3.107 137.712 28.089 ;
     RECT  140.1 3.059 140.412 28.089 ;
     RECT  142.8 3.107 143.112 28.089 ;
     RECT  145.5 3.203 145.812 28.089 ;
     RECT  148.2 3.203 148.512 28.089 ;
     RECT  150.9 3.059 151.212 28.089 ;
     RECT  153.6 3.059 153.912 28.089 ;
     RECT  156.3 3.107 156.612 28.089 ;
     RECT  159 3.107 159.312 28.089 ;
     RECT  161.7 3.107 162.012 28.089 ;
     RECT  164.4 3.203 164.712 28.089 ;
     RECT  167.1 3.107 167.412 28.089 ;
     RECT  169.8 4.595 170.112 28.089 ;
     RECT  2.4 28.089 2.52 28.103 ;
     RECT  5.1 28.089 5.22 28.103 ;
     RECT  7.8 28.089 7.92 28.103 ;
     RECT  10.5 28.089 10.62 28.103 ;
     RECT  13.2 28.089 13.32 28.103 ;
     RECT  15.9 28.089 16.02 28.103 ;
     RECT  18.6 28.089 18.72 28.103 ;
     RECT  21.3 28.089 21.42 28.103 ;
     RECT  24 28.089 24.12 28.103 ;
     RECT  26.7 28.089 26.82 28.103 ;
     RECT  29.4 28.089 29.52 28.103 ;
     RECT  32.1 28.089 32.22 28.103 ;
     RECT  34.8 28.089 34.92 28.103 ;
     RECT  37.5 28.089 37.62 28.103 ;
     RECT  40.2 28.089 40.32 28.103 ;
     RECT  42.9 26.005 43.608 28.103 ;
     RECT  48.3 27.925 127.704 28.103 ;
     RECT  128.928 27.637 129.612 28.103 ;
     RECT  132 28.089 132.12 28.103 ;
     RECT  134.7 28.089 134.82 28.103 ;
     RECT  137.4 28.089 137.52 28.103 ;
     RECT  140.1 28.089 140.22 28.103 ;
     RECT  142.8 28.089 142.92 28.103 ;
     RECT  145.5 28.089 145.62 28.103 ;
     RECT  148.2 28.089 148.32 28.103 ;
     RECT  150.9 28.089 151.02 28.103 ;
     RECT  153.6 28.089 153.72 28.103 ;
     RECT  156.3 28.089 156.42 28.103 ;
     RECT  159 28.089 159.12 28.103 ;
     RECT  161.7 28.089 161.82 28.103 ;
     RECT  164.4 28.089 164.52 28.103 ;
     RECT  167.1 28.089 167.22 28.103 ;
     RECT  169.8 28.089 169.92 28.103 ;
     RECT  89.664 28.103 127.704 28.261 ;
     RECT  45.6 27.925 46.728 28.453 ;
     RECT  48.3 28.103 88.584 28.453 ;
     RECT  44.976 28.453 46.872 28.501 ;
     RECT  48.24 28.453 88.584 29.077 ;
     RECT  128.928 28.103 128.952 29.077 ;
     RECT  48.096 29.077 88.584 29.605 ;
     RECT  42.48 28.741 42.504 30.037 ;
     RECT  43.584 28.103 43.608 30.085 ;
     RECT  130.176 28.165 130.2 30.085 ;
     RECT  42.336 30.037 42.6 30.179 ;
     RECT  42.336 30.179 42.504 30.224 ;
     RECT  43.584 30.085 43.848 30.224 ;
     RECT  44.832 28.501 46.872 30.224 ;
     RECT  47.952 29.605 88.584 30.224 ;
     RECT  89.664 28.261 127.848 30.224 ;
     RECT  128.928 29.077 129.096 30.224 ;
     RECT  130.08 30.085 130.344 30.224 ;
     RECT  43.824 30.224 43.848 30.227 ;
     RECT  130.08 30.224 130.104 30.227 ;
     RECT  89.88 0.016 90.864 0.131 ;
     RECT  91.128 0.016 92.112 0.131 ;
     RECT  130.392 0.016 131.376 0.132 ;
     RECT  130.344 0.132 131.424 1.763 ;
     RECT  130.344 1.763 131.856 1.811 ;
     RECT  130.056 1.811 131.856 2.291 ;
     RECT  149.88 1.859 150.864 1.907 ;
     RECT  133.608 1.907 134.592 2.099 ;
     RECT  149.88 1.907 150.9 3.155 ;
     RECT  168.024 1.907 169.008 2.291 ;
     RECT  132.312 2.099 133.296 2.243 ;
     RECT  133.32 2.099 134.592 2.243 ;
     RECT  97.32 2.243 98.496 3.107 ;
     RECT  153.912 2.243 154.896 2.915 ;
     RECT  130.056 2.291 130.344 2.773 ;
     RECT  143.112 2.291 144.096 3.107 ;
     RECT  168.024 2.291 169.248 2.963 ;
     RECT  103.704 2.915 104.832 3.155 ;
     RECT  105.432 2.915 106.416 3.155 ;
     RECT  106.44 2.915 107.472 3.251 ;
     RECT  116.28 2.915 117.36 2.963 ;
     RECT  117.384 2.915 118.368 2.963 ;
     RECT  121.512 2.915 122.976 12.997 ;
     RECT  135.012 2.915 136.032 2.963 ;
     RECT  152.184 2.915 153.312 3.059 ;
     RECT  153.912 2.915 155.04 2.963 ;
     RECT  165.288 2.915 166.704 2.963 ;
     RECT  170.424 2.915 171.6 3.443 ;
     RECT  135.012 2.963 136.176 3.107 ;
     RECT  136.2 2.963 137.4 3.107 ;
     RECT  140.412 2.963 141.792 3.203 ;
     RECT  153.912 2.963 155.184 3.059 ;
     RECT  156.744 2.963 157.776 3.059 ;
     RECT  157.8 2.963 158.832 3.059 ;
     RECT  160.104 2.963 161.568 3.059 ;
     RECT  137.928 3.011 139.056 3.107 ;
     RECT  98.52 3.059 99.6 3.107 ;
     RECT  109.32 3.059 110.304 3.107 ;
     RECT  139.08 3.059 140.1 3.155 ;
     RECT  156.612 3.059 157.776 3.155 ;
     RECT  157.8 3.059 159 3.155 ;
     RECT  99.912 3.107 101.376 3.395 ;
     RECT  102.612 3.107 103.68 3.155 ;
     RECT  118.812 3.107 120.048 12.563 ;
     RECT  137.712 3.107 139.056 3.155 ;
     RECT  141.816 3.107 142.8 3.203 ;
     RECT  105.312 3.155 106.416 3.251 ;
     RECT  89.112 5.123 89.208 5.653 ;
     RECT  89.112 5.653 90.624 5.843 ;
     RECT  118.812 12.563 120.912 13.045 ;
     RECT  108.012 12.853 109.44 22.835 ;
     RECT  118.968 13.045 120.912 13.621 ;
     RECT  114.696 13.139 115.8 23.365 ;
     RECT  89.112 13.285 90.24 23.411 ;
     RECT  119.832 13.621 120.912 13.715 ;
     RECT  119.832 13.715 121.2 14.197 ;
     RECT  122.376 13.715 123.648 23.411 ;
     RECT  119.928 14.197 121.2 23.317 ;
     RECT  86.412 14.773 87.696 20.675 ;
     RECT  87.72 14.773 88.8 20.675 ;
     RECT  90.312 14.867 91.5 24.563 ;
     RECT  88.176 20.675 88.8 21.637 ;
     RECT  97.212 21.397 98.208 22.213 ;
     RECT  98.232 21.397 99.6 23.317 ;
     RECT  106.296 21.493 107.7 22.693 ;
     RECT  54.012 21.541 55.008 22.741 ;
     RECT  55.032 21.541 56.4 23.317 ;
     RECT  67.512 21.637 68.88 22.213 ;
     RECT  68.904 21.637 69.9 22.213 ;
     RECT  75.612 21.971 76.44 23.365 ;
     RECT  52.68 22.213 53.7 22.885 ;
     RECT  102.612 22.789 103.68 23.749 ;
     RECT  103.704 22.789 105 23.365 ;
     RECT  108.012 22.835 110.112 23.365 ;
     RECT  111.144 22.835 112.224 23.941 ;
     RECT  62.232 23.269 63.696 25.381 ;
     RECT  82.056 23.269 83.4 23.411 ;
     RECT  91.812 23.315 92.04 23.317 ;
     RECT  55.272 23.317 56.4 23.365 ;
     RECT  59.412 23.317 60.432 23.941 ;
     RECT  91.812 23.317 93.312 25.189 ;
     RECT  98.616 23.317 99.6 24.325 ;
     RECT  119.928 23.317 121.008 24.373 ;
     RECT  75.612 23.365 76.848 24.181 ;
     RECT  76.872 23.365 78 24.517 ;
     RECT  103.896 23.365 104.88 24.613 ;
     RECT  108.792 23.365 110.112 23.411 ;
     RECT  116.568 23.365 117.984 23.893 ;
     RECT  81.816 23.411 83.4 23.413 ;
     RECT  89.112 23.411 90.288 24.563 ;
     RECT  108.792 23.411 110.16 23.507 ;
     RECT  122.328 23.411 123.648 23.987 ;
     RECT  57.336 23.413 58.608 23.557 ;
     RECT  81.816 23.413 83.136 23.941 ;
     RECT  84.648 23.413 86.1 24.325 ;
     RECT  108.792 23.507 110.256 24.035 ;
     RECT  94.512 23.749 95.904 25.621 ;
     RECT  72.912 23.797 74.256 24.517 ;
     RECT  81.816 23.941 82.8 24.517 ;
     RECT  68.904 23.987 69.9 25.141 ;
     RECT  86.412 23.987 86.616 25.093 ;
     RECT  122.28 23.987 123.648 25.429 ;
     RECT  127.032 23.987 128.16 24.563 ;
     RECT  99.912 23.989 101.376 25.045 ;
     RECT  108.792 24.035 110.304 25.141 ;
     RECT  64.968 24.517 66.192 24.997 ;
     RECT  73.128 24.517 74.256 25.093 ;
     RECT  89.112 24.563 91.5 24.949 ;
     RECT  124.584 24.563 125.808 24.707 ;
     RECT  126.912 24.563 128.16 24.611 ;
     RECT  119.64 24.611 120.72 25.621 ;
     RECT  46.872 24.613 48.3 25.187 ;
     RECT  124.212 24.707 125.808 25.139 ;
     RECT  89.112 24.949 91.392 25.669 ;
     RECT  78.984 24.997 80.4 25.093 ;
     RECT  79.128 25.093 80.112 25.525 ;
     RECT  124.212 25.139 126.6 26.101 ;
     RECT  92.04 25.189 93.312 25.669 ;
     RECT  62.664 25.381 63.696 25.621 ;
     RECT  122.28 25.429 123.6 25.669 ;
     RECT  89.352 25.669 91.104 25.717 ;
     RECT  89.352 25.717 90.528 26.819 ;
     RECT  48.612 25.861 49.968 26.101 ;
     RECT  48.984 26.101 49.968 26.293 ;
     RECT  124.212 26.101 125.28 26.149 ;
     RECT  125.304 26.101 126.6 26.485 ;
     RECT  124.212 26.149 125.184 26.197 ;
     RECT  48.984 26.819 49.968 27.925 ;
     RECT  89.112 26.819 90.528 27.349 ;
     RECT  89.112 27.349 90.24 27.877 ;
     RECT  127.704 27.637 128.928 28.261 ;
     RECT  42.9 28.103 43.584 28.741 ;
     RECT  88.584 28.103 89.664 30.108 ;
     RECT  128.952 28.103 129.612 28.165 ;
     RECT  128.952 28.165 130.176 29.077 ;
     RECT  127.848 28.261 128.928 30.108 ;
     RECT  43.608 28.453 44.976 28.501 ;
     RECT  46.872 28.453 48.24 29.077 ;
     RECT  43.608 28.501 44.832 30.085 ;
     RECT  42.504 28.741 43.584 30.037 ;
     RECT  46.872 29.077 48.096 29.605 ;
     RECT  129.096 29.077 130.176 30.085 ;
     RECT  46.872 29.605 47.952 30.108 ;
     RECT  42.6 30.037 43.584 30.108 ;
     RECT  43.848 30.085 44.832 30.108 ;
     RECT  129.096 30.085 130.08 30.108 ;
     RECT  42.6 30.108 43.536 30.179 ;
     RECT  43.848 30.108 44.784 30.224 ;
     RECT  46.92 30.108 47.904 30.224 ;
     RECT  88.632 30.108 89.616 30.224 ;
     RECT  127.896 30.108 128.88 30.224 ;
     RECT  129.144 30.108 130.08 30.224 ;
     RECT  42.552 30.179 43.536 30.224 ;
  END
END dsfd_sstn_e0e1c0c1_cp1
END LIBRARY
